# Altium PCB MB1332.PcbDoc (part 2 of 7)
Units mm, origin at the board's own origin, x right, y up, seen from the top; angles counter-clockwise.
Board outline 161 x 75 mm, 6 copper layers (Top Layer, Signal Layer 1, Signal Layer 2, Signal Layer 3, Signal Layer 4, Bottom Layer), stack 1.57 mm thick; 387 components, 358 nets, 1659 pads, 1180 vias.

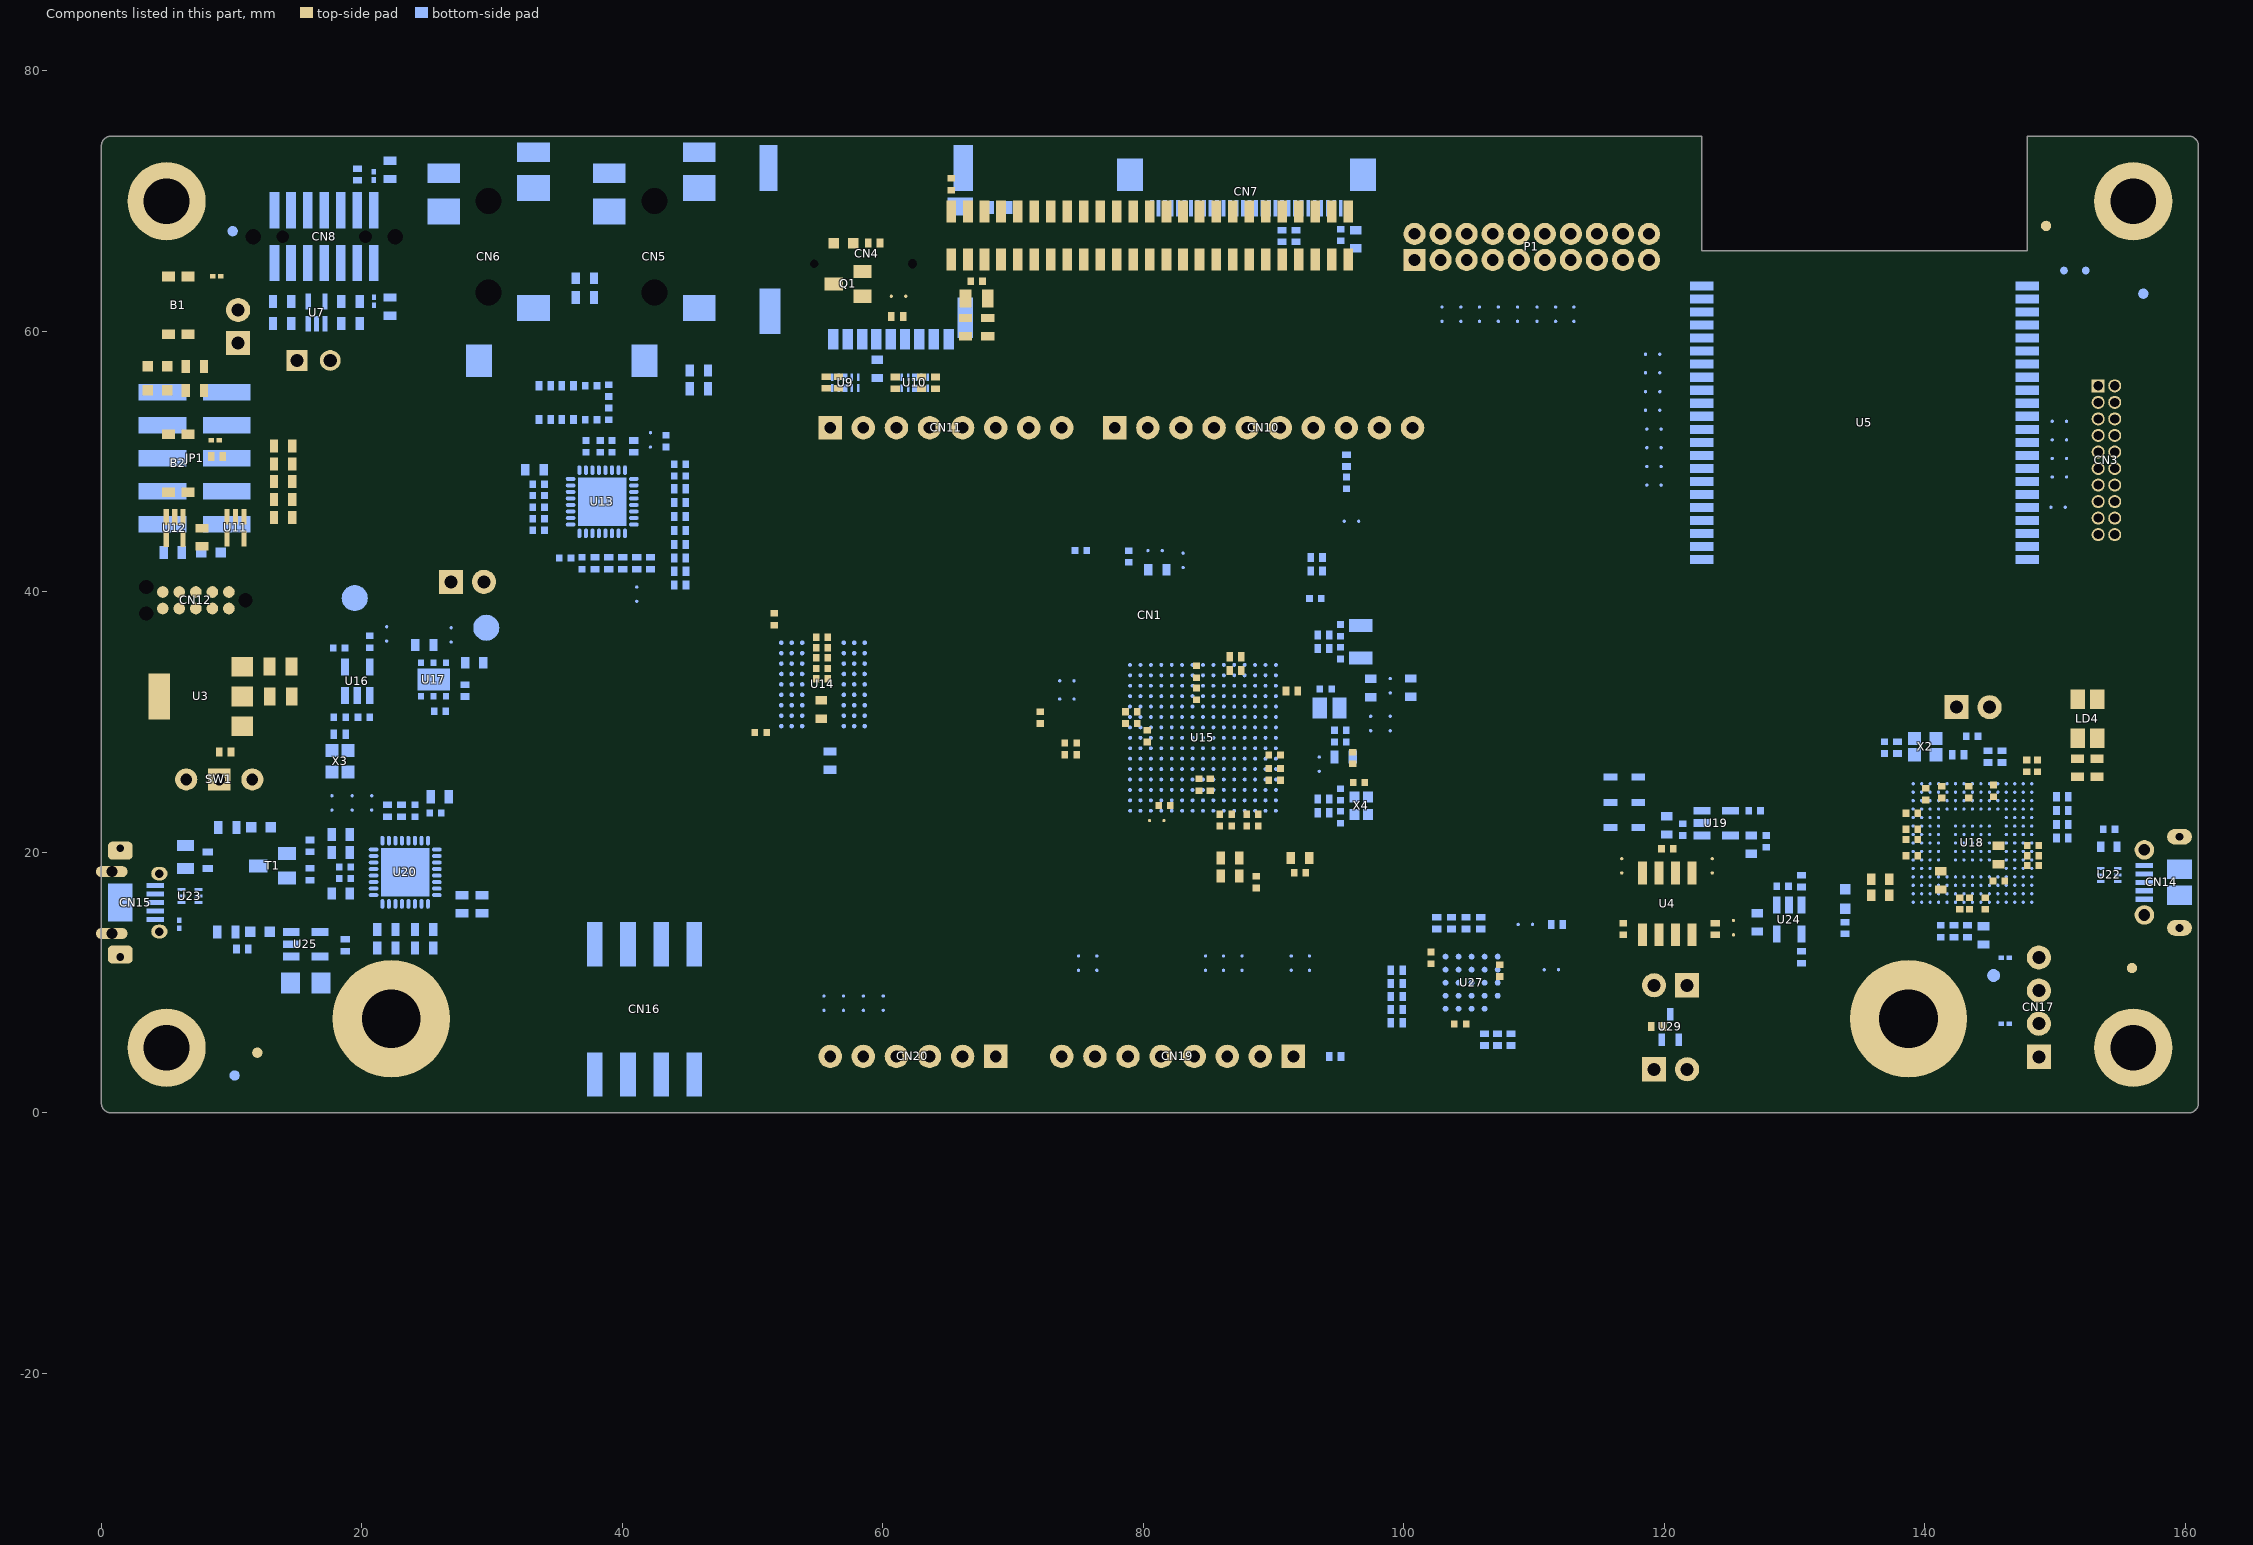
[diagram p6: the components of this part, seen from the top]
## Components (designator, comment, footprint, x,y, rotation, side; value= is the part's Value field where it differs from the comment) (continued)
R81 "Resistor" R0603 18.375,21.375 r180 bottom value=8K06
R82 "Resistor" R0402 150.55,21.1 r180 bottom value=4K7
R83 "Resistor" R0402 16.025,20.5 r270 bottom value=47K
R84 "Resistor" R0805 6.45,19.65 r90 bottom value=0R
R85 "Resistor" R0603 18.375,20 r180 bottom value=820R
R86 "Resistor" R0402 16.025,18.325 r270 bottom value=10K
R87 "Resistor" R0402 130.525,17.8 r270 bottom value=100K
R88 "Resistor" R0603 29.225,16.025 r90 bottom value=0R
R89 "Resistor" R0603 27.7,16.025 r270 bottom value=0R
R90 "Resistor" R0603 9.6,13.9 r180 bottom value=620R
R91 "Resistor" R0402 105.9,14.575 r90 bottom value=33R
R92 "Resistor" R0402 104.775,14.575 r270 bottom value=33R
R93 "Resistor" R0402 103.65,14.575 r90 bottom value=33R
R94 "Resistor" R0402 102.525,14.575 r270 bottom value=33R
R95 "Resistor" R0402 18.725,12.875 r270 bottom value=10K
R96 "Resistor" R0402 133.875,14.2 r270 bottom value=820R
R97 "Resistor" R0402 111.75,14.475 r0 bottom value=10K
R98 "Resistor" R0402 143.275,13.95 r90 bottom value=3K
R99 "Resistor" R0402 142.225,13.95 r270 bottom value=100R
R100 "Resistor" R0603 24.775,14.075 r180 bottom value=0R
R101 "Resistor" R0603 21.875,14.075 r0 bottom value=0R
R102 "Resistor" R0402 10.825,12.6 r180 bottom value=3K3
R103 "Resistor" R0603 24.775,12.65 r0 bottom value=0R
R104 "Resistor" R0603 21.875,12.65 r180 bottom value=0R
R105 "Resistor" R0402 130.525,11.95 r270 bottom value=10K
R106 "Resistor" R0402 99.45,10.95 r0 bottom value=33R
R107 "Resistor" R0402 99.45,9.95 r180 bottom value=33R
R108 "Resistor" R0402 99.45,8.95 r180 bottom value=33R
R109 "Resistor" R0402 99.45,7.95 r0 bottom value=33R
R110 "Resistor" R0402 99.45,6.925 r0 bottom value=33R
R111 "Resistor" R0402 108.225,5.625 r270 bottom value=33R
R112 "Resistor" R0402 107.2,5.625 r270 bottom value=33R
R113 "Resistor" R0402 106.175,5.625 r90 bottom value=10K
R114 "Resistor" R0402 94.725,4.325 r0 bottom value=1K
R115 "Resistor" R0402 61.1,61.15 r180 top value=1M
SB1 "SB_ON" SOLDER-BRIDGE_R0603-0R 61.25,62.7 r180 top value=0R
SB2 "SB_ON" SOLDER-BRIDGE_R0603-0R 81.075,22.448 r180 top value=0R
SB3 "SB_ON" SOLDER-BRIDGE_R0603-0R 116.725,18.925 r90 top value=0R
SB4 "SB_ON" SOLDER-BRIDGE_R0603-0R 123.675,18.925 r90 top value=0R
SB5 "SB_ON" SOLDER-BRIDGE_R0603-0R 125.3,14.175 r90 top value=0R
SB6 "SB_ON" SOLDER-BRIDGE_R0603-0R 104.375,61.275 r90 bottom value=0R
SB7 "SB_ON" SOLDER-BRIDGE_R0603-0R 102.925,61.275 r90 bottom value=0R
SB8 "SB_ON" SOLDER-BRIDGE_R0603-0R 107.25,61.275 r90 bottom value=0R
SB9 "SB_ON" SOLDER-BRIDGE_R0603-0R 105.8,61.275 r90 bottom value=0R
SB10 "SB_ON" SOLDER-BRIDGE_R0603-0R 110.225,61.275 r90 bottom value=0R
SB11 "SB_ON" SOLDER-BRIDGE_R0603-0R 108.725,61.275 r90 bottom value=0R
SB12 "SB_ON" SOLDER-BRIDGE_R0603-0R 113.05,61.275 r90 bottom value=0R
SB13 "SB_ON" SOLDER-BRIDGE_R0603-0R 111.65,61.275 r90 bottom value=0R
SB14 "SB_ON" SOLDER-BRIDGE_R0603-0R 119.15,58.25 r180 bottom value=0R
SB15 "SB_ON" SOLDER-BRIDGE_R0603-0R 119.15,56.825 r180 bottom value=0R
SB16 "SB_ON" SOLDER-BRIDGE_R0603-0R 119.15,55.375 r180 bottom value=0R
SB17 "SB_ON" SOLDER-BRIDGE_R0603-0R 119.15,53.95 r180 bottom value=0R
SB18 "SB_ON" SOLDER-BRIDGE_R0603-0R 150.275,53.1 r0 bottom value=0R
SB19 "SB_ON" SOLDER-BRIDGE_R0603-0R 119.15,52.5 r0 bottom value=0R
SB20 "SB_ON" SOLDER-BRIDGE_R0603-0R 42.15,51.725 r270 bottom value=0R
SB21 "SB_ON" SOLDER-BRIDGE_R0603-0R 150.275,51.675 r0 bottom value=0R
SB22 "SB_ON" SOLDER-BRIDGE_R0603-0R 119.15,51.075 r0 bottom value=0R
SB23 "SB_ON" SOLDER-BRIDGE_R0603-0R 150.275,50.25 r0 bottom value=0R
SB24 "SB_ON" SOLDER-BRIDGE_R0603-0R 119.15,49.625 r0 bottom value=0R
SB25 "SB_ON" SOLDER-BRIDGE_R0603-0R 150.275,48.825 r0 bottom value=0R
SB26 "SB_ON" SOLDER-BRIDGE_R0603-0R 119.15,48.2 r0 bottom value=0R
SB27 "SB_ON" SOLDER-BRIDGE_R0603-0R 150.275,46.5 r180 bottom value=0R
SB28 "SB_ON" SOLDER-BRIDGE_R0603-0R 96.025,45.425 r180 bottom value=0R
SB29 "SB_ON" SOLDER-BRIDGE_R0603-0R 80.85,43.173 r0 bottom value=0R
SB30 "SB_ON" SOLDER-BRIDGE_R0603-0R 83.05,42.473 r270 bottom value=0R
SB31 "SB_ON" SOLDER-BRIDGE_R0603-0R 41.1,39.775 r90 bottom value=0R
SB32 "SB_ON" SOLDER-BRIDGE_R0603-0R 21.9,36.725 r90 bottom value=0R
SB33 "SB_ON" SOLDER-BRIDGE_R0603-0R 26.85,36.65 r90 bottom value=0R
SB34 "SB_ON" SOLDER-BRIDGE_R0603-0R 98.95,32.848 r270 bottom value=0R
SB35 "SB_ON" SOLDER-BRIDGE_R0603-0R 74.075,33.173 r0 bottom value=0R
SB36 "SB_ON" SOLDER-BRIDGE_R0603-0R 74.075,31.773 r0 bottom value=0R
SB37 "SB_ON" SOLDER-BRIDGE_R0603-0R 98.95,29.848 r90 bottom value=0R
SB38 "SB_ON" SOLDER-BRIDGE_R0603-0R 97.45,29.848 r90 bottom value=0R
SB39 "SB_ON" SOLDER-BRIDGE_R0603-0R 93.5,26.723 r90 bottom value=0R
SB40 "SB_ON" SOLDER-BRIDGE_R0603-0R 20.75,23.75 r90 bottom value=0R
SB41 "SB_ON" SOLDER-BRIDGE_R0603-0R 19.25,23.75 r90 bottom value=0R
SB42 "SB_ON" SOLDER-BRIDGE_R0603-0R 17.7,23.75 r90 bottom value=0R
SB43 "SB_ON" SOLDER-BRIDGE_R0603-0R 109.275,14.475 r0 bottom value=0R
SB44 "SB_ON" SOLDER-BRIDGE_R0603-0R 92.75,11.55 r270 bottom value=0R
SB45 "SB_ON" SOLDER-BRIDGE_R0603-0R 91.35,11.55 r270 bottom value=0R
SB46 "SB_ON" SOLDER-BRIDGE_R0603-0R 87.575,11.55 r270 bottom value=0R
SB47 "SB_ON" SOLDER-BRIDGE_R0603-0R 84.775,11.55 r270 bottom value=0R
SB48 "SB_ON" SOLDER-BRIDGE_R0603-0R 76.425,11.55 r270 bottom value=0R
SB49 "SB_ON" SOLDER-BRIDGE_R0603-0R 75.025,11.55 r270 bottom value=0R
SB50 "SB_ON" SOLDER-BRIDGE_R0603-0R 86.15,11.55 r270 bottom value=0R
SB51 "SB_ON" SOLDER-BRIDGE_R0603-0R 111.375,11 r180 bottom value=0R
SB52 "SB_ON" SOLDER-BRIDGE_R0603-0R 60.025,8.475 r270 bottom value=0R
SB53 "SB_ON" SOLDER-BRIDGE_R0603-0R 58.5,8.475 r270 bottom value=0R
SB54 "SB_ON" SOLDER-BRIDGE_R0603-0R 56.975,8.475 r270 bottom value=0R
SB55 "SB_ON" SOLDER-BRIDGE_R0603-0R 55.475,8.475 r270 bottom value=0R
SW1 "SW_MECA_1K2" SWI_EAO_09-03290-01_EXTENDED_STRAIGHT_BLACK 9.05,25.6 r90 top value=09.03290.01
T1 "9013-SOT23" NPN_SOT23 13.15,18.975 r270 bottom value="NPN SOT23"
TP1 "Test Point" TP_SMD_2MM 19.45,39.525 r180 bottom
TP2 "Test Point" TP_SMD_2MM 29.55,37.25 r180 bottom
TP3 "Test Point" TP_SMD_1MM 145.275,10.55 r270 bottom value="Test Point 1mm"
TP4 "Test Point" TP_SMD_0-6MM 152.35,64.675 r90 bottom
TP5 "Test Point" TP_SMD_0-6MM 150.675,64.675 r90 bottom
U1 "ESD-TRANSIL" ESD_ST0201 8.85,64.225 r0 top value=ESDALC6V1-1U2
U2 "ESD-TRANSIL" ESD_ST0201 8.737,51.65 r0 top value=ESDALC6V1-1U2
U3 "LD1117S50TR" REG_SOT223-TAB 7.624,31.972 r90 top
U4 "MCP2562FD" ICC_SO8_5X4_P127 120.225,16.05 r180 top value=MCP2562FDT-H/SN
U5 "WIFI MODULE INTERPOSER" MOD_WIFI_INVENTEK_ISM43362 135.361,54.785 r180 bottom value=MB1486
U6 "ESD-TRANSIL" ESD_ST0201 20.9,71.937 r90 bottom value=ESDALC6V1-1U2
U7 "ESDALC6V1W5" ESD_SOT323-5L 16.525,61.45 r180 bottom
U8 "ESD-TRANSIL" ESD_ST0201 20.925,62.325 r270 bottom value=ESDALC6V1-1U2
U9 "HSP051-4M10" ESD_UQFN-10L_2P5X1_P050 57.1,56.065 r0 bottom
U10 "HSP051-4M10" ESD_UQFN-10L_2P5X1_P050 62.45,56.06 r0 bottom
U11 "ESDALC6V1W5" ESD_SOT323-5L 10.3,44.925 r180 top
U12 "ESDALC6V1W5" ESD_SOT323-5L 5.625,44.9 r180 top
U13 "CS42L51-CNZ" ICC_QFN32-EPAD_5X5_P050 38.45,46.925 r180 bottom
U14 "IS42S16800F-6BLI" ICC_TFBGA54_3X9-BALL-X2_8X8_P080 55.4,32.9 r180 bottom
U15 "STM32H7B3NIH6Q" ICC_TFBGA225_13X13_STM32H7B3NIH6Q_P080 84.575,28.798 r180 bottom value=STM32H7B3LIH6Q
U16 "LD3985M18R" REG_SOT23-5L 19.65,33.15 r180 bottom
U17 "ST1L05CPU33R" ICC_DFN6-EPAD_3X3_P095 25.5,33.275 r180 bottom
U18 "ST-LINKV3E_SWD" ICC_UFBGA201_176+25_10X10_P065 143.65,20.725 r270 bottom value=STM32F723IEK6
U19 "LD3985M33R" REG_SOT23-5L 123.975,22.25 r90 bottom
U20 "USB3320C-EZK" ICC_QFN32-EPAD_5X5_P050 23.325,18.475 r270 bottom value=USB3320C-EZK-TR
U21 "ESD-TRANSIL" ESD_QFN2_1P6X1_P125 8.175,19.4 r90 bottom value=ESDA7P60-1U1M
U22 "ECMF02-2AMX6" ESD_QFN-6L_1P7X1P5_P050 154.15,18.275 r90 bottom
U23 "ECMF02-2AMX6" ESD_QFN-6L_1P7X1P5_P050 6.8,16.65 r270 bottom
U24 "STMPS2151STR" MOS_SOT23-5L 129.575,14.85 r0 bottom
U25 "STMPS2151STR" MOS_SOT23-5L 15.675,12.95 r90 bottom
U26 "ESD-TRANSIL" ESD_ST0201 5.975,14.475 r270 bottom value=ESDALC6V1-1U2
U27 "MX25LM51245GXDI00" ICC_BGA24_5X5-BALL-ARRAY_6X8_P1 105.2,10 r90 bottom
U28 "ESD-TRANSIL" ESD_ST0201 146.175,11.925 r180 bottom value=ESDALC6V1-1U2
U29 "ESD-TRANSIL-DUAL-BIDIR" DIO_SOT323 120.45,6.6 r180 bottom value=ESDCAN02-2BWY
U30 "ESD-TRANSIL" ESD_ST0201 146.175,6.85 r180 bottom value=ESDALC6V1-1U2
X1 "XTAL_2_PINS" CRY_NX3215SA_2P 96.675,36.173 r90 bottom value=32.768KHz
X2 "OSCILLATOR_4_PINS" OSC_NDK_NZ2520SB_4P 140.025,28.125 r0 bottom value=25MHz
X3 "OSCILLATOR_4_PINS" OSC_NDK_NZ2520SB_4P 18.325,27 r270 bottom value=24MHz
X4 "XTAL_4_PINS" CRY_NX2016SA_4P 96.725,23.573 r90 bottom value=24MHz

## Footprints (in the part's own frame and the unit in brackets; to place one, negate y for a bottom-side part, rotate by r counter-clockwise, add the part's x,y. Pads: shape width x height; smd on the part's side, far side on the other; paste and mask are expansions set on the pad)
C0402 [mm]
  rect 0.51x0.56 smd mask+0.05: 1(-0.45,0) 2(0.45,0)
  silkscreen extent 0,-0.3 0,0.3, body extent -0.5,-0.3 0.5,0.3, height 0.4
C0603 [mm]
  rect 0.64x0.89 smd mask+0.05: 1(-0.7,0) 2(0.7,0)
  silkscreen extent -1.05,-0.55 1.02,0.55, body extent -0.9,-0.5 0.9,0.5, height 1.4
C0805 [mm]
  rect 0.9x1.4 smd mask+0.05: 1(-0.85,0) 2(0.85,0)
  silkscreen extent -1.3,-0.77 1.3,0.77, body extent -1.1,-0.7 1.1,0.7, height 1.35
CON_988-JIUBABA_PHFS25-11-02-G0B115-T-1 [mm]
  rect 1.6x1.6 hole 1 mask+0.05: 1(1.27,0)
  round 1.6 hole 1 mask+0.05: 2(-1.27,0)
  silkscreen extent -2.71,-1.33 2.71,1.33, body extent -2.71,-1.33 2.71,1.33, height 8.85
CON_FISCHER_BL1-6-G [mm]
  rect 1.8x1.8 / inner round 1.8 / far side rect 1.8x1.8 hole 0.9 mask+0.05: 1(-6.35,0)
  round 1.8 hole 0.9 mask+0.05: 2(-3.81,0) 3(-1.27,0) 4(1.27,0) 5(3.81,0) 6(6.35,0)
  silkscreen extent -7.62,-1.25 7.62,1.25, body extent -7.62,-1.25 7.62,1.25, height 8
CON_FISCHER_BL1-8-G [mm]
  rect 1.8x1.8 / inner round 1.8 / far side rect 1.8x1.8 hole 0.9 mask+0.05: 1(-8.89,0)
  round 1.8 hole 0.9 mask+0.05: 2(-6.35,0) 3(-3.81,0) 4(-1.27,0) 5(1.27,0) 6(3.81,0) 7(6.35,0) 8(8.89,0)
  silkscreen extent -10.16,-1.25 10.16,1.25, body extent -10.16,-1.25 10.16,1.25, height 8
CON_FISCHER_BL1-10-G [mm]
  rect 1.8x1.8 / inner round 1.8 / far side rect 1.8x1.8 hole 0.9 mask+0.05: 1(-11.43,0)
  round 1.8 hole 0.9 mask+0.05: 2(-8.89,0) 3(-6.35,0) 4(-3.81,0) 5(-1.27,0) 6(1.27,0) 7(3.81,0) 8(6.35,0) 9(8.89,0) 10(11.43,0)
  silkscreen extent -12.7,-1.25 12.71,1.25, body extent -12.7,-1.25 12.7,1.25, height 8
CON_MICROSD_YAMAICHI_PJS008-2003-1 [mm] "WITH POSITIONNING PINS"
  rect 1.6x0.8 smd paste+0 mask+0.05: 1(-15.6,-2.525) 2(-15.6,-1.425) 3(-15.6,-0.325) 4(-15.6,0.775) 5(-15.6,1.875) 6(-15.6,2.975) 7(-15.6,4.075) 8(-15.6,5.175) 9(-15.6,6.325)
  rect 1.4x1.95 smd paste+0 mask+0.05: 10(-5.4,7.225)
  rect 3.5x1.5 smd paste+0 mask+0.05: 11(-2.45,7.45)
  rect 3.5x1.4 smd paste+0 mask+0.05: 12(-2.45,-7.5)
  rect 3.5x1.6 smd paste+0 mask+0.05: 13(-13.45,-7.4)
  rect 3.1x1.2 smd paste+0 mask+0.05: 14(-13.95,7.6)
  round 0 hole 0.65 unplated mask+0.05: NPTH1(-9.8,-4)
  round 0 hole 0.7 unplated mask+0.05: NPTH2(-9.8,3.55)
  silkscreen extent -15.32,-7.25 5.65,7.25, body extent -15.25,-7.25 -0.45,7.42, height 2
CON_PHONE-JACK-3P5_HY_PJ3028B [mm]
  rect 1.5x2.5 smd mask+0.05: 2(1.25,-3.45) 7(2.85,3.45)
  rect 2x2.5 smd mask+0.05: 3(4,-3.45) 4(5.8,3.45) 6(13.2,-3.45)
  rect 2.5x2 smd mask+0.05: 5(17.25,0.75)
  round 0.5 hole 2 unplated mask+0.1: MT1(5,0) MT2(12,0)
  Multi-Layer keep-out circle w0.01: c12,0 r1.25
  Multi-Layer keep-out circle w0.01: c5,0 r1.25
  silkscreen extent -0.9,-3.7 16,3, body extent -0.9,-3 16,3, height 5
CON_SAMTEC_SQT-110-01-F-D-RA__STMOD+ [mm] "SQT-110-01-F-D-RA (connecteur SAMTEC pour interface STMod+ femelle coté Host) Pinning adapté non conforme SAMTEC."
  rect 1.7x1.7 hole 0.9 mask+0.05: 1(9,1)
  round 1.7 hole 0.9 mask+0.05: 2(7,1) 3(5,1) 4(3,1) 5(1,1) 6(-1,1) 7(-3,1) 8(-5,1) 9(-7,1) 10(-9,1) 11(9,-1) 12(7,-1) 13(5,-1) 14(3,-1) 15(1,-1) 16(-1,-1) 17(-3,-1) 18(-5,-1) 19(-7,-1) 20(-9,-1)
  silkscreen extent -10.15,-8.62 10.15,0.07, body extent -10.15,-8.65 10.15,1.22, height 4
CON_SAMTEC_SSM-104-L-DH [mm]
  rect 1.2x3.4 smd mask+0.05: 1(3.81,-5) 2(3.81,5) 3(1.27,-5) 4(1.27,5) 5(-1.27,-5) 6(-1.27,5) 7(-3.81,-5) 8(-3.81,5)
  silkscreen extent -5.08,-4.06 5.08,4.06, body extent -5.08,-5.46 5.1,5.46, height 5.92
CON_SAMTEC_TSM-105-01-L-DV [mm]
  rect 1.27x3.68 smd paste+0 mask+0.05: 1(-5.08,-2.475) 2(-5.08,2.475) 3(-2.54,-2.475) 4(-2.54,2.475) 5(0,-2.475) 6(0,2.475) 7(2.54,-2.475) 8(2.54,2.475) 9(5.08,-2.475) 10(5.08,2.475)
  silkscreen extent -6.35,-2.16 6.35,2.16, body extent -6.35,-3.85 6.35,3.85, height 9.65
CON_SAMTEC_TSW-102-07-G-S [mm]
  rect 1.85x1.85 / inner round 1.85 / far side rect 1.85x1.85 hole 1 mask+0.05: 1(-1.27,0)
  round 1.85 hole 1 mask+0.05: 2(1.27,0)
  silkscreen extent -2.58,-1.3 2.58,1.3, body extent -2.67,-1.3 2.58,1.3, height 8.38
CON_SAMTEC_TSW-104-07-G-S [mm]
  rect 1.85x1.85 / inner round 1.85 / far side rect 1.85x1.85 hole 1 mask+0.05: 1(-3.81,0)
  round 1.85 hole 1 mask+0.05: 2(-1.27,0) 3(1.27,0) 4(3.81,0)
  silkscreen extent -5.12,-1.3 5.12,1.3, body extent -5.21,-1.37 5.18,1.37, height 8.38
CON_STDC14_Receiver_MEDIUM_WITH_MIPI10_3D [mm] "compatible with FTSH-105-01-L-DV,-K and FTSH-107-01-L-DV,-K,-A,-P,-ES"
  round 0 hole 1.19 unplated mask+0.05: 0(-5.445,0) 0(5.445,0)
  round 0 hole 0.97 unplated mask+0.05: 0(-3.175,0) 0(3.175,0)
  rect 0.74x2.79 smd mask+0.05: 1(-3.81,-2.032) 2(-3.81,2.032) 3(-2.54,-2.032) 4(-2.54,2.032) 5(-1.27,-2.032) 6(-1.27,2.032) 7(0,-2.032) 8(0,2.032) 9(1.27,-2.032) 10(1.27,2.032) 11(2.54,-2.032) 12(2.54,2.032) 13(3.81,-2.032) 14(3.81,2.032)
  silkscreen extent -6.3,-4.38 6.3,3.6, body extent -6.3,-2.92 6.3,2.92, height 6.6
CON_TAG-C_TC2050-IDC-NL [mm]
  round 0.9 smd paste+0 mask+0.05: 1(-2.54,-0.635) 2(-1.27,-0.635) 3(0,-0.635) 4(1.27,-0.635) 5(2.54,-0.635) 6(2.54,0.635) 7(1.27,0.635) 8(0,0.635) 9(-1.27,0.635) 10(-2.54,0.635)
  round 0 hole 1.1 unplated mask+0.05: 11(-3.81,0) 12(3.81,-1.015) 13(3.81,1.015)
  Multi-Layer keep-out circle w0.01: c-3.81,0 r0.75
  Multi-Layer keep-out circle w0.01: c3.81,1.015 r0.75
  Multi-Layer keep-out circle w0.01: c3.81,-1.015 r0.75
  silkscreen extent -6.22,-3.4 6.22,3.33, body extent -6.28,-3.46 6.28,3.39, height 13
CON_TOWNES_FPU330ZH-BT1D3-CA_P050 [mm]
  rect 0.3x1.25 smd mask+0.05: 1(-7.25,2.575) 2(-6.75,2.575) 3(-6.25,2.575) 4(-5.75,2.575) 5(-5.25,2.575) 6(-4.75,2.575) 7(-4.25,2.575) 8(-3.75,2.575) 9(-3.25,2.575) 10(-2.75,2.575) 11(-2.25,2.575) 12(-1.75,2.575) 13(-1.25,2.575) 14(-0.75,2.575) 15(-0.25,2.575) 16(0.25,2.575) 17(0.75,2.575) 18(1.25,2.575) 19(1.75,2.575) 20(2.25,2.575) 21(2.75,2.575) 22(3.25,2.575) 23(3.75,2.575) 24(4.25,2.575) 25(4.75,2.575) 26(5.25,2.575) 27(5.75,2.575) 28(6.25,2.575) 29(6.75,2.575) 30(7.25,2.575)
  rect 2x2.5 smd mask+0.05: 31(-8.94,0) 32(8.94,0)
  silkscreen extent -9.7,-2.9 9.7,2.3, body extent -10.25,-4.25 10.25,3, height 2.05
CON_USBMICROAB_MOLEX_47590-0001_H3 [mm]
  rect 0.4x1.35 smd mask+0.05: 1(1.3,4.125) 2(0.65,4.125) 3(0,4.125) 4(-0.65,4.125) 5(-1.3,4.125)
  oval 1.05x1.25 hole 0.65 slot 0.85 at 90 deg mask+0.05: 6(-2.225,4.45) 7(2.225,4.45)
  rrect50% 1.375x1.9 hole 0.6 slot 1.3 at 90 deg copper offset 0.188,0 mask+0.05: 8(-4.175,1.45)
  rrect50% 1.375x1.9 hole 0.6 slot 1.3 at 90 deg copper offset -0.188,0 mask+0.05: 9(4.175,1.45)
  rect 2.9x1.9 smd mask+0.05: 10(0,1.45)
  oval 0.85x2.425 hole 0.85 slot 2.425 at 90 deg unplated mask+0.1: 11(-2.375,0.8) 12(2.375,0.8)
  silkscreen extent -4.1,-1.3 4.1,4.3, body extent -4.32,-1.36 4.33,4.6, height 3
CON_USBMICROB_MOLEX_105017-0001_H2P90 [mm]
  rect 0.4x1.35 smd mask+0.05: 1(-1.3,4.15) 2(-0.65,4.15) 3(0,4.15) 4(0.65,4.15) 5(1.3,4.15)
  round 1.5 hole 0.9 mask+0.05: 6(-2.5,4.15) 7(2.5,4.15)
  oval 1.2x1.9 hole 0.6 slot 1.3 at 90 deg mask+0.05: 8(3.5,1.45) 9(-3.5,1.45)
  rect 1.5x1.9 smd mask+0.05: 10(-1,1.45) 11(1,1.45)
  Top Layer region: 2.3,2.4 3.5,2.4 3.5,0.5 2.3,0.5 2.3,2.4
  Top Layer region: -3.5,2.4 -2.3,2.4 -2.3,0.5 -3.5,0.5 -3.5,2.4
  silkscreen extent -4,-0.7 4,4.6, body extent -4.1,-1.15 4.1,4.66, height 2.9
CPOL_TAJ-A_1206_H180 [mm]
  rect 1.45x1.6 smd mask+0.05: 1(-1.175,0) 2(1.175,0)
  silkscreen extent -2.15,-1.05 1.7,1.05, body extent -1.7,-0.9 1.7,0.9, height 1.8
CRY_NX2016SA_4P [mm]
  rect 0.85x0.75 smd mask+0.05: 1(-0.675,-0.525) 2(0.675,-0.525) 3(0.675,0.525) 4(-0.675,0.525)
  silkscreen extent -1.22,-1.02 1.05,0.85, body extent -1.05,-0.85 1.05,0.85, height 0.7
CRY_NX3215SA_2P [mm]
  rect 1x1.8 smd mask+0.05: 1(-1.25,0) 2(1.25,0)
  silkscreen extent -0.63,-0.8 0.63,0.8, body extent -1.65,-0.8 1.65,0.8, height 0.9
DIO_SOD323 [mm]
  rect 1.06x0.54 smd mask+0.05: 1(-1.07,0) 2(1.07,0)
  silkscreen extent -0.9,-0.72 0.9,0.72, body extent -1.3,-0.78 1.3,0.78, height 1.17
DIO_SOT323 [mm]
  rect 0.5x0.95 smd mask+0.05: 1(-0.65,-0.975) 2(0.65,-0.975) 3(0,0.975)
  silkscreen extent -1.15,-0.67 1.15,0.67, body extent -1.15,-1.12 1.15,1.12, height 1.1
ESD_QFN2_1P6X1_P125 [mm]
  rect 0.55x0.8 smd mask+0.05: 1(-0.625,0) 2(0.625,0)
  silkscreen extent -1,-0.55 0.85,0.55, body extent -0.85,-0.55 0.85,0.55, height 0.61
ESD_QFN-6L_1P7X1P5_P050 [mm]
  rect 0.25x0.6 smd mask+0.05: 1(-0.5,-0.65) 2(0,-0.65) 3(0.5,-0.65) 4(0.5,0.65) 5(0,0.65) 6(-0.5,0.65)
  silkscreen extent -0.9,-0.8 0.9,0.8, body extent -0.9,-0.8 0.9,0.8, height 0.56
ESD_SOT323-5L [mm]
  rect 0.4x1.2 smd mask+0.05: 1(-0.65,-0.85) 2(0,-0.85) 3(0.65,-0.85) 4(0.65,0.85) 5(-0.65,0.85)
  silkscreen extent -1.22,-1.21 1.22,0.77, body extent -1.15,-1.05 1.15,1.05, height 1.1
ESD_ST0201 [mm]
  rect 0.425x0.33 smd mask+0.05: 1(-0.312,0) 2(0.312,0)
  silkscreen extent -0.55,-0.3 0.33,0.3, body extent -0.34,-0.18 0.34,0.18, height 0.34
ESD_UQFN-10L_2P5X1_P050 [mm]
  rect 0.2x0.58 smd mask+0.05: 1(-1,-0.41) 2(-0.5,-0.41) 4(0.5,-0.41) 5(1,-0.41) 6(1,0.41) 7(0.5,0.41) 9(-0.5,0.41) 10(-1,0.41)
  rect 0.4x0.58 smd mask+0.05: 3(0,-0.41) 8(0,0.41)
  silkscreen extent -1.38,-0.63 1.38,0.63, body extent -1.3,-0.55 1.3,0.55, height 0.51
ICC_BGA24_5X5-BALL-ARRAY_6X8_P1 [mm]
  round 0.45 smd mask+0.05: A2(-1,2) A3(0,2) A4(1,2) A5(2,2) B1(-2,1) B2(-1,1) B3(0,1) B4(1,1) B5(2,1) C1(-2,0) C2(-1,0) C3(0,0) C4(1,0) C5(2,0) D1(-2,-1) D2(-1,-1) D3(0,-1) D4(1,-1) D5(2,-1) E1(-2,-2) E2(-1,-2) E3(0,-2) E4(1,-2) E5(2,-2)
  silkscreen extent -3.05,-4.05 3.05,4.05, body extent -3.05,-4.05 3.05,4.05, height 1.2
ICC_DFN6-EPAD_3X3_P095 [mm]
  rect 0.45x0.5 smd mask+0.05: 1(-0.95,-1.3) 2(0,-1.3) 3(0.95,-1.3) 4(0.95,1.3) 5(0,1.3) 6(-0.95,1.3)
  rect 2.5x1.7 smd mask+0.05: EP(0,0)
  silkscreen extent -1.55,-1.55 1.55,1.55, body extent -1.55,-1.55 1.55,1.55, height 1
ICC_QFN32-EPAD_5X5_P050 [mm]
  oval 0.3x0.75 smd mask+0.05: 1(-1.75,-2.425) 2(-1.25,-2.425) 3(-0.75,-2.425) 4(-0.25,-2.425) 5(0.25,-2.425) 6(0.75,-2.425) 7(1.25,-2.425) 8(1.75,-2.425) 17(1.75,2.425) 18(1.25,2.425) 19(0.75,2.425) 20(0.25,2.425) 21(-0.25,2.425) 22(-0.75,2.425) 23(-1.25,2.425) 24(-1.75,2.425)
  oval 0.75x0.3 smd mask+0.05: 9(2.425,-1.75) 10(2.425,-1.25) 11(2.425,-0.75) 12(2.425,-0.25) 13(2.425,0.25) 14(2.425,0.75) 15(2.425,1.25) 16(2.425,1.75) 25(-2.425,1.75) 26(-2.425,1.25) 27(-2.425,0.75) 28(-2.425,0.25) 29(-2.425,-0.25) 30(-2.425,-0.75) 31(-2.425,-1.25) 32(-2.425,-1.75)
  rect 3.7x3.7 smd mask+0.05: 33(0,0)
  silkscreen extent -2.63,-2.63 2.63,2.63, body extent -2.55,-2.55 2.55,2.55, height 1
ICC_SO8_5X4_P127 [mm]
  rect 0.7x1.75 smd mask+0.05: 1(-1.905,-2.375) 2(-0.635,-2.375) 3(0.635,-2.375) 4(1.905,-2.375) 5(1.905,2.375) 6(0.635,2.375) 7(-0.635,2.375) 8(-1.905,2.375)
  silkscreen extent -2.73,-3.25 2.58,2, body extent -2.57,-3 2.57,3, height 1.75
ICC_TFBGA54_3X9-BALL-X2_8X8_P080 [mm] "IPC"
  round 0.35 smd mask+0.05: A1(-3.2,3.2) A2(-2.4,3.2) A3(-1.6,3.2) A7(1.6,3.2) A8(2.4,3.2) A9(3.2,3.2) B1(-3.2,2.4) B2(-2.4,2.4) B3(-1.6,2.4) B7(1.6,2.4) B8(2.4,2.4) B9(3.2,2.4) C1(-3.2,1.6) C2(-2.4,1.6) C3(-1.6,1.6) C7(1.6,1.6) C8(2.4,1.6) C9(3.2,1.6) D1(-3.2,0.8) D2(-2.4,0.8) D3(-1.6,0.8) D7(1.6,0.8) D8(2.4,0.8) D9(3.2,0.8) E1(-3.2,0) E2(-2.4,0) E3(-1.6,0) E7(1.6,0) E8(2.4,0) E9(3.2,0) F1(-3.2,-0.8) F2(-2.4,-0.8) F3(-1.6,-0.8) F7(1.6,-0.8) F8(2.4,-0.8) F9(3.2,-0.8) G1(-3.2,-1.6) G2(-2.4,-1.6) G3(-1.6,-1.6) G7(1.6,-1.6) G8(2.4,-1.6) G9(3.2,-1.6) H1(-3.2,-2.4) H2(-2.4,-2.4) H3(-1.6,-2.4) H7(1.6,-2.4) H8(2.4,-2.4) H9(3.2,-2.4) J1(-3.2,-3.2) J2(-2.4,-3.2) J3(-1.6,-3.2) J7(1.6,-3.2) J8(2.4,-3.2) J9(3.2,-3.2)
  silkscreen extent -4.6,-4.05 4.05,4.05, body extent -4.05,-4.05 4.05,4.05, height 1.21
ICC_TFBGA225_13X13_STM32H7B3NIH6Q_P080 [mm] "IPC"
  round 0.3 smd mask+0.05: A1(-5.6,5.6) A2(-4.8,5.6) A3(-4,5.6) A4(-3.2,5.6) A5(-2.4,5.6) A6(-1.6,5.6) A7(-0.8,5.6) A8(0,5.6) A9(0.8,5.6) A10(1.6,5.6) A11(2.4,5.6) A12(3.2,5.6) A13(4,5.6) A14(4.8,5.6) A15(5.6,5.6) B1(-5.6,4.8) B2(-4.8,4.8) B3(-4,4.8) B4(-3.2,4.8) B5(-2.4,4.8) B6(-1.6,4.8) B7(-0.8,4.8) B8(0,4.8) B9(0.8,4.8) B10(1.6,4.8) B11(2.4,4.8) B12(3.2,4.8) B13(4,4.8) B14(4.8,4.8) B15(5.6,4.8) C1(-5.6,4) C2(-4.8,4) C3(-4,4) C4(-3.2,4) C5(-2.4,4) C6(-1.6,4) C7(-0.8,4) C8(0,4) C9(0.8,4) C10(1.6,4) C11(2.4,4) C12(3.2,4) C13(4,4) C14(4.8,4) C15(5.6,4) D1(-5.6,3.2) D2(-4.8,3.2) D3(-4,3.2) D4(-3.2,3.2) D5(-2.4,3.2) D6(-1.6,3.2) D7(-0.8,3.2) D8(0,3.2) D9(0.8,3.2) D10(1.6,3.2) D11(2.4,3.2) D12(3.2,3.2) D13(4,3.2) D14(4.8,3.2) D15(5.6,3.2) E1(-5.6,2.4) E2(-4.8,2.4) E3(-4,2.4) E4(-3.2,2.4) E5(-2.4,2.4) E6(-1.6,2.4) E7(-0.8,2.4) E8(0,2.4) E9(0.8,2.4) E10(1.6,2.4) E11(2.4,2.4) E12(3.2,2.4) E13(4,2.4) E14(4.8,2.4) E15(5.6,2.4) F1(-5.6,1.6) F2(-4.8,1.6) F3(-4,1.6) F4(-3.2,1.6) F5(-2.4,1.6) F6(-1.6,1.6) F7(-0.8,1.6) F8(0,1.6) F9(0.8,1.6) F10(1.6,1.6) F11(2.4,1.6) F12(3.2,1.6) F13(4,1.6) F14(4.8,1.6) F15(5.6,1.6) G1(-5.6,0.8) G2(-4.8,0.8) G3(-4,0.8) G4(-3.2,0.8) G5(-2.4,0.8) G6(-1.6,0.8) G7(-0.8,0.8) G8(0,0.8) G9(0.8,0.8) G10(1.6,0.8) G11(2.4,0.8) G12(3.2,0.8) G13(4,0.8) G14(4.8,0.8) G15(5.6,0.8) H1(-5.6,0) H2(-4.8,0) H3(-4,0) H4(-3.2,0) H5(-2.4,0) H6(-1.6,0) H7(-0.8,0) H8(0,0) H9(0.8,0) H10(1.6,0) H11(2.4,0) H12(3.2,0) H13(4,0) H14(4.8,0) H15(5.6,0) J1(-5.6,-0.8) J2(-4.8,-0.8) J3(-4,-0.8) J4(-3.2,-0.8) J5(-2.4,-0.8) J6(-1.6,-0.8) J7(-0.8,-0.8) J8(0,-0.8) J9(0.8,-0.8) J10(1.6,-0.8) J11(2.4,-0.8) J12(3.2,-0.8) J13(4,-0.8) J14(4.8,-0.8) J15(5.6,-0.8) K1(-5.6,-1.6) K2(-4.8,-1.6) K3(-4,-1.6) K4(-3.2,-1.6) K5(-2.4,-1.6) K6(-1.6,-1.6) K7(-0.8,-1.6) K8(0,-1.6) K9(0.8,-1.6) K10(1.6,-1.6) K11(2.4,-1.6) K12(3.2,-1.6) K13(4,-1.6) K14(4.8,-1.6) K15(5.6,-1.6) L1(-5.6,-2.4) L2(-4.8,-2.4) L3(-4,-2.4) L4(-3.2,-2.4) L5(-2.4,-2.4) L6(-1.6,-2.4) L7(-0.8,-2.4) L8(0,-2.4) L9(0.8,-2.4) L10(1.6,-2.4) L11(2.4,-2.4) L12(3.2,-2.4) L13(4,-2.4) L14(4.8,-2.4) L15(5.6,-2.4) M1(-5.6,-3.2) M2(-4.8,-3.2) M3(-4,-3.2) M4(-3.2,-3.2) M5(-2.4,-3.2) M6(-1.6,-3.2) M7(-0.8,-3.2) M8(0,-3.2) M9(0.8,-3.2) M10(1.6,-3.2) M11(2.4,-3.2) M12(3.2,-3.2) M13(4,-3.2) M14(4.8,-3.2) M15(5.6,-3.2) N1(-5.6,-4) N2(-4.8,-4) N3(-4,-4) N4(-3.2,-4) N5(-2.4,-4) N6(-1.6,-4) N7(-0.8,-4) N8(0,-4) N9(0.8,-4) N10(1.6,-4) N11(2.4,-4) N12(3.2,-4) N13(4,-4) N14(4.8,-4) N15(5.6,-4) P1(-5.6,-4.8) P2(-4.8,-4.8) P3(-4,-4.8) P4(-3.2,-4.8) P5(-2.4,-4.8) P6(-1.6,-4.8) P7(-0.8,-4.8) P8(0,-4.8) P9(0.8,-4.8) P10(1.6,-4.8) P11(2.4,-4.8) P12(3.2,-4.8) P13(4,-4.8) P14(4.8,-4.8) P15(5.6,-4.8) R1(-5.6,-5.6) R2(-4.8,-5.6) R3(-4,-5.6) R4(-3.2,-5.6) R5(-2.4,-5.6) R6(-1.6,-5.6) R7(-0.8,-5.6) R8(0,-5.6) R9(0.8,-5.6) R10(1.6,-5.6) R11(2.4,-5.6) R12(3.2,-5.6) R13(4,-5.6) R14(4.8,-5.6) R15(5.6,-5.6)
  silkscreen extent -6.7,-6.55 6.55,6.7, body extent -6.55,-6.55 6.55,6.55, height 1.21
ICC_UFBGA201_176+25_10X10_P065 [mm] "IPC"
  round 0.25 smd mask+0.05: A1(-4.55,4.55) A2(-3.9,4.55) A3(-3.25,4.55) A4(-2.6,4.55) A5(-1.95,4.55) A6(-1.3,4.55) A7(-0.65,4.55) A8(0,4.55) A9(0.65,4.55) A10(1.3,4.55) A11(1.95,4.55) A12(2.6,4.55) A13(3.25,4.55) A14(3.9,4.55) A15(4.55,4.55) B1(-4.55,3.9) B2(-3.9,3.9) B3(-3.25,3.9) B4(-2.6,3.9) B5(-1.95,3.9) B6(-1.3,3.9) B7(-0.65,3.9) B8(0,3.9) B9(0.65,3.9) B10(1.3,3.9) B11(1.95,3.9) B12(2.6,3.9) B13(3.25,3.9) B14(3.9,3.9) B15(4.55,3.9) C1(-4.55,3.25) C2(-3.9,3.25) C3(-3.25,3.25) C4(-2.6,3.25) C5(-1.95,3.25) C6(-1.3,3.25) C7(-0.65,3.25) C8(0,3.25) C9(0.65,3.25) C10(1.3,3.25) C11(1.95,3.25) C12(2.6,3.25) C13(3.25,3.25) C14(3.9,3.25) C15(4.55,3.25) D1(-4.55,2.6) D2(-3.9,2.6) D3(-3.25,2.6) D4(-2.6,2.6) D5(-1.95,2.6) D6(-1.3,2.6) D7(-0.65,2.6) D8(0,2.6) D9(0.65,2.6) D10(1.3,2.6) D11(1.95,2.6) D12(2.6,2.6) D13(3.25,2.6) D14(3.9,2.6) D15(4.55,2.6) E1(-4.55,1.95) E2(-3.9,1.95) E3(-3.25,1.95) E4(-2.6,1.95) E12(2.6,1.95) E13(3.25,1.95) E14(3.9,1.95) E15(4.55,1.95) F1(-4.55,1.3) F2(-3.9,1.3) F3(-3.25,1.3) F4(-2.6,1.3) F6(-1.3,1.3) F7(-0.65,1.3) F8(0,1.3) F9(0.65,1.3) F10(1.3,1.3) F12(2.6,1.3) F13(3.25,1.3) F14(3.9,1.3) F15(4.55,1.3) G1(-4.55,0.65) G2(-3.9,0.65) G3(-3.25,0.65) G4(-2.6,0.65) G6(-1.3,0.65) G7(-0.65,0.65) G8(0,0.65) G9(0.65,0.65) G10(1.3,0.65) G12(2.6,0.65) G13(3.25,0.65) G14(3.9,0.65) G15(4.55,0.65) H1(-4.55,0) H2(-3.9,0) H3(-3.25,0) H4(-2.6,0) H6(-1.3,0) H7(-0.65,0) H8(0,0) H9(0.65,0) H10(1.3,0) H12(2.6,0) H13(3.25,0) H14(3.9,0) H15(4.55,0) J1(-4.55,-0.65) J2(-3.9,-0.65) J3(-3.25,-0.65) J4(-2.6,-0.65) J6(-1.3,-0.65) J7(-0.65,-0.65) J8(0,-0.65) J9(0.65,-0.65) J10(1.3,-0.65) J12(2.6,-0.65) J13(3.25,-0.65) J14(3.9,-0.65) J15(4.55,-0.65) K1(-4.55,-1.3) K2(-3.9,-1.3) K3(-3.25,-1.3) K4(-2.6,-1.3) K6(-1.3,-1.3) K7(-0.65,-1.3) K8(0,-1.3) K9(0.65,-1.3) K10(1.3,-1.3) K12(2.6,-1.3) K13(3.25,-1.3) K14(3.9,-1.3) K15(4.55,-1.3) L1(-4.55,-1.95) L2(-3.9,-1.95) L3(-3.25,-1.95) L4(-2.6,-1.95) L12(2.6,-1.95) L13(3.25,-1.95) L14(3.9,-1.95) L15(4.55,-1.95) M1(-4.55,-2.6) M2(-3.9,-2.6) M3(-3.25,-2.6) M4(-2.6,-2.6) M5(-1.95,-2.6) M6(-1.3,-2.6) M7(-0.65,-2.6) M8(0,-2.6) M9(0.65,-2.6) M10(1.3,-2.6) M11(1.95,-2.6) M12(2.6,-2.6) M13(3.25,-2.6) M14(3.9,-2.6) M15(4.55,-2.6) N1(-4.55,-3.25) N2(-3.9,-3.25) N3(-3.25,-3.25) N4(-2.6,-3.25) N5(-1.95,-3.25) N6(-1.3,-3.25) N7(-0.65,-3.25) N8(0,-3.25) N9(0.65,-3.25) N10(1.3,-3.25) N11(1.95,-3.25) N12(2.6,-3.25) N13(3.25,-3.25) N14(3.9,-3.25) N15(4.55,-3.25) P1(-4.55,-3.9) P2(-3.9,-3.9) P3(-3.25,-3.9) P4(-2.6,-3.9) P5(-1.95,-3.9) P6(-1.3,-3.9) P7(-0.65,-3.9) P8(0,-3.9) P9(0.65,-3.9) P10(1.3,-3.9) P11(1.95,-3.9) P12(2.6,-3.9) P13(3.25,-3.9) P14(3.9,-3.9) P15(4.55,-3.9) R1(-4.55,-4.55) R2(-3.9,-4.55) R3(-3.25,-4.55) R4(-2.6,-4.55) R5(-1.95,-4.55) R6(-1.3,-4.55) R7(-0.65,-4.55) R8(0,-4.55) R9(0.65,-4.55) R10(1.3,-4.55) R11(1.95,-4.55) R12(2.6,-4.55) R13(3.25,-4.55) R14(3.9,-4.55) R15(4.55,-4.55)
  silkscreen extent -5.22,-5.07 5.07,5.23, body extent -5.07,-5.07 5.07,5.07, height 0.61
L0805_H0P9 [mm]
  rect 1.1x1.6 smd mask+0.05: 1(-0.75,0) 2(0.75,0)
  silkscreen extent -0.08,-0.7 0.08,0.7, body extent -1.07,-0.7 1.07,0.7, height 1.2
LED_0603_OSRAM_LB-Q39G-L2OO-35-1_BLUE_1A2K_H0P4 [mm]
  rect 0.8x0.8 smd mask+0.05: 1(-0.75,0) 2(0.75,0)
  silkscreen extent -0.85,-0.53 1.28,0.53, body extent -0.85,-0.45 0.85,0.45, height 0.6
LED_0603_VISHAY_VLMS1300-GS08_RED_1A2K_H0P8 [mm]
  rect 0.8x0.8 smd mask+0.05: 1(-0.75,0) 2(0.75,0)
  silkscreen extent -0.85,-0.53 1.28,0.53, body extent -0.85,-0.45 0.85,0.45, height 0.8
LED_0603_VISHAY_VLMTG1300-GS08_GREEN_1A2K_H0P8 [mm]
  rect 0.8x0.8 smd mask+0.05: 1(-0.75,0) 2(0.75,0)
  silkscreen extent -0.85,-0.53 1.28,0.53, body extent -0.85,-0.45 0.85,0.45, height 0.8
LED_BI-GR_HSMF-A201-A00J1 [mm]
  rect 1.1x1.5 smd mask+0.05: 1(-0.75,-1.5) 2(-0.75,1.5) 3(0.75,1.5) 4(0.75,-1.5)
  silkscreen extent -1.65,-1.85 1.65,1.85, body extent -1.5,-1.85 1.5,1.85, height 2.1
LOGO_ETIQUETTE [mm]
  silkscreen extent 0,0 27,10
MIRE_PLACE_SMD_0P8MM [mm]
  round 0.8 smd paste-10 mask+0.2: 1(0,0)
  Top Layer keep-out circle w0.01: c0,0 r0.804
MOD_LCD_MB1046B__CON_SAMTEC_FLE-125-01-G-DV [mm]
  rect 0.74x1.675 smd mask+0.05: 1(15.24,-9.469) 2(15.24,-5.783) 3(13.97,-9.469) 4(13.97,-5.783) 5(12.7,-9.469) 6(12.7,-5.783) 7(11.43,-9.469) 8(11.43,-5.783) 9(10.16,-9.469) 10(10.16,-5.783) 11(8.89,-9.469) 12(8.89,-5.783) 13(7.62,-9.469) 14(7.62,-5.783) 15(6.35,-9.469) 16(6.35,-5.783) 17(5.08,-9.469) 18(5.08,-5.783) 19(3.81,-9.469) 20(3.81,-5.783) 21(2.54,-9.469) 22(2.54,-5.783) 23(1.27,-9.469) 24(1.27,-5.783) 25(0,-9.469) 26(0,-5.783) 27(-1.27,-9.469) 28(-1.27,-5.783) 29(-2.54,-9.469) 30(-2.54,-5.783) 31(-3.81,-9.469) 32(-3.81,-5.783) 33(-5.08,-9.469) 34(-5.08,-5.783) 35(-6.35,-9.469) 36(-6.35,-5.783) 37(-7.62,-9.469) 38(-7.62,-5.783) 39(-8.89,-9.469) 40(-8.89,-5.783) 41(-10.16,-9.469) 42(-10.16,-5.783) 43(-11.43,-9.469) 44(-11.43,-5.783) 45(-12.7,-9.469) 46(-12.7,-5.783) 47(-13.97,-9.469) 48(-13.97,-5.783) 49(-15.24,-9.469) 50(-15.24,-5.783)
  round 9 hole 4.5 mask+0.05: PTH1(-58.24,-67.77) PTH2(58.24,-67.77)
  silkscreen extent -63.5,-73 63.5,0, body extent -63.5,-73 63.5,0, height 10.2
MOD_MICRO_MB1299_CON_FCI_20021311-XXX20XXLF [mm] "MB1299 MICROPHONE MEMS"
  rect 1x1 / inner round 1 / far side rect 1x1 hole 0.7 mask+0.05: 1(-5.715,-0.635)
  round 1 hole 0.7 mask+0.05: 2(-5.715,0.635) 3(-4.445,-0.635) 4(-4.445,0.635) 5(-3.175,-0.635) 6(-3.175,0.635) 7(-1.905,-0.635) 8(-1.905,0.635) 9(-0.635,-0.635) 10(-0.635,0.635) 11(0.635,-0.635) 12(0.635,0.635) 13(1.905,-0.635) 14(1.905,0.635) 15(3.175,-0.635) 16(3.175,0.635) 17(4.445,-0.635) 18(4.445,0.635) 19(5.715,-0.635) 20(5.715,0.635)
  silkscreen extent -9.2,-7 9.2,7, body extent -9.2,-7 9.2,7, height 8.2
MOD_WIFI_INVENTEK_ISM43362 [mm]
  rect 1.8x0.7 smd mask+0.1: 1(12.5,-12.3) 2(12.5,-11.3) 3(12.5,-10.3) 4(12.5,-9.3) 5(12.5,-8.3) 6(12.5,-7.3) 7(12.5,-6.3) 8(12.5,-5.3) 9(12.5,-4.3) 10(12.5,-3.3) 11(12.5,-2.3) 12(12.5,-1.3) 13(12.5,-0.3) 14(12.5,0.7) 15(12.5,1.7) 16(12.5,2.7) 17(12.5,3.7) 18(12.5,4.7) 19(12.5,5.7) 20(12.5,6.7) 21(12.5,7.7) 22(12.5,8.7) 23(-12.5,8.7) 24(-12.5,7.7) 25(-12.5,6.7) 26(-12.5,5.7) 27(-12.5,4.7) 28(-12.5,3.7) 29(-12.5,2.7) 30(-12.5,1.7) 31(-12.5,0.7) 32(-12.5,-0.3) 33(-12.5,-1.3) 34(-12.5,-2.3) 35(-12.5,-3.3) 36(-12.5,-4.3) 37(-12.5,-5.3) 38(-12.5,-6.3) 39(-12.5,-7.3) 40(-12.5,-8.3) 41(-12.5,-9.3) 42(-12.5,-10.3) 43(-12.5,-11.3) 44(-12.5,-12.3)
  Keep-Out Layer region: -12.5,20 12.5,20 12.5,10 -12.5,10
  silkscreen extent -12.7,-20.2 13.4,20.2, body extent -12.5,-20 12.5,20.19, height 4.1
MOS_SOT23 [mm]
  rect 1x1.4 smd mask+0.05: 1(-0.95,-1.1) 2(0.95,-1.1) 3(0,1.1)
  silkscreen extent -1.63,-0.82 1.63,0.82, body extent -1.56,-1.25 1.56,1.25, height 1.1
MOS_SOT23-5L [mm]
  rect 0.6x1.3 smd mask+0.05: 1(-0.95,-1.1) 2(0,-1.1) 3(0.95,-1.1) 4(0.95,1.1) 5(-0.95,1.1)
  silkscreen extent -1.6,-0.95 1.6,0.97, body extent -1.52,-1.25 1.52,1.25, height 1.45
NPN_SOT23 [mm]
  rect 1x1.4 smd mask+0.05: 1(-0.95,-1.1) 2(0.95,-1.1) 3(0,1.1)
  silkscreen extent -1.63,-0.82 1.63,0.82, body extent -1.56,-1.25 1.56,1.25, height 1.1
OSC_NDK_NZ2520SB_4P [mm]
  rect 1x1 smd mask+0.05: 1(-0.825,-0.625) 2(0.825,-0.625) 3(0.825,0.625) 4(-0.825,0.625)
  silkscreen extent -1.43,-1.22 1.2,1.05, body extent -1.3,-1.05 1.3,1.05, height 0.91
PTH_M1261-3005-N_3P5X6_M3_H14 [mm]
  round 6 hole 3.5 mask+0.05: 1(0,0)
  silkscreen extent -3.25,-3.25 3.25,3.25, body extent -2.5,-2.5 2.5,2.5, height 14
R0402 [mm]
  rect 0.51x0.7 smd mask+0.05: 1(-0.45,0) 2(0.45,0)
  silkscreen extent 0,-0.3 0,0.3, body extent -0.52,-0.3 0.52,0.3, height 0.4
R0603 [mm]
  rect 0.64x1 smd mask+0.05: 1(-0.7,0) 2(0.7,0)
  silkscreen extent -1.05,-0.58 1.05,0.58, body extent -0.9,-0.5 0.9,0.5, height 0.56
R0805 [mm]
  rect 0.85x1.3 smd mask+0.05: 1(-0.875,0) 2(0.875,0)
  silkscreen extent -0.33,-0.67 0.33,0.67, body extent -1.05,-0.68 1.05,0.68, height 0.65
REG_SOT23-5L [mm]
  rect 0.6x1.3 smd mask+0.05: 1(-0.95,-1.1) 2(0,-1.1) 3(0.95,-1.1) 4(0.95,1.1) 5(-0.95,1.1)
  silkscreen extent -1.6,-0.95 1.6,0.97, body extent -1.52,-1.25 1.52,1.25, height 1.1
REG_SOT223-TAB [mm]
  rect 1.5x1.65 smd mask+0.05: 1(-2.3,-3.175) 2(0,-3.175) 3(2.3,-3.175)
  rect 3.5x1.65 smd mask+0.05: 4(0,3.175)
  silkscreen extent -3.35,-2.15 3.35,2.12, body extent -3.35,-3.48 3.35,3.48, height 1.8
SOLDER-BRIDGE_R0603-0R [mil]
  round 10 smd paste-393.7: 1(-19.68,0) 2(23.62,0)
  Top Layer region: -47.24,-19.68 -47.24,19.68 -15.75,19.68 3.94,0 -15.75,-19.68 -47.24,-19.68
  Top Layer region: -5.91,19.68 13.78,0 -5.91,-19.68 47.24,-19.68 47.24,19.68 -5.91,19.68
  silkscreen extent -50,-23 50,23, body extent -36,-20 36,20, height 22
SWI_EAO_09-03290-01_EXTENDED_STRAIGHT_BLACK [mm]
  rect 1.7x1.7 hole 0.9 mask+0.05: 1(0,0)
  round 1.7 hole 0.9 mask+0.05: 2(0,-2.54) 3(0,2.54)
  silkscreen extent -1.25,-5 1.25,5, body extent -1.25,-5 1.25,5, height 7.9
SWI_JIUBABA_C-TS-02H-2-5-B-V-T_R_BLUE [mm] "BLUE"
  rect 0.75x1 smd mask+0.05: 1(-2.225,0.75) 2(2.225,0.75) 3(-2.225,-0.75) 4(2.225,-0.75)
  silkscreen extent -1.85,-1.6 1.85,1.6, body extent -2.45,-1.6 2.45,1.6, height 2.6
SWI_JIUBABA_C-TS-02H-2-5-K-V-T_R_BLACK [mm] "BLACK"
  rect 0.75x1 smd mask+0.05: 1(-2.225,0.75) 2(2.225,0.75) 3(-2.225,-0.75) 4(2.225,-0.75)
  silkscreen extent -1.85,-1.6 1.85,1.6, body extent -2.45,-1.6 2.45,1.6, height 2.6
TP_SMD_0-6MM [mm]
  round 0.6 smd paste-10 mask+0.05: 1(0,0)
  silkscreen extent -0.5,-0.5 0.5,0.5
TP_SMD_1MM [mm]
  round 1 smd paste-10 mask+0.05: 1(0,0)
  silkscreen extent -0.7,-0.7 0.7,0.7
TP_SMD_2MM [mm]
  round 2 smd paste-10 mask+0.05: 1(0,0)
  silkscreen extent -1.2,-1.2 1.2,1.2

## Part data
B1: library part MCD-00171, "Switch HW SMD black", Manufacturer=JIUBABA, Manufacturer_Part_Number="C-TS-02H-2.5-K-V-T/R BLACK", Package=3x4.6m
B2: library part MCD-00172, "Switch HW SMD blue", Manufacturer=JIUBABA, Manufacturer_Part_Number="C-TS-02H-2.5-B-V-T/R BLUE", Package=3x4.6m
C1 C2 C4 C6 C7 C9 C10 C11 C12 C13 C15 C16 C17 C18 C19 C20 C21 C22 C23 C24 C25 C27 C28 C29 C30 C31 C32 C33 C34 C35 C36 C38 C39 C40 C41 C42 C43 C45 C47 C48 C49 C51 C53 C54 C56 C57 C58 C59 C60 C61 C62 C63 C72 C75 C78 C79 C83 C85 C86 C88 C90 C100 C102 C104 C106 C108 C111 C113 C116 C117 C118 C119: library part MCD-00006, "Capacitor, MLCC, 100nF, 16V, X7R, +/-10%, 0402, T=0.5mm", Manufacturer=YAGEO, Manufacturer_Part_Number=CC0402KRX7R7BB104, Package=0402
C3 C5 C8: library part MCD-00014, "Capacitor, MLCC, 10uF, 25V, X5R, 10%, 0805, T=0,85mm", Manufacturer=YAGEO, Manufacturer_Part_Number=CC0805KRX5R8BB106, Package=0805
C14 C66: library part MCD-01721, "Capacitor, 4.7uF, 10V, X5R, 10%, 0603, T=0.8mm", Manufacturer=YAGEO, Manufacturer_Part_Number=CC0603KRX5R6BB475, Package=0603
C26 C37 C69 C71 C76 C80 C81 C82 C84 C87: library part MCD-01722, "Capacitor, 1uF, 10V, X5R, 10%, 0402, T=0.5mm", Manufacturer=YAGEO, Manufacturer_Part_Number=CC0402KRX5R6BB105, Package=0402
C44 C50 C120 C123: library part MCD-00012, "Capacitor, MLCC, 2.2uF, 10V, X5R, 10%, 0603, T=0,8mm", Alternate_Manufacturer=KEMET, Alternate_Manufacturer_Part_Number=C0603C225K8PACTU, Manufacturer=YAGEO, Manufacturer_Part_Number=CC0603KRX5R6BB225, Package=0603
C46 C52 C93 C96: library part MCD-00009, "Capacitor, MLCC, 4.7uF, 16V, X5R, 10%, 0603, T=0.8mm", Manufacturer=YAGEO, Manufacturer_Part_Number=CC0603KRX5R7BB475, Package=0603
C55 C89 C112 C115 C121: library part MCD-00010, "Capacitor, MLCC, 1uF, 16V, X5R, 10%, 0603, T=0,8mm", Manufacturer=YAGEO, Manufacturer_Part_Number=CC0603KRX5R7BB105, Package=0603
C64 C77: library part MCD-00098, "Capacitor, MLCC, 10uF, 6V3, X5R, 10%, 0603, T=0,8mm", Manufacturer=YAGEO, Manufacturer_Part_Number=CC0603KRX5R5BB106, Package=0603
C65 C67: library part MCD-00555, "Capacitor, MLCC, 22nF, 10%, 25V, X7R, 0603, T=0,8mm", Manufacturer=YAGEO, Manufacturer_Part_Number=CC0603KRX7R8BB223, Package=0603
C68 C70: library part MCD-00694, "Capacitor, MLCC, 1.8nF, 50V, X7R, 10%, 0402, T=0.5mm", Manufacturer=YAGEO, Manufacturer_Part_Number=CC0402KRX7R9BB182, Package=0402
C73 C74: library part MCD-00672, "Capacitor, MLCC, 150pF, 50V, NPO, 5%, 0402, T=0,5mm", Manufacturer=YAGEO, Manufacturer_Part_Number=CC0402JRNPO9BN151, Package=0402
C91 C95: library part MCD-00563, "Capacitor, MLCC, 1.5pF, 50V, NPO, +-0.25pF, 0402, T=0,5mm", Manufacturer=YAGEO, Manufacturer_Part_Number=CC0402CRNPO9BN1R5, Package=0402
C92 C101: library part MCD-00095, "Capacitor, MLCC, 1uF, 6V3, X5R, 10%, 0402, T=0,5mm", Alternate_Manufacturer=MURATA, Alternate_Manufacturer_Part_Number=GRM155R60J105KE19, Manufacturer_Part_Number=GRM155R61E105KA12, Package=0402
C94 C109: library part MCD-00011, "Capacitor, MLCC, 10nF, 16V, X7R, 10%, 0402, T=0.5mm", Manufacturer=YAGEO, Manufacturer_Part_Number=CC0402KRX7R7BB103, Package=0402
C97: library part MCD-01121, "Capacitor, MLCC, 4.7uF, 10V, X5R, +/-20%, 0603, T=0.8mm", Manufacturer=MURATA, Manufacturer_Part_Number=GRM188R61A475ME15, Package=0603
C98: library part MCD-00243, "Capacitor, MLCC, 10uF, 6V3, X5R, 10%, 0603, T=0,8mm", Manufacturer=YAGEO, Manufacturer_Part_Number=CC0603KRX5R5BB106, Package=0603
C99 C114: library part MCD-00205, "Capacitor, MLCC, 100pF, 50V, NPO, 5%, 0402, T=0,5mm", Manufacturer=YAGEO, Manufacturer_Part_Number=CC0402JRNPO9BN101, Package=0402
C103 C105: library part MCD-01716, "Capacitor, MLCC, 10uF, 6V3, X5R, 20%, 0402, T=0.5mm", Manufacturer=YAGEO, Manufacturer_Part_Number=CC0402MRX5R5BB106, Package=0402
C107 C110: library part MCD-01727, "Capacitor, MLCC, 2.7pF, 50V, NPO, -+0.25pF 0402", Manufacturer=YAGEO, Manufacturer_Part_Number=CC0402CRNPO9BN2R7, Package=0402
C122: library part MCD-00016, "Capacitor, MLCC, 20pF, 50V, NPO, 5%, 0402, T=0,5mm", Manufacturer=YAGEO, Manufacturer_Part_Number=CC0402JRNPO9BN200, Package=0402
C124: library part MCD-00007, "Capacitor, Tantalum, 4.7uF, 16V, 10%, TypeA", Manufacturer=AVX, Manufacturer_Part_Number=TAJA475K016R, Package="3216 (metric)"
CN1: library part MCD-01222, "Header 25x2 for MB1046 - LCD 4.3 inches daughter board", Alternate_Manufacturer=JIUBABA, Alternate_Manufacturer_Part_Number=234250M1410, Manufacturer=SAMTEC, Manufacturer_Part_Number=FLE-125-01-G-DV
CN2 CN13 CN18 CN21: library part MCD-00032, "Header, 2x1, 2,54mm, VR, TH, Height 5.84mm/2.54mm", Alternate_Manufacturer=JIUBABA, Alternate_Manufacturer_Part_Number=313102S111116, Manufacturer=SAMTEC, Manufacturer_Part_Number=TSW-102-07-G-S
CN3: library part MCD-00147, "Socket for MB1299, 10x2, 1.27mm, VR, TH, Height 4.30mm/2.40mm", Alternate_Manufacturer=JIUBABA, Alternate_Manufacturer_Part_Number=234220S1410, Manufacturer="AMPHENOL ICC", Manufacturer_Part_Number=20021311-00020T4LF
CN4: library part MCD-00023, "MicroSD Card Conn, Reversed-Type, Mnt Push-Push, Positionning holes", Manufacturer=YAMAICHI, Manufacturer_Part_Number=PJS008-2003-1
CN5: library part MCD-00018, "Connector Jack socket Stereo 3.5mm, 3 pins, RA, SMT, Green (Line output)", Alternate_Manufacturer=QIAOD, Alternate_Manufacturer_Part_Number=PJ30280-3_GR, Manufacturer_Part_Number=PJ3028B-3_GR
CN6: library part MCD-00682, "Connector Jack socket Stereo 3.5mm, 3 pins, RA, SMT, Blue (Line input)", Alternate_Manufacturer=QIAOD, Alternate_Manufacturer_Part_Number=PJ30280-3_BE, Manufacturer_Part_Number=PJ3028B-3_BE
CN7: library part MCD-00326, "Connector FFC/FPC ZIF 0.5mm 30 pins, Lower Contacts", Manufacturer=TOWNES
CN8: library part MCD-01226, "Header 5x2, 1.27mm, Dual row, Straight, Surface mount, vertical male connector. 3.05mm lead. Mates with FFSD connector. Footprint compatible with FTSH-107-01-L-DV,-K,-A,-P,-ES (STDC14 MEDIUM)", Manufacturer=SAMTEC, Manufacturer_Part_Number=FTSH-105-01-L-DV-K
CN9: library part MCD-00314, "Header, 2x1, 2.54mm, VR, TH, Height 6mm/3mm", Manufacturer=JIUBABA, Manufacturer_Part_Number=PHFS25-11-02-G0B115-T-1
CN10: library part MCD-00024, "Socket, 10x1, 2.54mm, VR, TH, Height 8mm/3.3mm", Alternate_Manufacturer=JIUBABA, Alternate_Manufacturer_Part_Number=218110S1610, Manufacturer="FISCHER ELECTRONIK", Manufacturer_Part_Number="BL 1-10 G"
CN11 CN19: library part MCD-00025, "Socket, 8x1, 2.54mm, VR, TH, Height 8mm/3.3mm", Alternate_Manufacturer=JIUBABA, Alternate_Manufacturer_Part_Number=218108S1610, Manufacturer="FISCHER ELECTRONIK", Manufacturer_Part_Number="BL 1-8 G"
CN12: library part MCD-00031, "Tag_Connector Header, 10x2, No legs", Manufacturer=N/A
CN14: library part MCD-00028, "USB-MICRO-B, 0.65mm, RA, SMT, Bottom Mount,", Manufacturer=MOLEX, Manufacturer_Part_Number=1050170001
CN15: library part MCD-00661, "USB-MICRO-AB Receptacle, RA, SMT + DIP, Standard, Top Mount, USB certified (symbol & footprint compatible with MCD-00022)", Manufacturer=HIROSE, Manufacturer_Part_Number=ZX62RD-AB-5P8(30)
CN16: library part MCD-00131, "Socket, 4x2, 2.54mm, RA, SMT, Height 5.72mm", Alternate_Manufacturer=JIUBABA, Alternate_Manufacturer_Part_Number=F206A-2x04MGF-LA, Manufacturer=SAMTEC, Manufacturer_Part_Number=SSM-104-L-DH
CN17: library part MCD-00029, "Header, 4x1, 2,54mm, VR, TH, Height 5.84mm/2.54mm", Manufacturer=SAMTEC, Manufacturer_Part_Number=TSW-104-07-G-S
CN20: library part MCD-00026, "Socket, 6x1, 2.54mm, VR, TH, Height 8mm/3.3mm", Alternate_Manufacturer=JIUBABA, Alternate_Manufacturer_Part_Number=218106S1610, Manufacturer="FISCHER ELECTRONIK", Manufacturer_Part_Number="BL 1-6 G"
D1 D2 D3: library part MCD-00034, Manufacturer=STMICROELECTRONICS, Manufacturer_HQ_COO=EU, Package=SOD323
D4 U21: library part MCD-00251, "High power transient voltage suppressor, 7V breakdown", Manufacturer=STMICROELECTRONICS, Manufacturer_HQ_COO=EU, Manufacturer_Part_Number=ESDA7P60-1U1M, Package=QFN1610
H1 H2 H3 H4: library part MCD-00035, Manufacturer=n/a, Manufacturer_HQ_COO=Unknown
JP1: library part MCD-01230, "Header, 5x2, 2.54mm, VR, SMT, Height 5.84mm", Alternate_Manufacturer=JIUBABA, Alternate_Manufacturer_Part_Number=PHFM25-1205G0B116T1, Manufacturer=SAMTEC, Manufacturer_Part_Number=TSM-105-01-L-DV
JP2: library part MCD-00045, "Header, 2x1, 2,54mm, VR, TH, Height 5.84mm/2.54mm", Alternate_Manufacturer=JIUBABA, Alternate_Manufacturer_Part_Number=313102S111116, Manufacturer=SAMTEC, Manufacturer_Part_Number=TSW-102-07-G-S
L1: library part MCD-01340, "Inductor, 2.2uH, 20%, Isat 1.2A, DCR 0.228Ohm, 0805", Manufacturer=MURATA, Manufacturer_Part_Number=DFE201210U-2R2M{}P2, Package=0805
LD1 LD6: library part MCD-00588, "LED Green, 0603 SMD, Forward Voltage Typ=2V, Max=2.5V", Alternate_Manufacturer="VISHAY SEMICONDUCTOR OPTO DIVISION", Alternate_Manufacturer_Part_Number=VLMTG1300-GS08, Manufacturer="OSRAM OPTO SEMICONDUCTORS", Manufacturer_Part_Number="LG Q396-PS-35", Package=0603
LD2: library part MCD-00585, "LED Blue, 0603 SMD, Forward Voltage Min=2,8V, Max=3,8V", Alternate_Manufacturer=EVERLIGHT, Alternate_Manufacturer_Part_Number=19-217-BHC-ZL1M2RY-3T-V4, Manufacturer="OSRAM OPTO SEMICONDUCTORS", Manufacturer_Part_Number="LB Q39G-L2OO-35-1", Package=0603
LD3 LD7 LD8: library part MCD-00587, "LED Red, 0603 SMD, 2V Forward Voltage", Alternate_Manufacturer="OSRAM OPTO SEMICONDUCTORS", Alternate_Manufacturer_Part_Number="LS Q976-NR-1", Manufacturer=VISHAY, Manufacturer_Part_Number=VLMS1300-GS08, Package=0603
LD4: library part MCD-02402, "LED Multicolor, Orange/Green/Blue/Yellow, 2V, 20mA, 4-PLCC", Manufacturer=EVERLIGHT, Manufacturer_Part_Number=67-22SURSYGC/S530-A2/TR8, Package=4-PLCC
LD5: library part MCD-00589, "LED Green, 0603 SMD, Fw Voltage = 2.8V - 3.6V", Alternate_Manufacturer="OSRAM OPTO SEMICONDUCTORS", Alternate_Manufacturer_Part_Number="LG Q396-PS-35", Manufacturer=VISHAY, Manufacturer_Part_Number=VLMTG1300-GS08, Package=0603
P1: library part MCD-00309, "Socket 10x2, 2.00mm, RA, TH, Height 6.35mm/2.29mm", Alternate_Manufacturer=JIUBABA, Alternate_Manufacturer_Part_Number=FH200020C-12300, Manufacturer=SAMTEC, Manufacturer_Part_Number=SQT-110-01-F-D-RA
Q1: library part MCD-01969, "Transistor, N-channel enhancement mode field-effect transistor", Alternate_Manufacturer=N/A, Manufacturer=NEXPERIA, Manufacturer_Part_Number=BSN20BK, Package=SOT23-3
R1: library part MCD-00062, "Resistor,330R,0402,1%,1/16W", Manufacturer=YAGEO, Manufacturer_Part_Number=RC0402FR-07330RL, Package=0402
R2 R3 R18 R19 R67 R71 R72 R88 R89 R100 R101 R103 R104: library part MCD-00056, "Resistor,0R,0603,5%,1/10W", Manufacturer=YAGEO, Manufacturer_Part_Number=RC0603JR-070RL, Package=0603
R4 R10: library part MCD-00508, "Resistor,680R,0603,1%,1/10W", Manufacturer=YAGEO, Manufacturer_Part_Number=RC0603FR-07680RL, Package=0603
R5 R6 R7 R8 R9 R83: library part MCD-00063, "Resistor,47K,0402,1%,1/16W", Manufacturer=YAGEO, Manufacturer_Part_Number=RC0402FR-0747KL, Package=0402
R11 R34 R43 R76 R87: library part MCD-00059, "Resistor,100K,0402,1%,1/16W", Alternate_Manufacturer=YAGEO, Alternate_Manufacturer_Part_Number=RT0402FRE07100KL, Manufacturer_Part_Number=RC0402FR-07100KL, Package=0402
R12 R13 R14 R45 R46 R47 R48 R49 R50 R52 R53 R54 R59 R60 R62 R63 R74 R78: library part MCD-00052, "Resistor,0R,0402,5%,1/16W", Manufacturer=YAGEO, Manufacturer_Part_Number=RC0402JR-070RL, Package=0402
R15 R20 R44 R51 R57 R58 R64 R65 R66 R69 R86 R95 R97 R105 R113: library part MCD-00053, "Resistor,10K,0402,1%,1/16W", Manufacturer=YAGEO, Manufacturer_Part_Number=RC0402FR-0710KL, Package=0402
R16 R17 R80: library part MCD-00197, "Resistor,330R,0603,1%,1/10W", Manufacturer=YAGEO, Manufacturer_Part_Number=RC0603FR-07330RL, Package=0603
R21: library part MCD-00194, "Resistor,120R,0402,1%,1/16W", Manufacturer=YAGEO, Manufacturer_Part_Number=RC0402FR-07120RL, Package=0402
R22 R28 R29 R30 R31 R32 R36 R37 R38 R39 R40 R41: library part MCD-00066, "Resistor,22R,0603,1%,1/10W", Manufacturer=YAGEO, Manufacturer_Part_Number=RC0603FR-0722RL, Package=0603
R23 R33 R42 R68 R70 R99: library part MCD-00067, "Resistor, 100R, 0402, +/- 1%, 1/16W", Manufacturer=YAGEO, Manufacturer_Part_Number=RC0402FR-07100RL, Package=0402
R24: library part MCD-00220, "Resistor,10K,0603,1%,1/10W", Manufacturer=YAGEO, Manufacturer_Part_Number=RC0603FR-0710KL, Package=0603
R25 R26: library part MCD-00485, "Resistor,51R,0402,1%,1/16W", Manufacturer=YAGEO, Manufacturer_Part_Number=RC0402FR-0751RL, Package=0402
R27 R35: library part MCD-00564, "Resistor,49R9,0603,1%,1/10W", Manufacturer=YAGEO, Manufacturer_Part_Number=RC0603FR-0749R9L, Package=0603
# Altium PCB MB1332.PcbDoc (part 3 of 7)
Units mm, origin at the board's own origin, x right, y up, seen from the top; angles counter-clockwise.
Board outline 161 x 75 mm, 6 copper layers (Top Layer, Signal Layer 1, Signal Layer 2, Signal Layer 3, Signal Layer 4, Bottom Layer), stack 1.57 mm thick; 387 components, 358 nets, 1659 pads, 1180 vias.

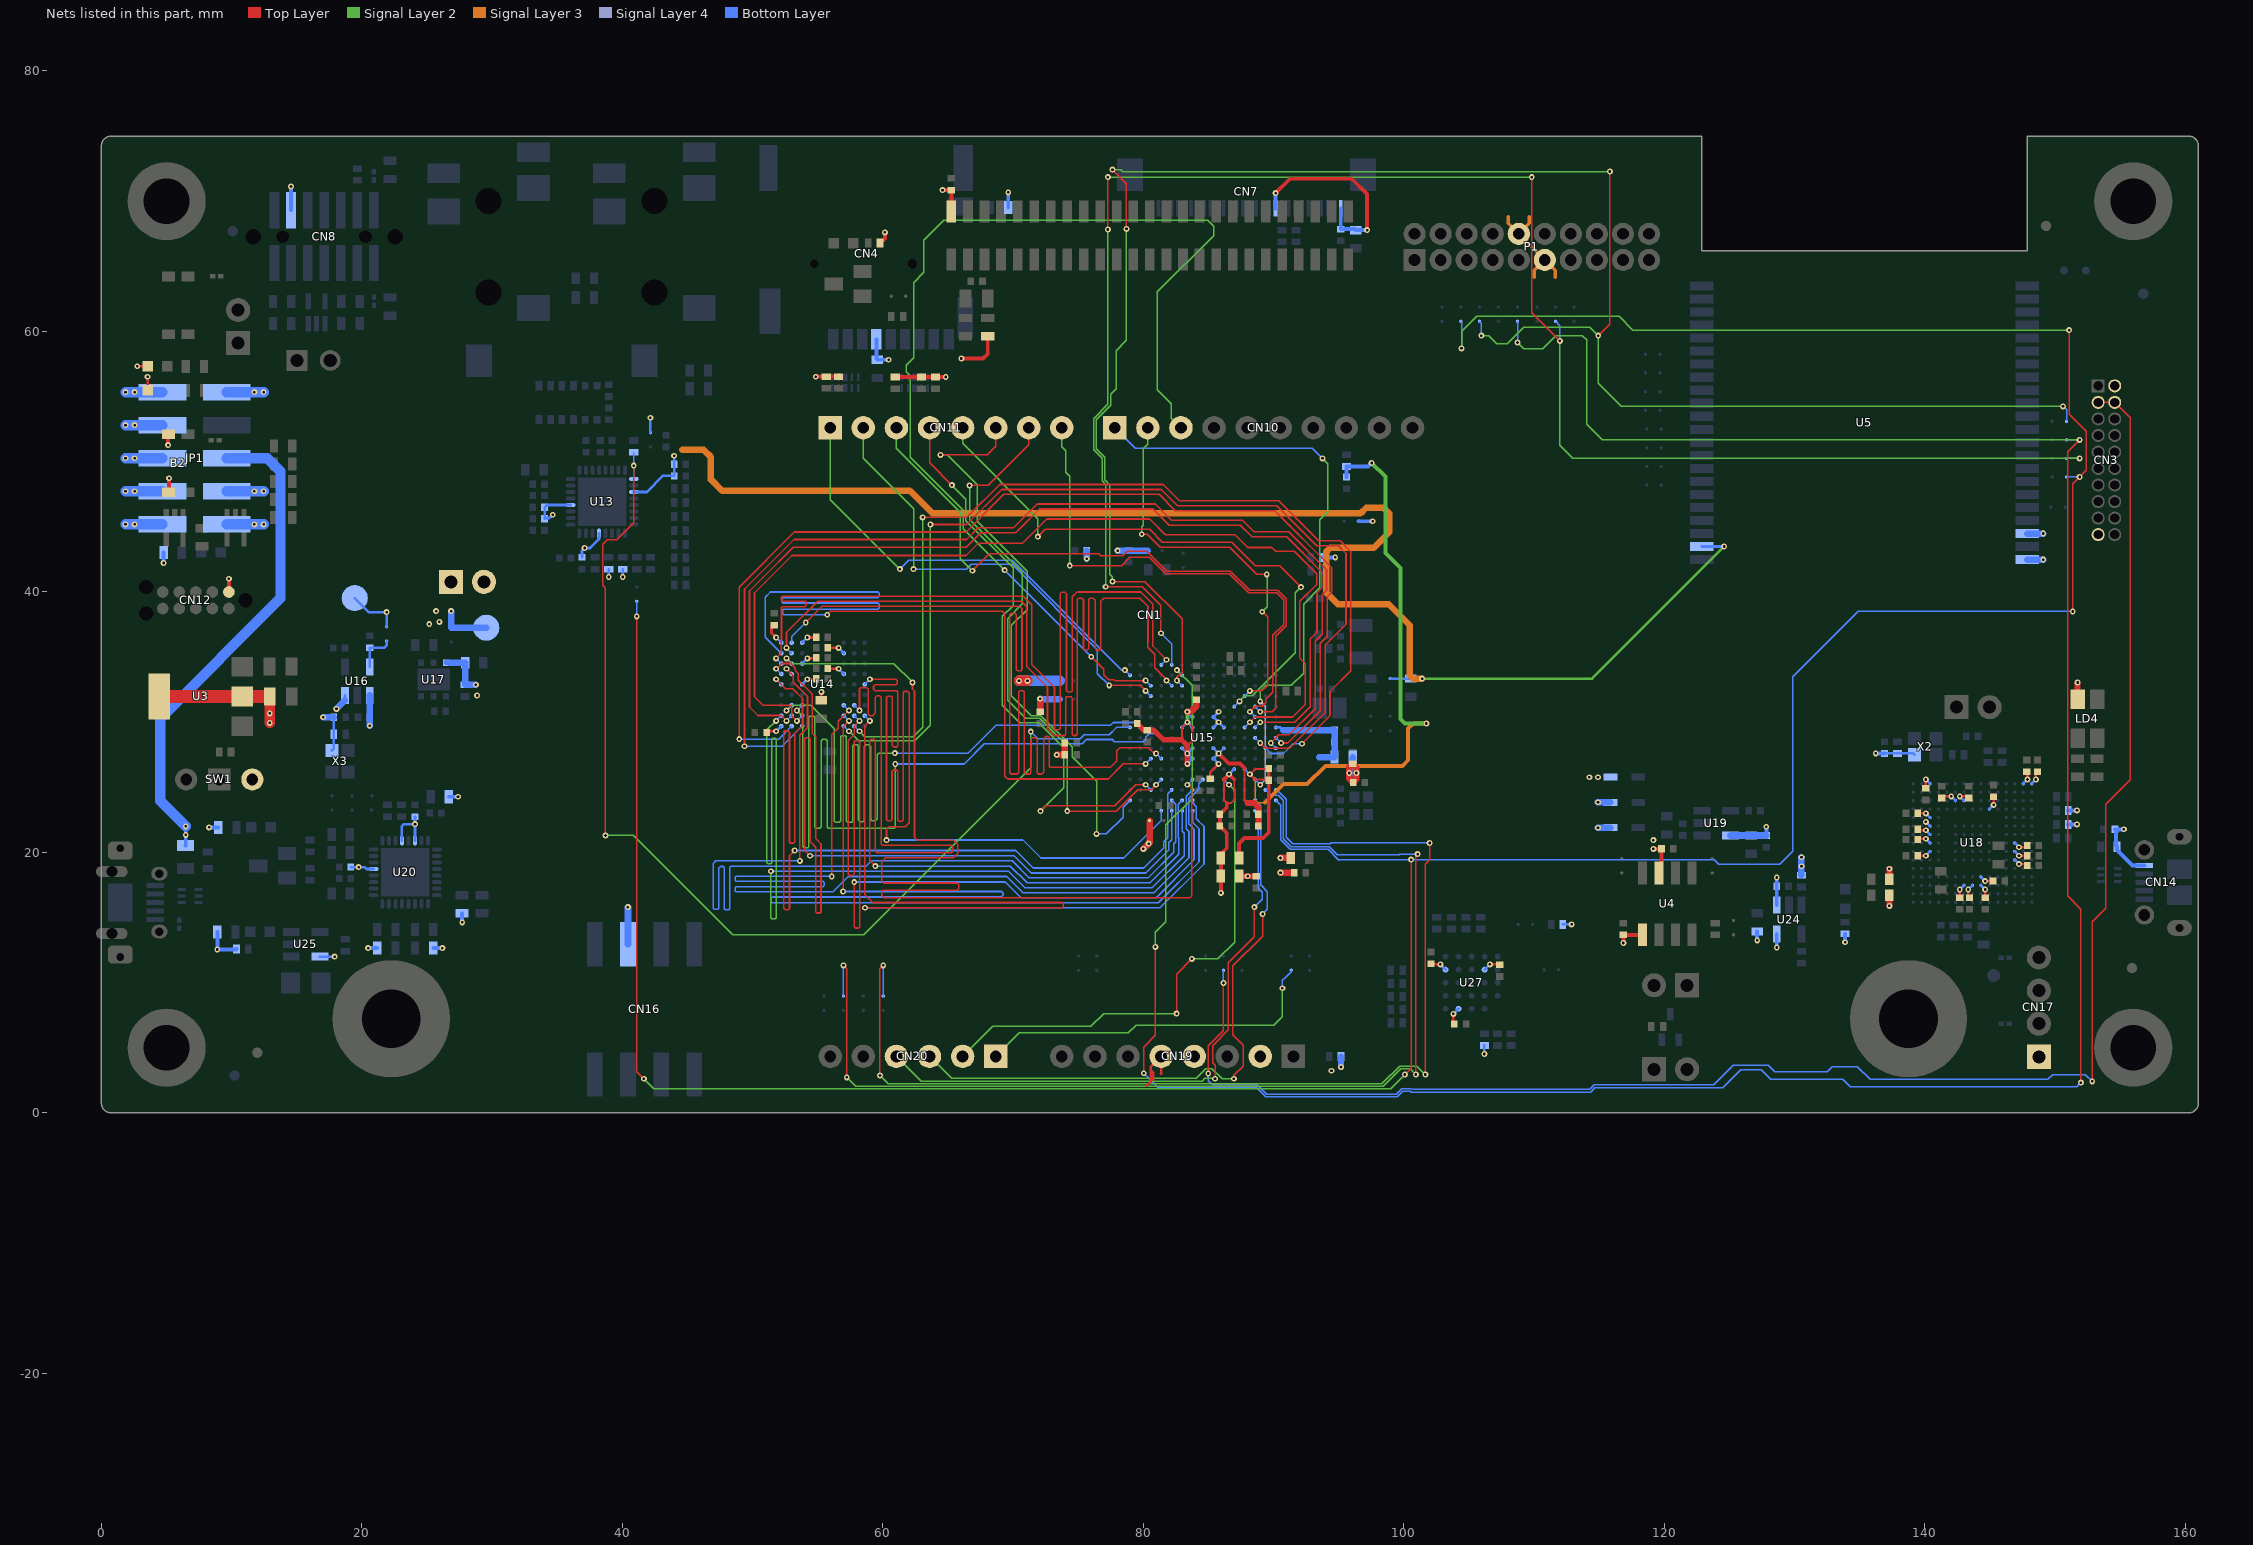
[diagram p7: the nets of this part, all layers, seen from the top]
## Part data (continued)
R55 R56: library part MCD-00068, "Resistor,1K5,0402,1%,1/16W", Manufacturer=YAGEO, Manufacturer_Part_Number=RC0402FR-071K5L, Package=0402
R61 R85: library part MCD-00528, "Resistor,820R,0603,1%,1/10W", Manufacturer=YAGEO, Manufacturer_Part_Number=RC0603FR-07820RL, Package=0603
R73 R75 R77 R82: library part MCD-00065, "Resistor,4K7,0402,1%,1/16W", Alternate_Manufacturer=YAGEO, Alternate_Manufacturer_Part_Number=RT0402FRE074K7L, Manufacturer_Part_Number=RC0402FR-074K7L, Package=0402
R79: library part MCD-00055, "Resistor,2K7,0402,1%,1/16W", Manufacturer=YAGEO, Manufacturer_Part_Number=RC0402FR-072K7L, Package=0402
R81: library part MCD-00570, "Resistor,8K06,0603,1%,1/10W", Manufacturer=YAGEO, Manufacturer_Part_Number=RC0603FR-078K06L, Package=0603
R84: library part MCD-00179, "Resistor,0R,0805,5%", Manufacturer=YAGEO, Manufacturer_Part_Number=RC0805JR-070RL, Package=0805
R90: library part MCD-00500, "Resistor,620R,0603,1%,1/10W", Manufacturer=YAGEO, Manufacturer_Part_Number=RC0603FR-07620RL, Package=0603
R91 R92 R93 R94 R106 R107 R108 R109 R110 R111 R112: library part MCD-00455, "Resistor,33R,0402,1%,1/16W", Manufacturer=YAGEO, Manufacturer_Part_Number=RC0402FR-0733RL, Package=0402
R96: library part MCD-00527, "Resistor,820R,0402,1%,1/16W", Manufacturer=YAGEO, Manufacturer_Part_Number=RC0402FR-07820RL, Package=0402
R98: library part MCD-00185, "Resistor,3K,0402,1%,1/16W", Manufacturer=YAGEO, Manufacturer_Part_Number=RC0402FR-073KL, Package=0402
R102: library part MCD-00184, "Resistor,3K3,0402,1%,1/16W", Manufacturer=YAGEO, Manufacturer_Part_Number=RC0402FR-073K3L, Package=0402
R114: library part MCD-00061, "Resistor,1K,0402,1%,1/16W", Manufacturer=YAGEO, Manufacturer_Part_Number=RC0402FR-071KL, Package=0402
R115: library part MCD-00182, "Resistor,1M,0402,1%,1/16W", Manufacturer=YAGEO, Manufacturer_Part_Number=RC0402FR-071ML, Package=0402
SB1 SB2 SB3 SB4 SB5 SB6 SB7 SB8 SB9 SB10 SB11 SB12 SB13 SB14 SB15 SB16 SB17 SB18 SB19 SB20 SB21 SB22 SB23 SB24 SB25 SB26 SB27 SB28 SB29 SB30 SB31 SB32 SB33 SB34 SB35 SB36 SB37 SB38 SB39 SB40 SB41 SB42 SB43 SB44 SB45 SB46 SB47 SB48 SB49 SB50 SB51 SB52 SB53 SB54 SB55: library part MCD-00071, "Solder Bridge ON", Manufacturer=YAGEO, Manufacturer_HQ_COO=Unknown, Manufacturer_Part_Number=RC0603JR-070RL, Package=0603
SW1: library part MCD-00566, "Mechanical Slide Switches 1K2 BLK ACT GOLD STRT MNT", Manufacturer=EAO, Manufacturer_Part_Number=09.03290.01, Package=2.5x10mm
T1: library part MCD-00073, "NPN Bipolar Transistor", Alternate_Manufacturer="ON SEMICONDUCTOR", Alternate_Manufacturer_Part_Number="MMBT2222ALT1G / MMBT2222ALT3G", Manufacturer_Part_Number=BSR14, Package=SOT23
TP1 TP2: library part MCD-00177, "Test Point 2mm", Manufacturer=n/a
TP3: library part MCD-00074, "Test Point 1mm", Manufacturer=n/a, Manufacturer_HQ_COO=Unknown
TP4 TP5: library part MCD-00631, "Test Point 0.6mm", Manufacturer=N/A
U1 U2 U6 U8 U26 U28 U30: library part MCD-00170, "ESD protection 6V1", Manufacturer=STMICROELECTRONICS, Manufacturer_HQ_COO=EU, Manufacturer_Part_Number=ESDALC6V1-1U2, Package=ST0201
U3: library part MCD-00088, "IC REG LDO 5V 0.8A SOT223", Manufacturer=STMICROELECTRONICS, Manufacturer_HQ_COO=EU, Package=SOT223-4
U4: library part MCD-00129, "High-Speed CAN Flexible Data Rate Transceiver", Manufacturer=MICROCHIP, Manufacturer_Part_Number=MCP2562FDT-H/SN, Package=SO-8
U5: library part MCD-01999, "44 pins Interposer for WIFI module (MB1486 module is with INVENTEK ISM43340-M4G-L44-10CF)", Manufacturer=STMICROELECTRONICS, Manufacturer_HQ_COO=EU, Manufacturer_Part_Number="MB1486 - WIFI MODULE WITH INVENTEK ISM43340-M4G-L44-10CF", Package=11.5x13.5mm
U7 U11 U12: library part MCD-00136, "Dual Transil array for ESD protection", Manufacturer=STMICROELECTRONICS, Manufacturer_HQ_COO=EU, Package=SOT323-5
U9 U10: library part MCD-00667, "4-line ESD protection for high speed lines", Manufacturer=STMICROELECTRONICS, Manufacturer_HQ_COO=EU, Package=uQFN-10
U13: library part MCD-00265, "Low-Power, Stereo Codec with Headphone Amp", Manufacturer="CIRRUS LOGIC", Package=QFN-32
U14: library part MCD-01143, "SDRAM 128Mbits - 166MHz - 54-ball BGA - x16 - 3.3V", Manufacturer=ISSI, Package=BGA-54
U15: library part MCD-01929, "MCU, ARM Cortex-M7 32-bit, 2MB Flash, 1.4MB RAM, With Crypto, SMPS", Manufacturer=STMICROELECTRONICS, Manufacturer_HQ_COO=EU, Manufacturer_Part_Number=STM32H7B3LIH6Q, Package=TFBGA-225
U16: library part MCD-00078, "Ultra low drop-low noise BiCMOS voltage, regulators low ESR capacitors compatible", Manufacturer=STMICROELECTRONICS, Manufacturer_HQ_COO=EU, Package=SOT23-5
U17: library part MCD-01025, "LDO, 3.3V, 1.3A, Very low quiescent current BiCMOS voltage regulator", Manufacturer=STMICROELECTRONICS, Manufacturer_HQ_COO=EU, Package=DFN-6
U18: library part MCD-00596, "STM32F723IEK  (STM32F7) BGA176", Manufacturer=STMICROELECTRONICS, Manufacturer_HQ_COO=EU, Manufacturer_Part_Number=STM32F723IEK6, Package=UFBGA-201
U19: library part MCD-00086, "Ultra low drop-low noise BiCMOS voltage, regulators low ESR capacitors compatible", Manufacturer=STMICROELECTRONICS, Manufacturer_HQ_COO=EU, Package=SOT23-5
U20: library part MCD-00569, "USB3320C,  Hi-Speed USB Host, Device or OTG PHY with ULPI Low Pin Interface", Manufacturer=MICROCHIP, Manufacturer_Part_Number=USB3320C-EZK-TR, Package=QFN-32
U22 U23: library part MCD-00649, "Common mode filter with ESD protection for USB 2.0 interface", Manufacturer=STMICROELECTRONICS, Manufacturer_HQ_COO=EU, Package=QFN-6
U24 U25: library part MCD-00159, "500mA, Enhanced single channel power switches with active high enable pin", Alternate_Manufacturer="TEXAS INSTRUMENTS", Alternate_Manufacturer_Part_Number=TPS2051C, Manufacturer=STMICROELECTRONICS, Manufacturer_HQ_COO=EU, Package=SOT23-5
U27: library part MCD-00246, "Memory,Octo-SPI-NOR,512Mb,2048x16,133MHz,3V,DTR,BGA24, CMOS MXSMIO", Manufacturer=MACRONIX, Package=BGA-24
U29: library part MCD-01062, "Automotive dual-line Transil, transient voltage suppressor (TVS) for CAN bus. Compliant with interfaces in automotive: CAN-FD, LIN, FlexRay, MOST, SENT, USB", Manufacturer=STMICROELECTRONICS, Manufacturer_HQ_COO=EU, Manufacturer_Part_Number=ESDCAN02-2BWY, Package=SOT323-3
X1: library part MCD-00091, "Crystal 32.768kHz, 6pF, +-20ppm, 50Kohms max, SMD", Manufacturer=NDK, Manufacturer_Part_Number=NX3215SA-32.768KHZ-EXS00A-MU00525, Package=3.2x1.5mm
X2: library part MCD-00597, "Oscillator 25Mhz, +-50ppm, Vcc:3.3V typ, square wave: [0.1Vcc;0.9Vcc], Enable pin, SMD", Alternate_Manufacturer=NDK, Alternate_Manufacturer_Part_Number="NZ2520SB 25MHz END4869B", Manufacturer_Part_Number=NZ2520SH-25MHZ-END4869C, Package=2.5x2mm
X3: library part MCD-01976, "Oscillator 24Mhz, +-50ppm, Vcc:3.3V typ, square wave: [0.1Vcc;0.9Vcc], Enable pin, SMD", Manufacturer=NDK, Manufacturer_Part_Number=NZ2520SH-24MHZ-END4869D, Package=2.5x2mm
X4: library part MCD-01036, "Crystal 24MHz, 6pF, +-20ppm, 80ohms max, SMD", Manufacturer=NDK, Manufacturer_Part_Number=NX2016SA-24MHZ-EXS00A-CS10820, Package=2x1.6mm

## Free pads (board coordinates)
  round 0.508 on Mech16: 1(51.098,-28.206) 1(99.946,-28.206)

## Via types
v1: diameter 0.45, hole 0.2, Top Layer to Bottom Layer, tented both sides, 1180 vias

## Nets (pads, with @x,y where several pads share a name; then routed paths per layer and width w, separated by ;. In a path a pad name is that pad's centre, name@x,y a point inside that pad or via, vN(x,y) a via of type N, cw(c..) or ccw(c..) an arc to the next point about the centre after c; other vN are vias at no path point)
1V8: C76.2 C78.2 C82.1 C83.2 C88.2 C97.2 C108.1 SB32.2 SB34.1 TP1.1 U5.2 U13.5 U13.12 U13.27 U20.28 U20.30 | length 131.2
  Signal Layer 2 w0.2: v1(101.4,33.348) 114.453,33.348 v1(124.59,43.485)
  Signal Layer 3 w0.5: 44.6,50.9 46.25,50.9 46.8,50.35 46.8,48.625 47.65,47.775 62.075,47.775 63.825,46.025 96.667,46.025 97.112,46.47 98.438,46.47 98.883,46.025 98.883,44.583 97.7,43.4 94.35,43.4 94.025,43.075 94.025,39.975 94.938,39.062 98.844,39.062 100.458,37.448 100.458,33.592 100.702,33.348 v1(101.4,33.348)
  Bottom Layer w0.2: TP1.1@19.45,39.525 20.525,38.45 v1(21.9,38.45) SB32.2@21.9,37.325 ; U20.28@23.075,20.9 23.075,22.025 23.225,22.175 v1(24.075,22.175) ; U20.30@24.075,20.9 C108.1@24.075,22.75 ; v1(34.65,45.925) 34.4,45.675 34.075,45.675 C83.2@34.025,45.625 C82.1@34.025,46.5 34.2,46.675 U13.12@36.025,46.675 ; C88.2@36.9,42.65 36.9,43.175 v1(37.1,43.375) 37.525,43.375 38.2,44.05 U13.5@38.2,44.5 ; U13.27@40.875,47.675 41.875,47.675 43.125,48.925 43.95,48.925 C78.2@43.975,48.9 C76.2@43.975,49.8 v1(43.975,50.45) ; SB34.1@98.95,33.348 C97.2@100.525,33.348 v1(101.4,33.348) ; U5.2@122.861,43.485 v1(124.59,43.485)
1V8_LDO: C92.2 SB32.1 U16.5 | length 3.2
  Bottom Layer w0.2: U16.5@20.6,34.25 C92.2@20.6,35.725 21.725,35.725 21.9,35.9 SB32.1@21.9,36.225
2_CTS: SB6.1 SB25.2 SB31.1 U15.P1 | length 268
  Top Layer w0.1: v1(41.1,38.125) 41.1,3.175 v1(41.65,2.625) ; v1(100.075,2.95) 100.55,3.425 v1(100.55,19.45) ; v1(151.075,60.1) 151.075,53.625 152.375,52.325 152.375,49.325 v1(151.875,48.825) 151.35,48.3 v1(151.35,38.5)
  Signal Layer 2 w0.1: v1(41.65,2.625) 42.425,1.85 98.973,1.85 100.073,2.95 v1(100.075,2.95) ; v1(104.425,58.7) 104.425,60 105.575,61.15 116.525,61.15 117.575,60.1 v1(151.075,60.1)
  Bottom Layer w0.1: v1(41.1,38.125) SB31.1@41.1,39.275 ; U15.P1@90.175,23.998 90.55,23.623 90.55,20.984 91.284,20.25 94.175,20.25 95.008,19.417 95.04,19.45 v1(100.55,19.45) 123.825,19.45 124.175,19.1 128.875,19.1 129.85,20.075 129.85,33.475 134.875,38.5 v1(151.35,38.5) ; SB6.1@104.375,60.775 104.425,60.725 v1(104.425,58.7) ; SB25.2@150.875,48.825 v1(151.875,48.825)
2_RTS: SB13.1 SB23.2 U15.A11 | length 139
  Top Layer w0.1: v1@77.1,40.378 77.122,40.4 79.926,40.4 81.35,38.976 v1(81.35,36.823) ; v1(77.275,67.825) v1(77.275,71.85) ; v1(109.82,71.85) 109.82,61.43 v1(111.975,59.275)
  Signal Layer 2 w0.1: v1(77.1,40.4) 77.1,48.242 76.825,48.517 76.825,50.25 76.175,50.9 76.175,53.3 77.275,54.4 v1(77.275,67.825) ; v1(77.275,71.85) v1(109.82,71.85) ; v1(111.975,59.275) 111.975,51.25 112.975,50.25 v1(151.875,50.25)
  Bottom Layer w0.1: SB13.1@111.65,60.775 111.975,60.45 v1(111.975,59.275) ; SB23.2@150.875,50.25 v1(151.875,50.25)
  Bottom Layer w0.127: v1(81.35,36.823) 82.175,35.998 U15.A11@82.175,34.398
2_RX: SB11.1 SB21.2 U15.B10 | length 211.5
  Top Layer w0.1: v1(80.025,3.05) 80.025,5.05 80.925,5.95 v1(80.925,12.75) ; v1(151.875,51.675) 150.95,50.75 150.95,16.675 151.975,15.65 v1(151.975,2.325)
  Signal Layer 2 w0.1: v1(80.925,12.75) 80.925,13.875 81.725,14.675 81.725,21.435 ; 81.723,21.435 81.723,22.107 83.75,24.134 83.75,32.823 v1(82.575,33.998) ; v1(108.725,59.15) 109.2,58.675 110.65,58.675 111.65,59.675 113.7,59.675 114.025,59.35 114.025,52.875 115.225,51.675 v1(151.875,51.675)
  Bottom Layer w0.1: v1(80.025,3.05) 81.15,1.925 88.701,1.925 89.376,1.25 99.499,1.25 99.924,1.675 100.471,1.675 100.546,1.6 114.341,1.6 114.666,1.925 124.492,1.925 125.867,3.3 127.433,3.3 128.158,2.575 133.708,2.575 134.283,2 151.65,2 v1(151.975,2.325) ; v1(82.575,33.998) U15.B10@82.975,33.598 ; v1(108.725,59.15) SB11.1@108.725,60.775 ; SB21.2@150.875,51.675 v1(151.875,51.675)
2_TX: SB9.1 SB18.2 U15.C10 | length 149.3
  Top Layer w0.1: v1(77.625,40.8) 80.098,40.8 82.975,37.923 82.975,33.848 82.575,33.448 v1(82.575,33.198) ; v1(77.625,72.425) 78.7,71.35 v1(78.7,67.875) ; v1(114.925,59.675) 115.82,60.57 v1(115.82,72.275)
  Signal Layer 2 w0.1: v1(77.625,40.8) 77.625,41.15 77.425,41.35 77.425,48.2 77.025,48.6 77.025,50.333 76.375,50.983 76.375,53.217 77.475,54.317 77.475,55.167 77.9,55.592 77.9,58.525 78.7,59.325 v1(78.7,67.875) ; v1(77.625,72.425) 78.25,72.425 78.4,72.275 v1(115.82,72.275) ; v1(105.95,59.675) 106.525,59.675 107.135,59.065 107.94,59.065 109.188,60.313 114.288,60.313 v1(114.925,59.675) 114.925,56.025 116.7,54.25 v1(150.6,54.25)
  Bottom Layer w0.1: v1(82.575,33.198) U15.C10@82.975,32.798 ; SB9.1@105.8,60.775 105.95,60.625 v1(105.95,59.675) ; v1(150.6,54.25) 150.875,53.975 SB18.2@150.875,53.1
3V3: B2.1 B2.2 C1.1 C4.1 C6.1 C7.1 C9.1 C11.1 C12.1 C14.2 C19.1 C59.1 C60.2 C61.2 C62.2 C63.2 C64.2 C66.1 C102.2 CN1.50 CN3.2 CN3.19 CN4.4 CN7.20 CN7.30 CN8.3 CN12.1 CN16.4 CN19.2 CN19.4 JP2.1 LD2.1 LD3.1 R1.2 R5.2 R6.2 R7.2 R8.2 R9.2 R24.2 R51.1 R55.2 R56.2 R65.1 R72.1 R77.2 R80.2 R89.2 R90.2 R97.2 R102.2 R103.2 R104.2 R113.1 SB20.1 SB33.2 SW1.2 TP2.1 U4.5 U5.44 U14.A7 U14.A9 U14.B3 U14.C7 U14.D3 U14.E7 U14.J9 U27.B4 U27.D1 U27.E4 X3.4 | length 74.3
  Top Layer w0.2: v1(2.75,57.325) LD2.1@3.55,57.325 ; LD3.1@3.55,55.475 v1(3.55,56.525) ; C19.1@51.075,29.2 51.175,29.3 v1(51.8,29.3) ; C4.1@51.65,37.45 51.45,37.25 51.45,36.85 v1(51.8,36.5) ; v1(54.2,33.3) 54.85,33.3 C12.1@54.875,33.325 ; v1(54.2,34.9) 54.825,34.9 C9.1@54.875,34.95 ; v1(54.2,36.5) 54.85,36.5 C6.1@54.875,36.525 ; C14.2@55.275,31.675 v1(55.275,32.325) ; C11.1@55.775,34.125 55.8,34.1 v1(56.6,34.1) ; C7.1@55.775,35.725 55.8,35.7 v1(56.6,35.7) ; C60.2@102.075,11.45 102.125,11.4 v1(102.8,11.4) ; v1(103.8,7.6) 103.8,6.8 C62.2@103.85,6.75 ; v1(106.6,11.4) 107.25,11.4 C61.2@107.275,11.425
  Top Layer w0.3: v1(5.125,51.275) 5.125,52.075 B2.2@5.15,52.1 ; B2.1@5.15,47.65 5.125,47.675 5.2,47.75 v1(5.2,48.725) ; CN12.1@9.79,39.995 v1(9.79,41.015) ; v1(54.85,56.525) R5.2@55.65,56.525 R6.2@56.6,56.525 ; R1.2@59.775,66.775 60.15,67.15 v1(60.15,67.6) ; R7.2@60.95,56.5 R8.2@62.95,56.5 R9.2@64.025,56.5 v1(64.825,56.5) ; v1(64.575,70.85) C1.1@65.25,70.85 65.26,70.84 CN1.50@65.26,69.217 ; v1(90.154,70.621) 91.258,71.725 96,71.725 97.175,70.55 v1(97.175,67.775) ; v1(116.85,13.05) C59.1@116.85,13.675 U4.5@118.32,13.675
  Bottom Layer w0.2: X3.4@17.7,27.825 17.85,27.975 R65.1@17.85,29.075 C102.2@17.85,30.375 ; v1(38.95,41.15) R56.2@38.95,41.75 ; v1(40.025,41.15) R55.2@40.025,41.75 ; SB20.1@42.15,52.225 v1(42.15,53.375) ; v1(51.8,29.3) U14.J9@52.2,29.7 ; v1(51.8,36.5) U14.A9@52.2,36.1 ; U14.E7@53.8,32.9 v1(54.2,33.3) ; U14.C7@53.8,34.5 v1(54.2,34.9) ; U14.A7@53.8,36.1 v1(54.2,36.5) ; v1(56.6,34.1) U14.D3@57,33.7 ; v1(56.6,35.7) U14.B3@57,35.3 ; v1(102.8,11.4) U27.E4@103.2,11 ; v1(103.8,7.6) U27.D1@104.2,8 ; v1(106.175,4.525) R113.1@106.175,5.175 ; U27.B4@106.2,11 v1(106.6,11.4) ; R97.2@112.2,14.475 v1(112.875,14.475)
  Bottom Layer w0.3: v1(8.275,21.925) R80.2@8.975,21.925 ; R90.2@8.9,13.9 v1(8.9,12.55) 10.325,12.55 R102.2@10.375,12.6 ; CN8.3@14.56,69.314 v1(14.56,71.125) ; v1(20.475,12.65) R104.2@21.175,12.65 ; R103.2@25.475,12.65 v1(26.175,12.65) ; R72.1@26.675,24.275 v1(27.375,24.275) ; v1(27.7,14.625) R89.2@27.7,15.325 ; CN4.4@59.5,59.4 59.5,57.9 C66.1@59.575,57.825 v1(60.439,57.825) ; R24.2@69.625,69.525 v1(69.625,70.675) ; v1@90.15,70.625 v1(90.154,70.621) CN7.20@90.154,69.45 ; R51.1@93.75,42.648 v1(94.725,42.648) ; CN7.30@95.154,69.45 95.154,67.854 C63.2@95.15,67.85 96.225,67.85 C64.2@96.3,67.775 v1(97.175,67.775) ; R77.2@151,23.225 v1(151.675,23.225)
  Bottom Layer w0.5: v1(17.025,30.375) C102.2@17.85,30.375 ; v1(26.85,38.525) SB33.2@26.85,37.25 TP2.1@29.55,37.25 ; v1(40.425,15.8) 40.43,15.795 CN16.4@40.43,12.95 ; U5.44@147.861,42.485 v1(149.09,42.485)
  other v1: 25.175,37.525 25.95,37.7 25.7,38.525
3V3_MCU: C13.1 C16.1 C17.1 C18.1 C20.1 C21.1 C22.1 C28.1 C30.1 C38.1 C40.1 C46.2 C51.1 C53.1 C85.1 C86.1 JP2.2 R19.1 R71.1 SB2.2 SB28.1 SB29.1 SB36.1 U15.F7 U15.F9 U15.G6 U15.G7 U15.G9 U15.G10 U15.J6 U15.J7 U15.J9 U15.J10 U15.K7 U15.K9 | length 52.7
  Top Layer w0.15: 83.15,28.423 82.975,28.598 82.975,29.598 v1(83.375,29.998) 83.775,29.598 83.775,28.598 83.375,28.198 ; 87.775,26.473 87.775,23.998 87.975,23.798
  Top Layer w0.2: C28.1@85.125,25.648 85.125,26.148 v1(85.775,26.798)
  Top Layer w0.3: v1(85.775,27.598) 86.55,26.823 87.425,26.823 87.775,26.473
  Top Layer w0.4: C17.1@79.525,29.898 80.05,29.373 C18.1@80.3,29.373 80.825,29.373 81.55,28.648 82.925,28.648 82.975,28.598 ; 83.15,28.423 83.375,28.198 v1(83.375,27.598) v1(83.375,26.798)
  Top Layer w0.45: R19.1@87.35,18.173 v1(88,18.173) C53.1@88.675,18.173 ; 87.975,23.798 88.5,23.798 88.825,23.473 C38.1@88.825,22.923 C40.1@88.825,22.023
  Top Layer w0.5: C16.1@72.075,30.798 v1(72.075,31.798) ; v1(73.35,27.498) C22.1@73.975,27.498 C20.1@73.975,28.398 ; v1(80,20.273) v1(80.4,20.673) 80.475,20.748 SB2.2@80.475,22.448 ; v1(83.375,30.798) 83.65,30.798 84.075,31.223 C13.1@84.075,31.723 ; v1(90.525,18.448) C51.1@91.575,18.448 ; v1(90.525,19.573) C46.2@91.325,19.573 ; 95.8,25.673 v1(95.8,26.098) 95.8,26.523 C21.1@96.075,26.798 96.35,26.523 v1(96.35,26.098) 96.35,25.623 C30.1@96.1,25.373 95.8,25.673
  Signal Layer 2 w0.15: v1(83.375,27.598) 83.375,28.148 82.975,28.548 82.975,29.598 v1(83.375,29.998)
  Signal Layer 2 w0.3: v1(83.375,26.798) v1(83.375,27.598) ; v1(83.375,29.998) v1(83.375,30.798)
  Bottom Layer w0.2: U15.J10@82.975,27.998 v1(83.375,27.598) ; U15.G10@82.975,29.598 v1(83.375,29.998) U15.G9@83.775,29.598 ; v1(83.375,26.798) U15.K9@83.775,27.198 v1(83.375,27.598) ; v1(83.375,30.798) U15.F9@83.775,30.398 ; U15.J9@83.775,27.998 v1(83.375,27.598) ; U15.J7@85.375,27.998 v1(85.775,27.598) ; U15.G7@85.375,29.598 v1(85.775,29.998) ; v1(85.775,26.798) U15.K7@85.375,27.198 v1(85.775,27.598) ; v1(85.775,30.798) U15.F7@85.375,30.398 v1(85.775,29.998) ; U15.J6@86.175,27.998 v1(85.775,27.598) ; U15.G6@86.175,29.598 v1(85.775,29.998)
  Bottom Layer w0.3: SB28.1@96.525,45.425 v1(97.6,45.425)
  Bottom Layer w0.5: v1(72.075,31.798) 72.1,31.773 SB36.1@73.575,31.773 ; v1(75.65,42.548) C85.1@75.65,43.173 ; v1(78.025,43.173) C86.1@78.875,43.173 SB29.1@80.35,43.173 ; v1(80,20.273) v1(80.4,20.673) ; R71.1@96.075,27.323 96.075,26.373 ; 96.075,26.373 v1(96.35,26.098) v1(95.8,26.098) 96.075,26.373
3V3_SMPS_IN: C103.2 C105.2 R71.2 SB39.2 U15.G1 | length 7.8
  Bottom Layer w0.2: U15.G1@90.175,29.598 90.5,29.598 90.725,29.373
  Bottom Layer w0.5: 90.725,29.373 C103.2@94.675,29.373 C105.2@94.675,28.473 R71.2@94.675,27.323 SB39.2@93.5,27.323
3V3_STLK: C24.1 C25.1 C31.1 C32.1 C33.1 C34.1 C36.1 C41.1 C42.1 C43.1 C47.1 C48.1 C49.1 C52.2 C54.1 C55.2 C56.1 C57.1 C58.1 C106.1 C115.2 C116.1 CN17.1 LD4.4 R66.1 U18.C1 U18.C5 U18.C6 U18.C7 U18.C8 U18.C9 U18.F3 U18.G3 U18.G13 U18.H13 U18.J12 U18.J13 U18.K4 U18.N8 U18.N9 U18.N10 U18.P1 U18.R1 U19.5 X2.4 | length 28.7
  Top Layer w0.1: C57.1@143.325,16.625 C57.1@143.425,16.525
  Top Layer w0.2: C47.1@139.45,19.75 v1(140.075,19.75) ; C42.1@139.45,21 139.5,21.05 v1(140.075,21.05) ; C41.1@139.45,21.775 139.525,21.7 v1(140.075,21.7) ; C36.1@139.45,23 v1(140.075,23) ; C34.1@140.075,24.925 v1(140.075,25.6) ; C32.1@141.3,24.175 141.425,24.3 v1(142.025,24.3) ; C56.1@142.675,16.525 v1(142.675,17.15) ; v1(142.675,24.3) 143.25,24.3 C33.1@143.375,24.175 ; C57.1@143.325,16.625 v1(143.325,17.15) ; C58.1@144.625,16.525 v1(144.625,17.15) ; v1(144.625,17.8) C54.1@145.225,17.8 ; v1(145.275,23.65) C31.1@145.275,24.275 ; v1(147.225,19.1) 147.75,19.1 C49.1@147.85,19 ; v1(147.225,19.75) C48.1@147.85,19.75 ; v1(147.225,20.4) 147.725,20.4 C43.1@147.85,20.525 ; C24.1@147.825,26.2 147.875,26.15 v1(147.875,25.6) ; v1(148.525,25.6) 148.525,26.075 C25.1@148.65,26.2
  Top Layer w0.45: v1(137.275,15.9) C55.2@137.275,16.7 ; C52.2@137.275,17.95 v1(137.275,18.75) ; LD4.4@151.725,31.775 v1(151.725,33.05)
  Bottom Layer w0.2: C106.1@136.9,27.6 R66.1@137.9,27.6 139.1,27.6 X2.4@139.2,27.5 ; v1(140.075,19.75) U18.C9@140.4,20.075 ; v1(140.075,21.05) U18.C8@140.4,20.725 ; v1(140.075,21.7) U18.C7@140.4,21.375 ; v1(140.075,22.35) U18.C6@140.4,22.025 ; v1(140.075,23) U18.C5@140.4,22.675 ; v1(140.075,25.6) U18.C1@140.4,25.275 ; v1(142.025,24.3) U18.F3@142.35,23.975 ; v1(142.675,17.15) U18.G13@143,17.475 ; v1(142.675,24.3) U18.G3@143,23.975 ; v1(143.325,17.15) U18.H13@143.65,17.475 ; U18.J13@144.3,17.475 v1(144.625,17.15) ; U18.J12@144.3,18.125 v1(144.625,17.8) ; U18.K4@144.95,23.325 v1(145.275,23.65) ; U18.N10@146.9,19.425 v1(147.225,19.1) ; U18.N9@146.9,20.075 v1(147.225,19.75) ; U18.N8@146.9,20.725 v1(147.225,20.4) ; U18.P1@147.55,25.275 v1(147.875,25.6) ; U18.R1@148.2,25.275 v1(148.525,25.6)
  Bottom Layer w0.3: C116.1@127.825,21.3 v1(127.825,21.975) ; v1(136.225,27.6) C106.1@136.9,27.6
  Bottom Layer w0.5: U19.5@125.075,21.3 C115.2@126.675,21.3 C116.1@127.825,21.3
3V3_VDDA: C37.2 C39.1 R18.1 R19.2 U15.L5 | length 13.5
  Top Layer w0.15: 86.175,25.598 86.175,24.023 86.4,23.798 86.75,23.798 86.975,24.023 86.975,25.598
  Top Layer w0.3: R18.1@85.875,19.648 R18.1@85.95,19.573 ; v1(85.95,16.898) R19.2@85.95,18.173 R18.1@85.95,19.573 ; 86.175,25.598 v1(86.575,25.998) 86.975,25.598 ; 86.4,23.798 86.4,23.448 C37.2@85.875,22.923 C39.1@85.875,22.023 86.4,21.498 86.4,20.323 85.95,19.873 R18.1@85.95,19.573
  Bottom Layer w0.2: v1(86.575,25.998) U15.L5@86.975,26.398
3V3_VREFP: C26.2 C29.2 C79.1 R18.2 R45.2 U15.L4 | length 57.4
  Top Layer w0.15: C26.2@89.6,26.398 88.575,26.398 v1(88.175,25.998) 88.575,25.598 89.575,25.598 C29.2@89.625,25.548 ; C26.2@89.6,26.423 C26.2@89.625,26.448
  Top Layer w0.3: R18.2@87.35,19.573 87.35,20.698 87.75,21.098 89.2,21.098 89.625,21.523 C29.2@89.625,25.548 C26.2@89.625,26.448
  Signal Layer 2 w0.3: v1(97.525,49.9) 98.575,48.85 98.575,43 99.725,41.85 99.725,30.25 100.075,29.9 v1(101.725,29.9)
  Signal Layer 3 w0.1: v1(88.175,25.998) 88.575,25.598 88.575,24 88.75,23.825 89.325,23.825
  Signal Layer 3 w0.3: 89.325,23.825 90.75,25.25 92.575,25.25 93.975,26.65 99.9,26.65 100.325,27.075 100.325,29.5 100.725,29.9 v1(101.725,29.9)
  Bottom Layer w0.1: U15.L4@87.775,26.398 v1(88.175,25.998)
  Bottom Layer w0.3: C79.1@95.6,48.825 R45.2@95.6,49.625 97.25,49.625 v1(97.525,49.9)
5V: C45.1 C96.2 C101.2 C117.1 CN19.5 JP1.2 JP1.4 JP1.6 JP1.8 JP1.10 P1.6 P1.15 R3.1 R61.1 R64.1 R79.1 SB35.1 U4.3 U5.42 U16.1 U16.3 U17.6 U20.21 U25.5 | length 52.9
  Top Layer w0.2: 80.25,2.1 80.575,2.425 80.575,3.275 ; 80.725,2.55 80.756,2.581 80.756,3.094 80.575,3.275 ; 81.35,3 81.36,3.01 CN19.5@81.36,4.34 80.575,3.555 80.575,3.275
  Top Layer w0.3: v1(66.025,57.925) 67.7,57.925 68.05,58.275 R3.1@68.05,59.625 ; v1(119.15,20.275) C45.1@119.775,20.275 119.775,18.61 U4.3@119.59,18.425
  Top Layer w0.8: v1(70.45,33.173) v1(71.1,33.173)
  Signal Layer 2 w0.8: v1(70.45,33.173) v1(71.1,33.173)
  Signal Layer 3 w0.25: 108.015,68.83 108.015,68.295 P1.15@108.82,67.49 ; 109.625,68.83 109.625,68.295 P1.15@108.82,67.49 ; 110.015,64.15 110.015,64.685 P1.6@110.82,65.49 ; 111.625,64.15 111.625,64.685 P1.6@110.82,65.49 ; P1.15@108.82,67.49 P1.6@110.82,65.49
  Signal Layer 4 w0.8: v1(70.45,33.173) v1(71.1,33.173)
  Bottom Layer w0.2: U25.5@16.775,12 v1(17.908,12) ; U16.3@18.7,31.675 U16.3@18.7,32.05 ; C117.1@19.15,18.875 v1(19.75,18.875) 20.2,18.875 20.35,18.725 U20.21@20.9,18.725
  Bottom Layer w0.3: v1(4.775,42.225) R61.1@4.775,43.025 ; R79.1@151,22.15 v1(151.675,22.15)
  Bottom Layer w0.4: U17.6@26.45,34.575 26.7,34.575
  Bottom Layer w0.5: v1(18.05,31.025) U16.3@18.7,31.675 ; v1(20.6,29.725) C101.2@20.6,30.375 U16.1@20.6,32.05 ; 26.7,34.575 C96.2@27.925,34.575 R64.1@27.925,32.875 v1(28.75,32.875) ; U5.42@147.861,44.485 v1(149.09,44.485)
  Bottom Layer w0.8: v1(1.85,45.185) v1(2.55,45.185) JP1.10@4.675,45.185 ; v1(1.85,47.725) v1(2.55,47.725) JP1.8@4.675,47.725 ; v1(1.85,50.265) v1(2.55,50.265) JP1.6@4.675,50.265 ; v1(1.85,52.805) v1(2.55,52.805) JP1.4@4.675,52.805 ; v1(1.85,55.345) v1(2.55,55.345) JP1.2@4.675,55.345 ; v1(70.45,33.173) v1(71.1,33.173) SB35.1@73.575,33.173
  other v1: 119.15,20.95 28.85,32.05
5V_USB_CHARGER: C114.2 C121.2 CN14.1 D2.1 D4.1 JP1.9 R87.1 R96.2 U24.5 | length 12.5
  Bottom Layer w0.3: v1(127.125,13.25) C121.2@127.125,13.925 ; v1(128.625,12.7) U24.5@128.625,13.75 ; v1(133.875,13.1) R96.2@133.875,13.75 ; v1(155.275,21.775) C114.2@154.6,21.775 154.675,21.7 154.675,20.525 D4.1@154.75,20.45 154.75,20.175 155.925,19 CN14.1@156.85,19
  Bottom Layer w0.5: v1(114.9,23.85) D2.1@115.86,23.85 ; R87.1@130.525,18.25 v1(130.525,18.938) v1(130.525,19.625)
  Bottom Layer w0.8: JP1.9@9.625,45.185 v1(11.75,45.185) v1(12.45,45.185)
5V_USB_HS: D3.1 JP1.5 R84.2 | length 38.9
  Bottom Layer w0.3: R84.2@6.45,20.525 6.475,20.55 v1(6.475,21.35) v1(6.475,22)
  Bottom Layer w0.5: v1(114.9,21.9) D3.1@115.86,21.9
  Bottom Layer w0.8: v1(6.475,22) 4.525,23.95 4.525,30.275 13.75,39.5 13.75,49.25 12.735,50.265 JP1.5@9.625,50.265
5V_USB_STLK: C119.1 JP1.1 U24.1 | length 5
  Bottom Layer w0.3: U24.1@128.625,15.95 C119.1@128.625,17.4 v1(128.625,18.075)
  Bottom Layer w0.8: JP1.1@9.625,55.345 v1(11.75,55.345) v1(12.45,55.345)
5V_VIN: C8.2 D1.1 JP1.7 R114.2 U3.2 U3.4 | length 14.1
  Top Layer w0.8: C8.2@12.549,31.972 C8.2@12.924,31.972 v1(12.924,30.672) v1(12.924,29.947)
  Top Layer w1: U3.4@4.449,31.972 U3.2@10.799,31.972 C8.2@12.549,31.972
  Bottom Layer w0.45: v1(95.175,3.525) R114.2@95.175,4.325
  Bottom Layer w0.8: JP1.7@9.625,47.725 v1(11.75,47.725) v1(12.45,47.725)
  other v1: 94.444,3.244 114.244,25.775 114.9,25.775
A0: U14.H7 U15.G4 | length 76.3
  Top Layer w0.127: v1(53.4,30.1) 53,30.5 53.011,30.511 53.011,31.139 52.85,31.3 50.788,31.3 50.138,31.95 50.138,39.916 50.947,40.724 53.022,42.8 66.375,42.8 67.3,43.725 70.7,43.725 72.575,45.6 80.48,45.6 81.689,44.391 87.034,44.391 88.009,43.416 89.865,43.416 90.158,43.123 91.575,43.123 93.3,41.398 93.3,40.575 92,39.275 92,34.925 92.425,34.5 92.425,31.354 91.47,30.398 88.575,30.398 v1(88.175,29.998)
  Bottom Layer w0.127: v1(53.4,30.1) U14.H7@53.8,30.5 ; U15.G4@87.775,29.598 v1(88.175,29.998)
A1: U14.H8 U15.G3 | length 76.9
  Top Layer w0.127: v1(52.6,30.1) 52.189,30.511 50.414,30.511 49.757,31.168 49.757,40.073 50.789,41.105 53.109,43.425 66.4,43.425 67.519,44.544 70.183,44.544 70.537,44.899 70.549,44.899 72.022,46.372 80.748,46.372 81.994,45.126 87.447,45.126 88.336,44.237 91,44.237 93.681,41.556 93.681,40.29 93.325,39.935 93.325,36.898 92.806,36.379 92.806,31.196 91.609,29.998 v1(88.975,29.998)
  Bottom Layer w0.127: v1(52.6,30.1) U14.H8@53,30.5 ; U15.G3@88.575,29.598 v1(88.975,29.998)
A2: U14.J8 U15.H1 | length 82.8
  Top Layer w0.127: v1(48.975,28.7) 48.975,40.369 53.206,44.6 66.4,44.6 69.288,47.488 81.21,47.488 82.456,46.242 90.073,46.242 94.443,41.872 94.443,39.975 94.106,39.638 94.106,36.602 93.568,36.064 93.568,30.88 91.086,28.398 v1(90.575,28.398)
  Bottom Layer w0.127: v1(48.975,28.7) 52,28.7 U14.J8@53,29.7 ; U15.H1@90.175,28.798 v1(90.575,28.398)
A3: U14.J7 U15.J1 | length 82.7
  Top Layer w0.127: v1(49.375,28.15) 49.375,40.23 53.17,44.025 66.425,44.025 67.325,44.925 70.025,44.925 71.853,46.753 80.905,46.753 82.152,45.507 87.605,45.507 88.494,44.618 91.158,44.618 94.062,41.714 94.062,40.133 93.725,39.796 93.725,36.76 93.187,36.221 93.187,31.038 91.172,29.023 90.4,29.023 v1(89.775,28.398)
  Bottom Layer w0.127: v1(49.375,28.15) 52.25,28.15 U14.J7@53.8,29.7 ; v1(89.775,28.398) U15.J1@90.175,27.998
A4: U14.J3 U15.H3 | length 77.8
  Top Layer w0.127: v1(63.65,45.175) 66.425,45.175 69.119,47.869 81.368,47.869 82.614,46.623 90.231,46.623 93.304,43.55 94.95,43.55 95.55,42.95 95.55,37.507 93.949,35.906 93.949,30.722 91.213,27.987 89.386,27.987 v1(88.975,28.398)
  Signal Layer 2 w0.102: v1(57.4,29.3) 58.131,28.569 62.452,28.569 63.65,29.767 v1(63.65,45.175)
  Bottom Layer w0.127: U14.J3@57,29.7 v1(57.4,29.3) ; U15.H3@88.575,28.798 v1(88.975,28.398)
A5: U14.J2 U15.J2 | length 77.7
  Top Layer w0.127: v1(63.05,45.725) 66.436,45.725 68.961,48.25 81.525,48.25 82.772,47.004 90.389,47.004 93.461,43.931 95.108,43.931 95.931,43.108 95.931,33.954 94.33,32.353 94.33,30.503 v1(92.175,28.348)
  Signal Layer 2 w0.102: v1(58.2,29.3) 58.625,28.875 62.325,28.875 63.05,29.6 v1(63.05,45.725)
  Bottom Layer w0.127: U14.J2@57.8,29.7 v1(58.2,29.3) ; U15.J2@89.375,27.998 89.775,27.598 90.75,27.598 91.5,28.348 v1(92.175,28.348)
A6: U14.H3 U15.R9 | length 82.9
  Top Layer w0.127: v1(56.95,17) 56.95,29.6 56.975,29.625 56.95,29.65 v1(57.4,30.1)
  Bottom Layer w0.127: v1(56.95,17) 69.125,17 69.25,16.875 69.25,16.75 69.075,16.575 51.5,16.575 51.4,16.475 51.4,16.2 51.462,16.138 81.136,16.138 84.268,19.271 84.268,21.823 83.775,22.317 U15.R9@83.775,23.198 ; U14.H3@57,30.5 v1(57.4,30.1)
A7: U14.H2 U15.M8 | length 76.7
  Top Layer w0.127: v1(57.8,17.725) 57.8,14.3 57.9,14.2 58.15,14.2 58.23,14.28 58.23,28.47 58.125,28.575 57.875,28.575 57.8,28.5 57.8,18.35 57.675,18.225 57.425,18.225 57.339,18.311 57.339,28.589 57.8,29.05 57.8,29.7 v1(58.2,30.1)
  Bottom Layer w0.1: 83.775,21.898 83.475,22.198 83.475,24.123 83.651,24.298 83.709,24.298 84.25,24.839 84.25,25.273 U15.M8@84.575,25.598
  Bottom Layer w0.127: v1(57.8,17.725) 69.392,17.725 70.598,16.519 80.978,16.519 83.887,19.429 83.887,21.786 83.775,21.898 ; U14.H2@57.8,30.5 v1(58.2,30.1)
A8: U14.H1 U15.P9 | length 77.8
  Top Layer w0.127: v1(58.625,15.75) 58.611,15.764 73.764,15.764 73.85,15.85 73.85,16.075 73.775,16.15 59.225,16.15 58.611,16.764 58.611,29.689 58.6,29.7 v1(59,30.1)
  Bottom Layer w0.1: U15.P9@83.775,23.998 83.775,23.808 84.075,23.508 84.075,22.573 84.275,22.373
  Bottom Layer w0.127: U14.H1@58.6,30.5 v1(59,30.1) ; v1(58.625,15.75) 58.634,15.741 81.277,15.741 84.649,19.113 84.649,21.999 84.275,22.373
A9: U14.G3 U15.N9 | length 78.3
  Top Layer w0.127: v1(56.075,18.15) 56.075,29.05 56.569,29.544 56.569,30.069 v1(57.4,30.9)
  Bottom Layer w0.1: 83.506,21.592 83.275,21.823 83.275,24.298 U15.N9@83.775,24.798
  Bottom Layer w0.127: v1@56.05,18.15 56.038,18.162 48.75,18.162 48.675,18.087 48.675,17.85 48.75,17.775 55.4,17.775 55.5,17.675 55.5,17.475 55.4,17.375 48.75,17.375 48.675,17.3 48.675,17.025 48.725,16.975 56.175,16.975 57.35,18.15 69.506,18.15 70.755,16.9 80.82,16.9 83.506,19.587 83.506,21.592 ; U14.G3@57,31.3 v1(57.4,30.9)
A10: U14.H9 U15.R10 | length 76.6
  Signal Layer 2 w0.102: v1(51.4,18.55) 51.4,14.975 51.475,14.9 51.725,14.9 51.824,14.999 51.824,16.374 51.825,16.375 51.825,28.675 51.75,28.75 51.55,28.75 51.475,28.675 51.475,19.225 51.375,19.125 51.2,19.125 51.101,19.224 51.101,29.401 v1(51.8,30.1)
  Bottom Layer w0.127: v1(51.4,18.55) 69.645,18.55 70.913,17.281 80.662,17.281 83.125,19.745 83.125,21.473 82.975,21.624 U15.R10@82.975,23.198 ; v1(51.8,30.1) U14.H9@52.2,30.5
A11: U14.G2 U15.P10 | length 78.4
  Top Layer w0.127: v1(58.2,30.9) 58.2,32.55 58.3,32.65 58.775,32.65 58.875,32.55 58.875,30.625 59,30.5 59.225,30.5 59.4,30.675 59.4,31.875 59.55,32.025 59.736,32.025 59.875,31.886 59.875,20.65 59.975,20.55 65.261,20.55 65.356,20.456 65.356,20.081 65.25,19.975 59.575,19.975 59.425,20.125 59.425,28.6 59.325,28.7 59.1,28.7 58.992,28.592 58.992,19.383 v1(59.425,18.95)
  Bottom Layer w0.1: 82.706,21.144 82.675,21.175 82.675,23.698 U15.P10@82.975,23.998
  Bottom Layer w0.127: U14.G2@57.8,31.3 v1(58.2,30.9) ; v1(59.425,18.95) 69.784,18.95 71.071,17.662 80.504,17.662 82.706,19.864 82.706,21.144
A14: U14.G7 U15.H12 | length 76.8
  Signal Layer 2 w0.102: v1(53.4,30.9) 53.837,30.462 53.837,20.488 53.95,20.375 54.25,20.375 54.325,20.45 54.325,30.375 54.4,30.45 54.7,30.45 54.775,30.375 54.775,21.95 54.85,21.875 55.15,21.875 55.25,21.975 55.25,28.575 55.375,28.7 55.6,28.7 55.712,28.588 55.712,21.963 55.8,21.875 60.875,21.875 60.95,21.95 v1(60.95,26.788)
  Bottom Layer w0.1: 77.6,28.673 77.775,28.498 79.992,28.498 80.2,28.706 80.2,28.848 80.45,29.098 81.075,29.098 U15.H12@81.375,28.798
  Bottom Layer w0.127: v1(53.4,30.9) U14.G7@53.8,31.3 ; v1(60.95,26.788) 66.241,26.788 67.793,28.341 75.298,28.341 75.623,28.666 77.592,28.666 77.6,28.673
A15: U14.G8 U15.G14 | length 78.1
  Signal Layer 2 w0.102: v1(52.6,30.9) 53,31.3 54.475,31.3 56.275,29.5 56.275,22.4 56.375,22.3 56.65,22.3 56.775,22.425 56.775,28.9 56.825,28.95 57.1,28.95 57.175,28.875 57.175,22.45 57.3,22.325 57.6,22.325 57.675,22.4 57.675,28.175 57.763,28.263 58.037,28.263 58.1,28.2 58.1,22.5 58.25,22.35 58.45,22.35 58.55,22.45 58.55,28.1 58.7,28.25 58.925,28.25 59.05,28.125 59.05,22.525 59.15,22.425 59.4,22.425 59.55,22.575 59.55,27.5 59.675,27.625 v1(60.925,27.625)
  Bottom Layer w0.127: v1(52.6,30.9) U14.G8@53,31.3 ; v1(60.925,27.625) 66.539,27.625 68.687,29.773 77.475,29.773 77.681,29.979 79.394,29.979 U15.G14@79.775,29.598
ARD_A0: CN20.1 SB45.2 | length 27.1
  Signal Layer 2 w0.1: CN20.1@68.66,4.34 70.47,6.15 78.85,6.15 79.45,6.75 90.025,6.75 90.675,7.4 v1(90.675,9.575)
  Bottom Layer w0.1: v1(90.675,9.575) 90.675,10.175 90.85,10.35 91.35,10.85 SB45.2@91.35,10.95
ARD_A1: CN20.2 U15.M6 | length 39.1
  Top Layer w0.1: v1(82.55,7.625) 82.55,10.65 v1(83.725,11.825)
  Signal Layer 2 w0.1: CN20.2@66.12,4.34 68.43,6.65 75.975,6.65 76.95,7.625 v1(82.55,7.625) ; v1(83.725,11.825) 85.719,11.825 87,13.106 87,24.773 v1(86.575,25.198)
  Bottom Layer w0.1: U15.M6@86.175,25.598 v1(86.575,25.198)
ARD_A2: CN20.3 U15.P3 | length 48.2
  Top Layer w0.1: v1(86.95,2.625) 86.95,2.875 87.675,3.6 87.675,5.2 86.875,6 86.875,11.3 89.15,13.575 v1(89.15,15.275)
  Signal Layer 2 w0.1: CN20.3@63.58,4.34 65.27,2.65 84.05,2.65 84.8,3.4 85.267,3.4 86.042,2.625 v1(86.95,2.625)
  Bottom Layer w0.1: U15.P3@88.575,23.998 89.007,23.566 89.007,17.518 89.525,17 89.525,15.65 v1(89.15,15.275)
ARD_A3: CN20.4 U15.R3 | length 47.8
  Top Layer w0.1: v1(85.5,2.625) 85.5,3.675 85.325,3.85 85.325,5.175 86.525,6.375 86.525,11.525 88.525,13.525 v1(88.525,15.8)
  Signal Layer 2 w0.1: CN20.4@61.04,4.34 62.93,2.45 84.525,2.45 84.725,2.65 85.475,2.65 v1(85.5,2.625)
  Bottom Layer w0.1: v1(88.525,15.8) 89.125,16.4 89.125,16.925 88.807,17.243 88.807,22.966 U15.R3@88.575,23.198
ARD_A4: SB52.1 U15.N1 | length 87
  Top Layer w0.1: v1(59.775,2.875) 59.775,11.075 v1(60.025,11.325) ; v1(101.65,2.95) 101.65,11.123 101.645,11.128 101.645,19.095 101.975,19.425 v1(101.975,20.725)
  Signal Layer 2 w0.1: v1(59.775,2.875) 60.4,2.25 98.317,2.25 99.667,3.6 101,3.6 v1(101.65,2.95)
  Bottom Layer w0.1: SB52.1@60.025,8.975 v1(60.025,11.325) ; U15.N1@90.175,24.798 90.233,24.798 90.95,24.081 90.95,21.15 91.45,20.65 94.35,20.65 94.425,20.725 v1(101.975,20.725)
ARD_A5: SB54.1 U15.N2 | length 88.2
  Top Layer w0.1: v1(56.975,11.325) 57.225,11.075 v1(57.225,2.725) ; v1(100.925,2.95) 100.925,19.75 v1(101.05,19.875)
  Signal Layer 2 w0.1: v1(57.225,2.725) 57.9,2.05 98.4,2.05 99.75,3.4 100.475,3.4 v1(100.925,2.95)
  Bottom Layer w0.1: SB54.1@56.975,8.975 v1(56.975,11.325) ; U15.N2@89.375,24.798 89.775,24.398 90.35,24.398 90.75,23.998 90.75,21.067 91.367,20.45 94.258,20.45 94.883,19.825 99.65,19.825 99.7,19.875 v1(101.05,19.875)
ARD_D0: CN11.1 U15.B15 | length 34.7
  Signal Layer 2 w0.1: CN11.1@55.96,52.6 55.96,47.09 v1(61.3,41.75)
  Bottom Layer w0.1: v1(61.3,41.75) 61.975,42.425 69.925,42.425 78.352,33.998 v1(78.575,33.998) U15.B15@78.975,33.598
ARD_D1: CN11.2 U15.D13 | length 36.1
  Top Layer w0.1: v1(77.375,32.825) 79.748,32.825 v1(80.175,32.398)
  Signal Layer 2 w0.1: CN11.2@58.5,52.6 58.5,50.25 62.35,46.4 v1(62.35,41.75)
  Bottom Layer w0.1: v1(62.35,41.75) 66.4,41.75 66.775,42.125 69.925,42.125 76.475,35.575 76.475,33.725 v1(77.375,32.825) ; v1(80.175,32.398) U15.D13@80.575,31.998
ARD_D2: CN11.3 U15.E3 | length 50.3
  Top Layer w0.1: v1(66.875,41.625) 68.175,42.925 76.575,42.925 76.725,42.775 78.425,42.775 78.765,43.115 80.275,43.115 81.791,41.598 86.678,41.598 88.156,40.119 90.331,40.119 90.975,39.475 90.975,37.405 90.15,36.58 90.15,31.073 89.875,30.798 v1(88.975,30.798)
  Signal Layer 2 w0.1: CN11.3@61.04,52.6 61.04,51.035 65.95,46.125 65.95,42.55 v1(66.875,41.625)
  Bottom Layer w0.1: U15.E3@88.575,31.198 v1(88.975,30.798)
ARD_D3: CN11.4 U15.N13 | length 45.5
  Top Layer w0.1: CN11.4@63.58,52.6 63.58,49.92 v1(65.3,48.2) ; v1(72.1,23.175) 72.498,23.573 75.348,23.573 75.35,23.575 77.802,23.575 79.425,25.198 v1(80.175,25.198)
  Signal Layer 2 w0.1: v1(65.3,48.2) 66.375,47.125 66.375,45.475 70,41.85 70,38.95 69.175,38.125 69.175,31.3 70.5,29.975 71.975,29.975 73.9,28.05 73.9,24.975 v1(72.1,23.175)
  Bottom Layer w0.1: v1(80.175,25.198) U15.N13@80.575,24.798
ARD_D4: CN11.5 U15.E5 | length 44.6
  Top Layer w0.1: v1(71.9,44.25) 72.45,44.8 80.478,44.8 81.454,43.823 86.798,43.823 88.597,42.025 90.454,42.025 92.1,40.379 v1(92.1,40.373)
  Signal Layer 2 w0.1: CN11.5@66.12,52.6 66.12,51.405 71.9,45.625 v1(71.9,44.25) ; v1(87.375,31.598) 87.8,32.023 88.35,32.023 91.675,35.348 91.675,39.948 v1(92.1,40.373)
  Bottom Layer w0.1: U15.E5@86.975,31.198 v1(87.375,31.598)
ARD_D5: CN11.6 U15.P15 | length 45.8
  Top Layer w0.1: v1(64.425,50.525) 68,50.525 68.66,51.185 CN11.6@68.66,52.6
  Signal Layer 2 w0.1: v1(64.425,50.525) 64.935,50.525 67.225,48.235 67.225,45.428 71.075,41.578 71.075,38.65 69.85,37.425 69.85,32.025 71.375,30.5 72.125,30.5 74.525,28.1 74.525,27.35 76.4,25.475 v1(76.4,21.423)
  Bottom Layer w0.1: v1(76.4,21.423) v1@76.402,21.425 ; v1@76.4,21.425 v1@76.402,21.425 ; U15.P15@78.975,23.998 78.438,23.462 78.438,22.713 77.15,21.425 v1@76.402,21.425
ARD_D6: CN11.7 U15.M12 | length 45
  Top Layer w0.1: v1(66.65,48.175) 68.075,48.175 71.2,51.3 CN11.7@71.2,52.6 ; v1(74.15,23.173) 77.9,23.173 79.55,24.823 80.6,24.823 v1(80.975,25.198)
  Signal Layer 2 w0.1: v1(66.65,48.175) 66.65,45.55 70.7,41.5 70.7,39.075 69.575,37.95 69.575,31.7 70.975,30.3 72.025,30.3 74.15,28.175 v1(74.15,23.173)
  Bottom Layer w0.1: v1(80.975,25.198) U15.M12@81.375,25.598
ARD_D7: CN11.8 U15.F3 | length 39.4
  Top Layer w0.1: v1(74.35,42.025) 78.325,42.025 78.948,42.648 80.459,42.648 81.708,41.398 86.595,41.398 88.074,39.919 90.248,39.919 90.775,39.392 90.775,37.488 89.95,36.663 89.95,32.298 89.625,31.973 89.62,31.973 89.4,31.754 89.4,31.493 89.13,31.223 88.6,31.223 v1(88.175,30.798)
  Signal Layer 2 w0.1: CN11.8@73.74,52.6 73.74,51.16 74.044,50.856 74.044,49.175 74.35,48.869 v1(74.35,42.025)
  Bottom Layer w0.1: v1(88.175,30.798) U15.F3@88.575,30.398
ARD_D8: CN10.1 U15.M3 | length 46.3
  Signal Layer 2 w0.1: v1(88.975,31.598) 88.975,32.365 89.433,32.823 91.355,32.823 92.3,33.768 92.3,39.065 93.55,40.315 93.55,45.55 94.151,46.151 94.151,49.849 v1(93.75,50.25)
  Signal Layer 4 w0.1: v1(88.975,25.198) 89.35,25.573 89.35,31.223 v1(88.975,31.598)
  Bottom Layer w0.1: CN10.1@77.804,52.6 79.379,51.025 92.975,51.025 v1(93.75,50.25) ; U15.M3@88.575,25.598 v1(88.975,25.198)
ARD_D9: CN10.2 U15.D4 | length 30.3
  Top Layer w0.1: v1(79.875,44.425) 80.287,44.425 81.289,43.423 86.633,43.423 88.708,41.348 v1(89.475,41.348) ; v1(88.175,32.398) 89.1,32.398 89.55,32.848 89.55,38.098 89.175,38.473 v1(89.125,38.473)
  Signal Layer 2 w0.1: v1(79.875,44.425) 79.875,45 79.977,45.102 79.977,50.977 80.344,51.344 CN10.2@80.344,52.6 ; v1(89.125,38.473) 89.525,38.873 89.525,41.298 v1(89.475,41.348)
  Bottom Layer w0.1: U15.D4@87.775,31.998 v1(88.175,32.398)
ARD_D10: CN10.3 U15.C13 | length 85.3
  Top Layer w0.1: v1(76,35.025) 76.95,34.075 76.95,33.65 77.35,33.25 77.75,33.25 77.802,33.198 v1(80.175,33.198)
  Signal Layer 2 w0.1: v1(69.35,41.675) 66.175,44.85 66.175,46.275 62.095,50.355 62.095,56.58 61.775,56.9 61.775,57.4 62.35,57.975 62.35,63.75 63.15,64.55 63.15,67 64.675,68.525 84.95,68.525 85.4,68.075 85.4,67.35 81.08,63.03 81.08,55.508 82.131,54.457 82.131,53.353 CN10.3@82.884,52.6
  Bottom Layer w0.1: v1(69.35,41.675) v1(76,35.025) ; v1(80.175,33.198) U15.C13@80.575,32.798
AUDIO_NRST: R44.2 U13.25 U15.G15 | length 84.1
  Top Layer w0.1: v1(38.7,21.3) 38.7,40.325 38.5,40.525 38.5,43.675 38.825,44 39.575,44 40.875,45.3 v1(40.875,49.7)
  Signal Layer 2 w0.1: v1(38.7,21.3) 40.85,21.3 48.475,13.675 50.225,13.675
  Signal Layer 2 w0.127: 50.225,13.675 58.523,13.675 71.35,26.502 v1(71.35,29.275)
  Bottom Layer w0.1: U13.25@40.875,48.675 v1(40.875,49.7) R44.2@40.875,50.725
  Bottom Layer w0.127: v1(71.35,29.275) 71.903,28.722 75.14,28.722 75.465,29.047 77.385,29.047 77.936,29.598 U15.G15@78.975,29.598
CKOUT: CN3.3 CN3.4 SB50.2 | length 134.5
  Top Layer w0.1: v1(84.975,3.025) 84.975,5.15 86.15,6.325 v1(86.15,9.975) ; v1(152.85,2.425) 152.85,14.675 153.875,15.7 153.875,23.7 155.75,25.575 155.75,53.38 CN3.4@154.575,54.555 CN3.3@153.305,54.555
  Bottom Layer w0.1: v1(84.975,3.025) 84.975,2.475 85.275,2.175 88.734,2.175 89.459,1.45 99.416,1.45 99.841,1.875 100.554,1.875 100.629,1.8 114.258,1.8 114.633,2.175 123.8,2.175 125.275,3.65 127.975,3.65 128.475,3.15 132.5,3.15 132.9,3.55 134.825,3.55 135.8,2.575 149.45,2.575 149.825,2.95 152.325,2.95 v1(152.85,2.425) ; v1(86.15,9.975) SB50.2@86.15,10.95
D0: U14.A8 U15.K12 | length 77.3
  Top Layer w0.127: v1(54.075,37.65) 55.325,38.9 70.475,38.9 70.675,38.7 70.675,34.025 70.6,33.95 70.35,33.95 70.25,34.05 70.25,38.25 70.15,38.35 69.832,38.35 69.732,38.25 69.732,26.118 69.834,26.016 70.325,26.016 70.425,26.116 70.425,32.325 70.5,32.4 70.775,32.4 70.85,32.325 70.85,26.125 70.959,26.016 71.275,26.016 71.35,26.091 71.35,28.7 ; 71.375,28.7 71.475,28.8 71.746,28.8 71.85,28.696 71.85,26.116 71.95,26.016 72.2,26.016 72.35,26.166 72.35,28.746 72.504,28.9 72.7,28.9 72.782,28.818 72.782,26.618 72.854,26.546 77.479,26.546 77.95,27.016 77.95,27.798 78.2,28.048 80.375,28.048 80.825,27.598 v1(80.975,27.598)
  Bottom Layer w0.127: U14.A8@53,36.1 53,36.575 v1(54.075,37.65) ; v1(80.975,27.598) U15.K12@81.375,27.198
D1: U14.B9 U15.K13 | length 79.2
  Top Layer w0.127: v1@55.7,38.25 55.969,38.519 69.156,38.519 69.351,38.324 69.351,25.859 69.575,25.635 77.265,25.635 77.278,25.622 77.288,25.622 78.465,26.798 v1(80.175,26.798)
  Bottom Layer w0.127: U14.B9@52.2,35.3 50.975,36.525 50.975,39.6 51.375,40 59.625,40 59.725,39.9 59.725,39.675 59.625,39.575 52.35,39.575 52.225,39.45 52.225,39.225 52.3,39.15 59.625,39.15 59.725,39.05 59.725,38.775 59.625,38.675 52.375,38.675 52.3,38.6 52.3,38.35 52.4,38.25 v1(55.725,38.25) ; v1(80.175,26.798) U15.K13@80.575,27.198
D2: U14.B8 U15.C11 | length 78
  Top Layer w0.1: 80.35,36.148 80.35,35.748 80.875,35.223 80.875,34.173 81.775,33.273 v1(81.775,33.198)
  Top Layer w0.127: v1(52.6,35.7) 52.6,36.9 54.994,39.294 70.619,39.294 71.056,38.858 71.056,34.269 72.642,32.683 72.642,29.5 73.167,28.975 73.975,28.975 74.05,29.05 74.05,31.875 74.125,31.95 74.425,31.95 74.525,31.85 74.525,29.075 74.625,28.975 74.825,28.975 74.925,29.075 74.925,39.425 75.025,39.525 75.275,39.525 75.4,39.4 75.4,35.625 75.475,35.55 75.7,35.55 75.8,35.65 75.8,39.425 75.9,39.525 76.125,39.525 76.3,39.35 76.3,35.65 76.425,35.525 76.65,35.525 76.725,35.6 76.725,39.3 76.95,39.525 79.723,39.525 80.35,38.898 80.35,36.148
  Bottom Layer w0.127: v1(52.6,35.7) U14.B8@53,35.3 ; v1(81.775,33.198) U15.C11@82.175,32.798
D3: U14.C9 U15.A12 | length 77.4
  Top Layer w0.127: v1(51.8,34.9) 51.8,34.923 52.189,35.311 52.189,36.298 52.218,36.327 52.218,38.8 52.292,38.875 54.036,38.875 54.125,38.964 54.125,39.225 54.075,39.275 52.293,39.275 52.218,39.35 52.218,39.593 52.3,39.675 70.777,39.675 71.437,39.016 71.437,34.427 73.175,32.689 73.175,29.506 73.256,29.425 73.525,29.425 73.625,29.525 73.625,39.875 73.725,39.975 73.975,39.975 74.1,39.85 74.1,32.4 74.169,32.331 74.481,32.331 74.544,32.394 74.544,39.619 74.922,39.997 79.79,39.997 80.731,39.056 80.731,35.842 v1(81.775,34.798)
  Bottom Layer w0.1: U15.A12@81.375,34.398 v1(81.775,34.798)
  Bottom Layer w0.127: v1(51.8,34.9) U14.C9@52.2,34.5
D4: U14.C8 U15.M9 | length 80.6
  Top Layer w0.127: v1(62.275,33.05) 62.275,32.55 62.425,32.4 62.425,21.156 62.65,20.931 65.419,20.931 65.737,20.613 65.737,19.923 65.408,19.594 60.194,19.594 59.925,19.325 59.925,17.8 60.075,17.65 65.7,17.65 65.825,17.525 65.825,17.225 65.7,17.1 60.025,17.1 59.925,17 59.925,16.675 60.069,16.531 83.581,16.531 83.725,16.675 83.725,24.875 83.402,25.198 v1(83.375,25.198)
  Signal Layer 2 w0.102: v1(52.6,34.9) 53,34.5 60.825,34.5 v1(62.275,33.05)
  Bottom Layer w0.127: v1(52.6,34.9) U14.C8@53,34.5 ; v1(83.375,25.198) U15.M9@83.775,25.598
D5: U14.D9 U15.R11 | length 77.4
  Top Layer w0.127: v1(51.8,34.1) 51.823,34.1 52.223,34.5 52.925,34.5 53.275,34.15 53.275,33.964 53.506,33.733 53.506,33.221 54.301,32.426 54.587,32.14 54.587,29.132 54.836,28.883 54.836,21.064 55.25,20.65 55.25,15.425 55.175,15.35 54.925,15.35 54.85,15.425 54.85,20.4 54.4,20.85 54.4,28.725 54.325,28.8 54.081,28.8 54.006,28.725 54.006,20.144 v1(54.4,19.75)
  Bottom Layer w0.127: v1(51.8,34.1) U14.D9@52.2,33.7 ; v1(54.4,19.75) 70.061,19.75 71.387,18.424 80.189,18.424 81.944,20.18 81.944,20.748 82.175,20.979 U15.R11@82.175,23.198
D6: U14.D8 U15.P11 | length 77.1
  Top Layer w0.127: v1(52.6,34.1) 53.125,33.575 53.125,33.063 54.206,31.982 54.206,29.567 53.625,28.986 v1(53.625,19.35)
  Bottom Layer w0.1: U15.P11@82.175,23.998 82.475,23.698 82.475,20.823 82.325,20.673
  Bottom Layer w0.127: v1(52.6,34.1) U14.D8@53,33.7 ; v1(53.625,19.35) 47.175,19.35 46.975,19.15 46.975,15.7 47.025,15.65 47.35,15.65 47.4,15.7 47.4,18.8 47.525,18.925 47.75,18.925 47.825,18.85 47.825,15.675 47.9,15.6 48.175,15.6 48.25,15.675 48.25,18.85 48.339,18.939 58.708,18.939 59.119,19.35 69.922,19.35 71.229,18.043 80.347,18.043 82.325,20.022 82.325,20.673
D7: U14.E9 U15.N11 | length 76.8
  Top Layer w0.127: v1(51.8,33.3) 52.525,32.575 53.074,32.575 53.825,31.824 53.825,29.725 53.538,29.438 53.225,29.125 53.225,20.8 53.15,20.725 52.9,20.725 52.825,20.8 52.825,29.225 52.725,29.325 52.45,29.325 52.4,29.275 52.4,15.724 52.512,15.612 52.737,15.612 52.825,15.7 52.825,19.75 v1(53.225,20.15)
  Bottom Layer w0.1: 81.563,20.623 81.563,20.804 81.875,21.116 81.875,24.498 U15.N11@82.175,24.798
  Bottom Layer w0.127: v1(51.8,33.3) U14.E9@52.2,32.9 ; v1(53.225,20.15) 70.2,20.15 71.545,18.805 80.031,18.805 81.563,20.337 81.563,20.623
D8: U14.E1 U15.R12 | length 80.9
  Top Layer w0.127: v1(59,33.3) 61,33.3 61.1,33.2 61.1,33 60.975,32.875 59.4,32.875 59.275,32.75 59.275,32.525 59.388,32.412 61.057,32.412 61.144,32.325 61.144,28.169 61.075,28.1 60.825,28.1 60.725,28.2 60.725,31.925 60.65,32 60.375,32 60.275,31.9 60.275,22.525 60.375,22.425 60.6,22.425 60.7,22.525 60.7,26.225 60.8,26.325 61.044,26.325 61.144,26.225 61.144,22.5 61.244,22.4 61.475,22.4 61.55,22.475 61.55,32.275 61.625,32.35 61.9,32.35 62.025,32.225 62.025,22.275 61.725,21.975 60.475,21.975 60.275,21.775 v1(60.275,20.95)
  Bottom Layer w0.127: U14.E1@58.6,32.9 v1(59,33.3) ; v1(60.275,20.95) 70.75,20.95 72.132,19.567 78.492,19.567 81.356,22.432 81.375,22.451 U15.R12@81.375,23.198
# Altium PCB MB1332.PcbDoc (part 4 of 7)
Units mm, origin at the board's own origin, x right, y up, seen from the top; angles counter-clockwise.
Board outline 161 x 75 mm, 6 copper layers (Top Layer, Signal Layer 1, Signal Layer 2, Signal Layer 3, Signal Layer 4, Bottom Layer), stack 1.57 mm thick; 387 components, 358 nets, 1659 pads, 1180 vias.

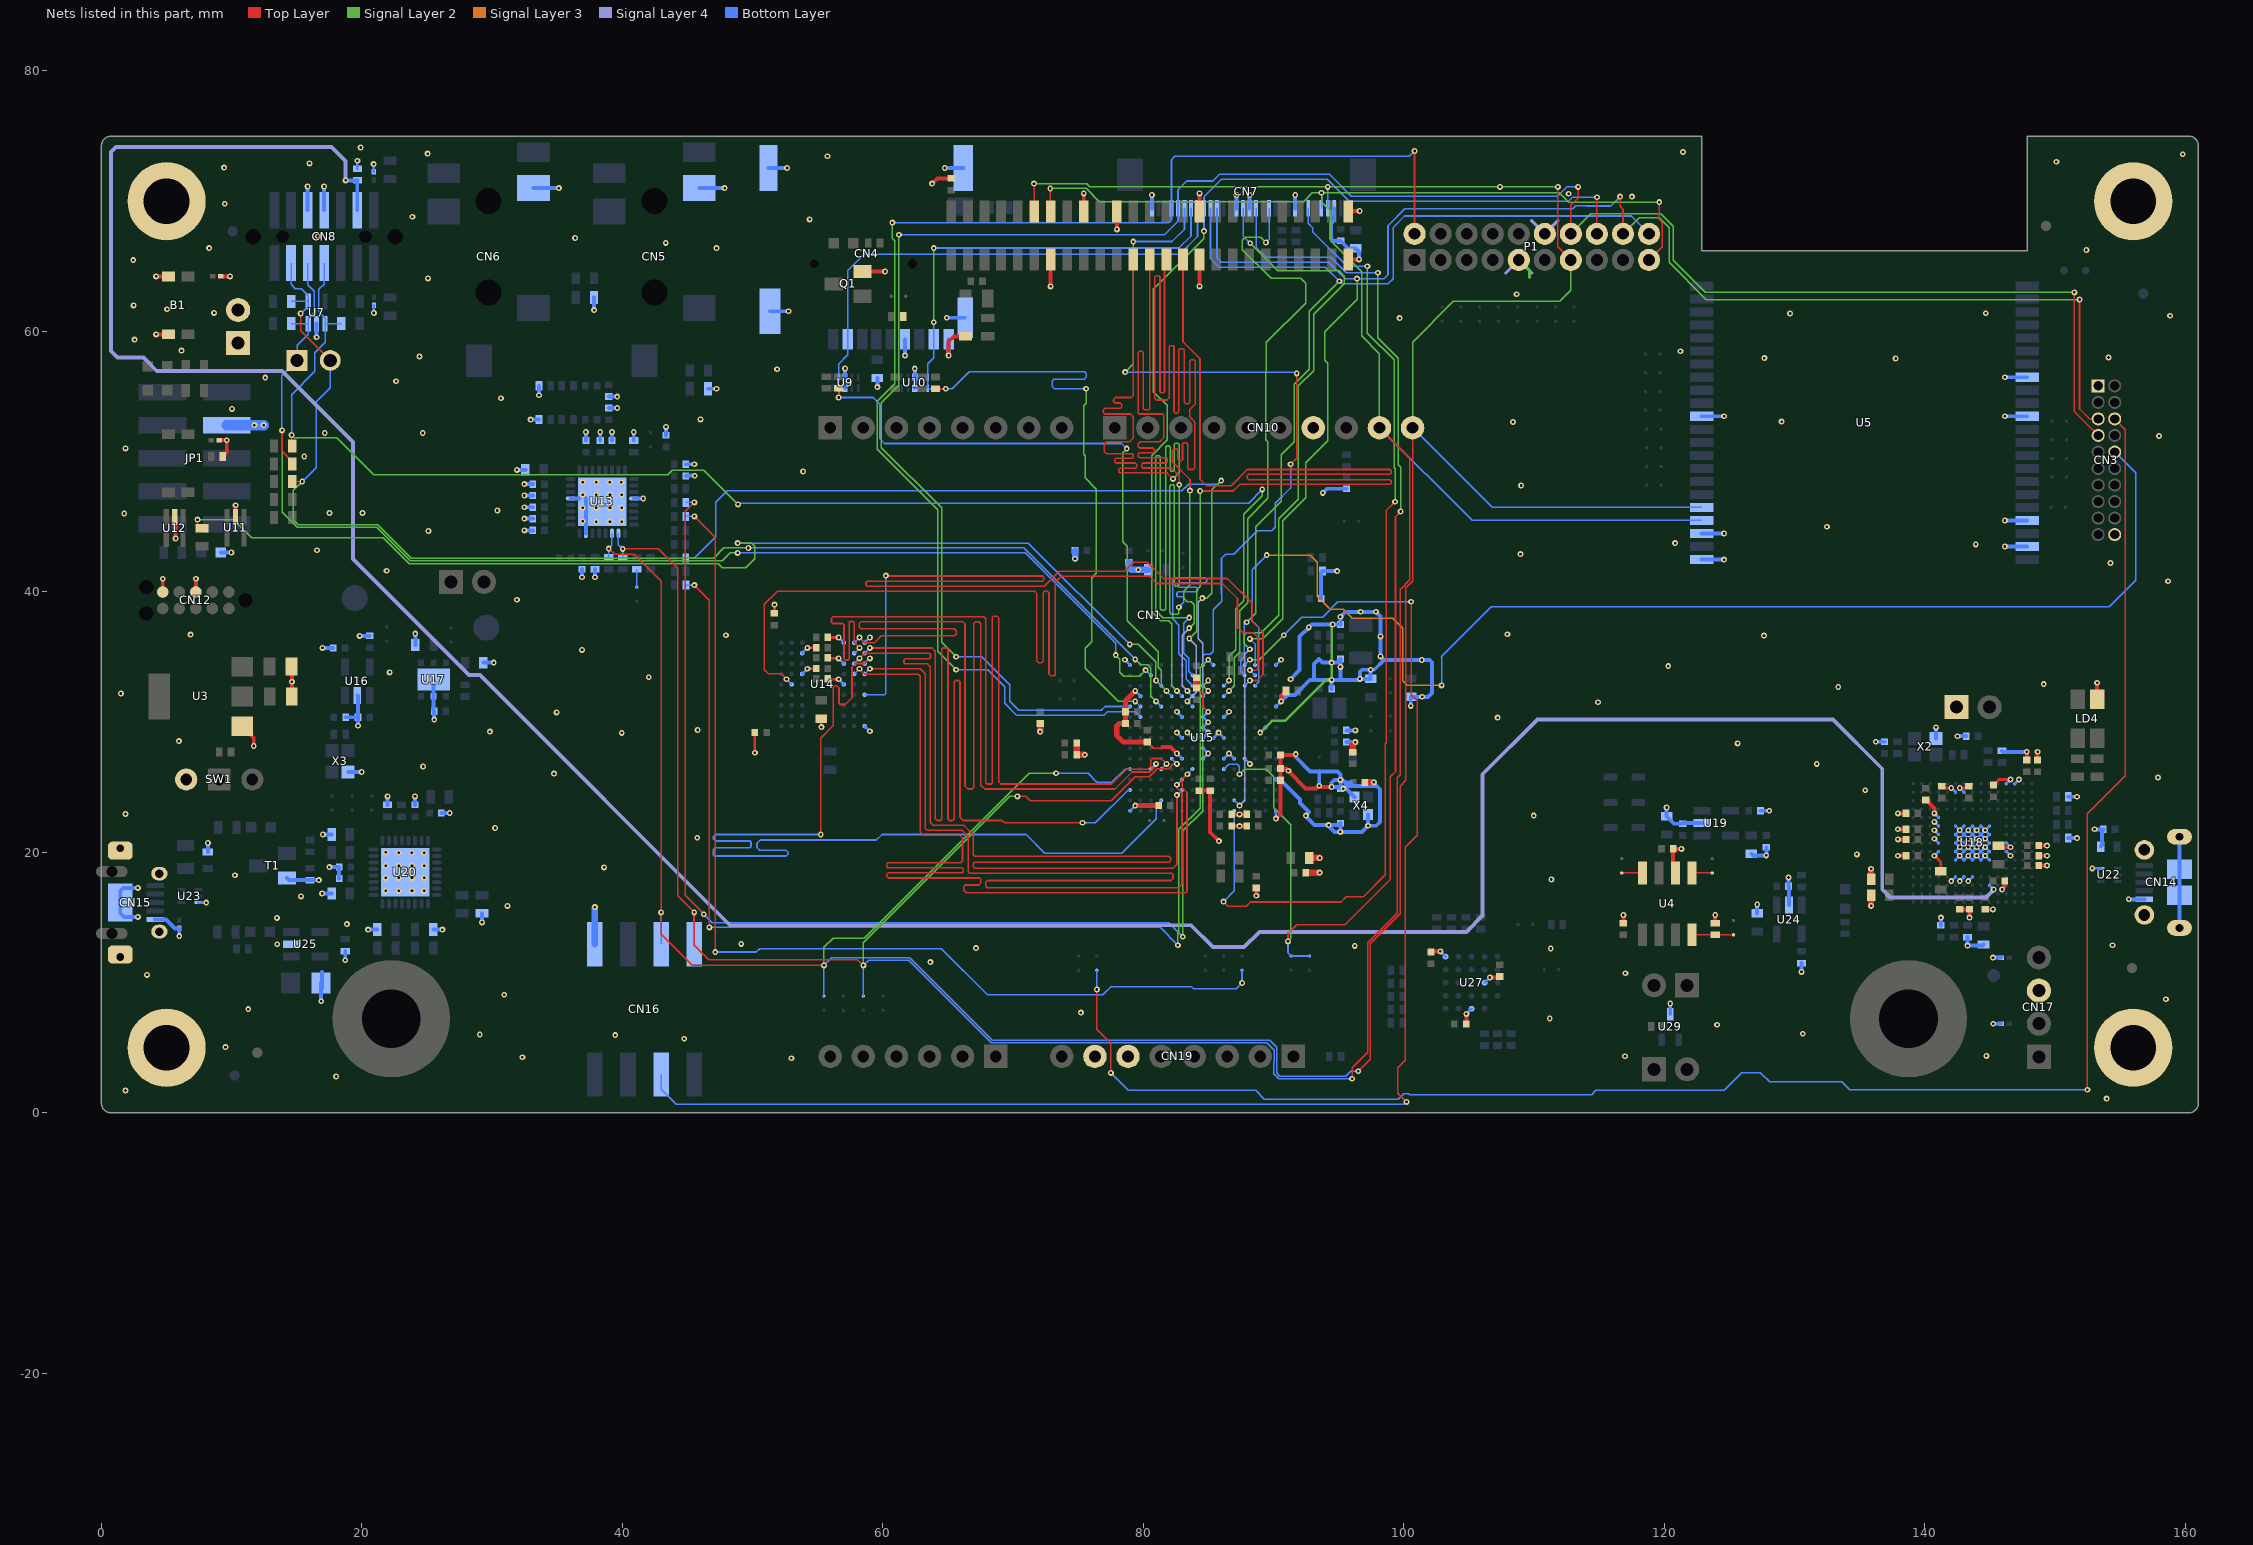
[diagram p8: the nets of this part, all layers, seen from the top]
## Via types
v1: diameter 0.45, hole 0.2, Top Layer to Bottom Layer, tented both sides, 1180 vias

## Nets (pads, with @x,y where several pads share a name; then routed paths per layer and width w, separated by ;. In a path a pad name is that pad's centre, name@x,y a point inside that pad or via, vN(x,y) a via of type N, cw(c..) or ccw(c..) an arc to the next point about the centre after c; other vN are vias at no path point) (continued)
D9: U14.D2 U15.L9 | length 77.4
  Top Layer w0.127: v1(58.2,34.1) 58.611,33.688 62.712,33.688 62.875,33.525 62.875,21.575 63.138,21.312 65.913,21.312 66.118,21.107 66.118,19.343 65.988,19.213 60.413,19.213 60.306,19.106 60.306,18.9 60.381,18.825 66.075,18.825 66.175,18.725 66.175,18.525 66.1,18.45 60.456,18.45 60.306,18.3 60.306,18.15 60.425,18.031 67.419,18.031 67.525,17.925 67.525,17.65 67.375,17.5 66.331,17.5 66.206,17.375 66.206,17.106 66.4,16.912 83.237,16.912 83.344,17.019 83.344,24.604 82.986,24.962 82.986,25.61 v1(83.375,25.998)
  Bottom Layer w0.127: U14.D2@57.8,33.7 v1(58.2,34.1) ; v1(83.375,25.998) U15.L9@83.775,26.398
D10: U14.D1 U15.M10 | length 77.6
  Top Layer w0.127: v1(59,34.1) 62.875,34.1 63.256,33.719 63.256,21.844 63.407,21.693 66.071,21.693 66.556,21.208 66.556,18.531 66.675,18.412 82.163,18.412 82.275,18.3 82.275,18 82.125,17.85 68.025,17.85 67.906,17.731 67.906,17.394 68.007,17.293 82.693,17.293 82.963,17.563 82.963,24.559 82.575,24.948 v1(82.575,25.198)
  Bottom Layer w0.127: U14.D1@58.6,33.7 v1(59,34.1) ; v1(82.575,25.198) U15.M10@82.975,25.598
D11: U14.C2 U15.N10 | length 80.8
  Top Layer w0.127: v1(58.2,34.9) 58.6,35.3 63.575,35.3 63.65,35.225 63.65,34.95 63.575,34.875 61.7,34.875 61.625,34.8 61.625,34.556 61.7,34.481 63.419,34.481 63.638,34.262 63.638,22.801 ; 63.637,22.8 63.637,22.313 63.876,22.074 66.229,22.074 66.937,21.366 66.937,19.825 67.056,19.706 81.944,19.706 82.1,19.55 82.1,19.375 81.975,19.25 67.05,19.25 66.937,19.137 66.937,18.913 67.057,18.793 82.268,18.793 82.575,19.1 v1(82.575,24.398)
  Bottom Layer w0.127: U14.C2@57.8,34.5 v1(58.2,34.9) ; v1(82.575,24.398) U15.N10@82.975,24.798
D12: U14.C1 U15.P12 | length 77.4
  Top Layer w0.127: v1(55.225,21.375) 55.225,28.775 56.188,29.738 56.188,32.663 56.275,32.75 56.5,32.75 56.625,32.625 56.625,31.45 56.713,31.363 57.112,31.363 57.625,31.875 57.625,34.2 57.925,34.5 58.6,34.5 v1(59,34.9)
  Bottom Layer w0.127: v1(55.225,21.375) 47.15,21.375 47,21.225 47,21.025 47.15,20.875 49.8,20.875 49.875,20.8 49.875,20.425 49.8,20.35 47.125,20.35 47,20.225 47,19.8 47.069,19.731 52.575,19.731 52.725,19.881 52.725,20 52.564,20.161 50.55,20.161 50.336,20.375 50.336,20.711 50.576,20.95 59.5,20.95 59.925,21.375 71,21.375 72.426,19.948 78.334,19.948 80.975,22.59 80.975,23.598 U15.P12@81.375,23.998 ; U14.C1@58.6,34.5 v1(59,34.9)
D13: U14.B2 U15.L12 | length 76.1
  Top Layer w0.127: v1(58.2,35.7) 57.8,36.1 57.8,37.65 57.725,37.725 57.475,37.725 57.425,37.675 57.425,34.875 57.325,34.775 57.1,34.775 57.018,34.857 57.018,37.483 56.925,37.575 56.15,37.575 56.05,37.675 56.05,37.975 56.175,38.1 67.75,38.1 67.9,37.95 67.9,25.325 67.971,25.254 68.329,25.254 68.4,25.325 68.4,38.05 68.488,38.138 68.762,38.138 68.9,38 68.9,25.425 69.071,25.254 77.581,25.254 78.725,26.398 80.35,26.398 80.563,26.612 80.563,27.037 80.736,27.21 81.363,27.21 v1(81.775,26.798)
  Bottom Layer w0.127: U14.B2@57.8,35.3 v1(58.2,35.7) ; U15.L12@81.375,26.398 v1(81.775,26.798)
D14: U14.B1 U15.N15 | length 82.1
  Top Layer w0.127: v1(59,35.7) 63.775,35.7 64.031,35.444 64.031,22.594 64.17,22.455 64.43,22.455 64.525,22.55 64.525,35.625 64.6,35.7 64.925,35.7 65,35.625 65,22.555 65.1,22.455 65.375,22.455 65.475,22.555 65.475,33.1 65.575,33.2 65.819,33.2 65.919,33.1 65.919,22.711 66.175,22.455 69.168,22.455 69.35,22.273 v1(75.325,22.273)
  Bottom Layer w0.127: U14.B1@58.6,35.3 v1(59,35.7) ; v1(75.325,22.273) 76.306,22.273 78.831,24.798 U15.N15@78.975,24.798
D15: U14.A2 U15.L13 | length 78.7
  Top Layer w0.127: v1(58.2,36.5) 58.6,36.1 59.35,36.1 59.875,36.625 65.5,36.625 65.625,36.75 65.625,37.025 65.475,37.175 58.325,37.175 58.181,37.319 58.181,37.581 58.319,37.719 66.125,37.719 66.3,37.544 66.3,25.1 66.527,24.873 66.85,24.873 66.975,24.998 66.975,37.575 67.119,37.719 67.356,37.719 67.519,37.556 67.519,25.167 67.813,24.873 77.825,24.873 79.123,26.171 80.498,26.171 80.975,26.648 v1(80.975,26.798)
  Bottom Layer w0.127: U14.A2@57.8,36.1 v1(58.2,36.5) ; U15.L13@80.575,26.398 v1(80.975,26.798)
DCMI_D0: CN7.4 P1.11 U15.F14 | length 105.5
  Top Layer w0.127: P1.11@100.82,67.49 v1@100.82,73.85
  Signal Layer 2 w0.102: v1(60.725,68.35) 60.725,67.15 60.919,66.956 60.919,56.002 59.575,54.658 59.575,50.95 64.2,46.325 64.2,35.45 v1(65.625,34.025)
  Bottom Layer w0.127: v1(60.725,68.35) 81.925,68.35 82.154,68.579 CN7.4@82.154,69.45 82.154,73.179 82.414,73.439 100.414,73.439 v1(100.825,73.85) ; v1(65.625,34.025) 68.05,34.025 69.35,32.725 69.35,31.448 70.263,30.535 76.975,30.535 77.238,30.798 79.375,30.798 U15.F14@79.775,30.398
DCMI_D1: CN3.7 CN7.5 P1.17 U15.E15 | length 166.6
  Top Layer w0.127: P1.17@112.82,67.49 112.82,69.695 113.375,70.25 v1(113.375,71.1) ; v1(151.475,63) 151.463,62.988 151.463,53.856 CN3.7@153.305,52.015
  Signal Layer 2 w0.102: v1(61.225,67.425) 61.225,55.875 59.881,54.531 59.881,51.077 64.506,46.452 64.506,36.144 v1(65.625,35.025) ; P1.17@112.82,67.49 114.361,69.031 119.727,69.031 120.681,68.077 120.681,65.469 123.15,63 v1(151.475,63)
  Bottom Layer w0.127: v1(61.225,67.425) 81.625,67.425 82.654,68.454 CN7.5@82.654,69.45 82.654,70.879 83.325,71.55 85.336,71.55 85.842,72.056 94.283,72.056 95.964,70.375 111.799,70.375 112.524,71.1 v1(113.375,71.1) ; v1(65.625,35.025) 67.589,35.025 69.731,32.883 69.731,31.606 70.421,30.916 76.768,30.916 77.05,31.198 U15.E15@78.975,31.198
DCMI_D2: CN7.6 U15.A8 | length 56
  Top Layer w0.127: v1(91.3,49.8) 91.775,50.275 v1(91.775,56.775)
  Signal Layer 2 w0.102: v1(78.6,56.875) 79.225,57.5 v1(79.225,66.9)
  Bottom Layer w0.1: U15.A8@84.575,34.398 84.575,35.1 84.698,35.223 85.13,35.223 85.35,35.443 85.35,38.65 86,39.3 86,39.848
  Bottom Layer w0.127: v1(78.6,56.875) 91.675,56.875 v1(91.775,56.775) ; v1(79.225,66.9) 82.2,66.9 83.154,67.854 CN7.6@83.154,69.45 ; 86,39.848 86,42.575 86.312,42.887 86.937,42.887 88.75,44.7 89.85,44.7 90.125,44.975 90.125,46.8 91.3,47.975 v1(91.3,49.8)
DCMI_D3: CN4.8 CN7.7 R9.1 U10.5 U10.6 U15.E14 | length 80.7
  Top Layer w0.127: R9.1@64.025,55.6 v1(64.825,55.6)
  Signal Layer 2 w0.102: v1(63.9,60.7) v1(63.9,66.4) ; v1(75.6,55.6) 75.6,54.5 75.412,54.312 75.412,50.571 75.525,50.458 75.525,48.75 76.395,47.88 76.395,41.42 76.026,41.051 76.026,36.174 75.525,35.673 75.525,34.125 78.052,31.598 v1(79.375,31.598)
  Bottom Layer w0.127: v1(63.9,60.7) CN4.8@63.9,59.4 63.9,57.975 63.45,57.525 U10.5@63.45,56.47 63.45,55.675 63.525,55.6 v1(64.825,55.6) 65.325,55.6 66.625,56.9 75.5,56.9 75.6,56.8 75.6,56.475 75.45,56.325 73.125,56.325 73,56.2 73,55.775 73.175,55.6 v1(75.6,55.6) ; v1(63.9,66.4) 82.725,66.4 83.654,67.329 CN7.7@83.654,69.45 ; v1(79.375,31.598) U15.E14@79.775,31.198
DCMI_D4: CN4.2 CN7.8 R6.1 U9.2 U9.9 U15.D11 | length 86.8
  Top Layer w0.127: v1(56.6,54.925) R6.1@56.6,55.625
  Signal Layer 2 w0.1: 78.756,40.152 78.756,37.794 81.15,35.4 81.15,35.073
  Signal Layer 2 w0.102: v1(78.725,51) 78.4,50.675 78.4,43.863 78.756,43.507 78.756,40.152 ; 81.15,35.073 81.15,34.198 81.375,33.973 81.375,32.798 v1(81.775,32.398)
  Bottom Layer w0.127: v1(78.725,51) 78.325,51.4 60.125,51.4 59.775,51.75 59.775,54.4 59.25,54.925 v1(56.6,54.925) U9.9@56.6,55.655 U9.2@56.6,56.475 56.6,57.5 57.3,58.2 CN4.2@57.3,59.4 57.3,64.675 58.544,65.919 82.783,65.919 84.154,67.29 CN7.8@84.154,69.45 ; v1(81.775,32.398) U15.D11@82.175,31.998
DCMI_D5: CN7.9 P1.18 U15.D10 | length 76.6
  Top Layer w0.127: P1.18@114.82,67.49 v1@114.82,70.295
  Signal Layer 2 w0.1: 80.625,39.848 80.625,38.475 81.327,37.773 81.948,37.773 81.95,37.775 82.175,37.55 82.175,35.298
  Signal Layer 2 w0.102: 80.625,39.848 80.625,50.467 81.826,51.668 81.826,54.331 80.775,55.382 80.775,63.25 84.65,67.125 v1(84.65,67.7) ; 82.175,35.298 82.175,32.798 v1(82.575,32.398)
  Bottom Layer w0.127: v1(82.575,32.398) U15.D10@82.975,31.998 ; v1(84.65,67.7) 84.65,69.446 CN7.9@84.654,69.45 84.654,70.329 86,71.675 94.125,71.675 95.806,69.994 112.644,69.994 112.95,70.3 v1(114.825,70.3)
DCMI_D6: CN7.10 P1.20 U15.B4 | length 76.9
  Signal Layer 2 w0.102: v1(87.925,37.673) 88.62,38.368 88.62,44.993 90.6,46.973 90.6,50.525 91.6,51.525 91.6,55.95 92.75,57.1 92.75,61.55 v1(95.05,63.85)
  Bottom Layer w0.1: 87.6,34.898 87.475,34.773 87.475,33.898 U15.B4@87.775,33.598
  Bottom Layer w0.127: CN7.10@85.154,69.45 85.154,65.596 85.819,64.931 93.969,64.931 v1(95.05,63.85) 95.25,63.65 98.775,63.65 99.175,64.05 99.175,67.986 100.05,68.862 117.448,68.862 P1.20@118.82,67.49 ; 87.6,34.898 87.735,35.033 87.735,37.483 v1(87.925,37.673)
DCMI_D7: CN3.5 CN7.11 P1.19 U15.A3 | length 127
  Top Layer w0.127: v1(116.6,70.35) 116.6,69.6 116.82,69.38 P1.19@116.82,67.49 ; v1(151.875,62.45) 151.875,54.05 152.64,53.285 CN3.5@153.305,53.285
  Signal Layer 2 w0.102: v1(88.175,36.398) 89.148,36.398 90.706,37.956 90.706,45.473 92.479,47.246 92.479,49.929 94.15,51.6 94.15,57.575 93.925,57.8 93.925,59.994 96.4,62.469 v1(96.4,64.05) ; P1.19@116.82,67.49 118.055,68.725 119.6,68.725 120.375,67.95 120.375,65.3 123.225,62.45 v1(151.875,62.45)
  Bottom Layer w0.127: CN7.11@85.654,69.45 85.654,65.635 85.977,65.312 94.224,65.312 95.486,64.05 v1(96.4,64.05) 98.475,64.05 98.775,64.35 98.775,68.125 100.075,69.425 112.975,69.425 113.189,69.639 113.986,69.639 113.999,69.625 115.875,69.625 v1(116.6,70.35) ; v1(88.175,36.398) 88.575,35.998 U15.A3@88.575,34.398
DCMI_HSYNC: CN7.17 SB44.1 SB45.1 U15.L6 | length 91.9
  Top Layer w0.127: v1(91.1,13.175) 91.1,13.775 91.769,14.444 95.483,14.444 98.956,17.917 98.956,25.817 99.35,26.211 99.35,45.775 v1(99.75,46.175)
  Signal Layer 2 w0.102: v1(87.375,25.998) 87.775,26.398 89.425,26.398 90,25.823 90,23.448 91.331,22.117 91.331,13.406 v1(91.1,13.175) ; v1(98,64.5) 98,59.508 99.556,57.952 99.556,50.544 99.565,50.535 ; 99.556,50.525 99.556,49.752 99.75,49.558 v1(99.75,46.175)
  Bottom Layer w0.1: U15.L6@86.175,26.398 86.55,26.773 87.2,26.773 87.375,26.598 v1(87.375,25.998)
  Bottom Layer w0.127: CN7.17@88.654,69.45 88.654,66.446 89.407,65.693 94.382,65.693 95.575,64.5 v1(98,64.5) ; v1(91.1,13.175) 91.1,12.3 SB45.1@91.35,12.05 SB44.1@92.75,12.05
DCMI_PIXCLK: CN7.15 U15.P5 | length 56.7
  Signal Layer 2 w0.102: v1(88.175,35.598) 87.75,36.023 87.75,36.698 87.9,36.848 89.048,36.848 90.4,38.2 90.4,45.6 91.906,47.106 91.906,55.823 93.075,56.992 93.075,61.3 95.426,63.651 95.426,64.249 95.025,64.65 90.325,64.65 v1(88.2,66.775)
  Signal Layer 4 w0.1: v1(87.375,23.598) 87.775,23.998 87.775,35.198 v1(88.175,35.598)
  Bottom Layer w0.127: U15.P5@86.975,23.998 v1(87.375,23.598) ; CN7.15@87.654,69.45 87.654,67.321 v1(88.2,66.775)
DCMI_PWR_EN: CN7.25 U15.R5 | length 76
  Top Layer w0.127: v1(86.15,16.225) 86.5,15.875 87.9,15.875 88.225,16.2 95.175,16.2 95.575,16.6 96.899,16.6 98.575,18.276 98.575,26.985 98.561,26.999 98.561,28.334 98.65,28.423 98.65,46.25 v1(99.325,46.925)
  Signal Layer 2 w0.102: v1(97.2,65) 97.2,59.875 99.25,57.825 99.25,49.55 99.325,49.475 v1(99.325,46.925)
  Bottom Layer w0.127: v1(86.15,16.225) 86.975,17.05 U15.R5@86.975,23.198 ; CN7.25@92.654,69.45 92.654,68.296 93.013,67.936 93.013,67.637 95.65,65 v1(97.2,65)
DCMI_VSYNC: CN7.19 U15.D6 | length 45.9
  Signal Layer 2 w0.102: v1(86.575,32.398) 86.975,32.798 86.975,34.948 87.4,35.373 87.4,38.573 88.01,39.183 88.01,45.635 89.55,47.175 89.55,51.525 89.381,51.694 89.381,56.85 89.451,56.92 89.451,59.176 92.45,62.175 92.45,63.7 92.075,64.075 89.8,64.075 87.6,66.275 87.6,67.025 87.625,67.025 87.825,67.225 89,67.225 v1(89.4,66.825)
  Bottom Layer w0.127: U15.D6@86.175,31.998 v1(86.575,32.398) ; v1(89.4,66.825) 89.654,67.079 CN7.19@89.654,69.45
DETECTn: CN3.10 U15.C3 | length 100.8
  Signal Layer 3 w0.1: v1(89.475,42.825) 92.8,42.825 93.35,42.275 93.35,39.675 94.363,38.662 95.363,38.662 96.05,37.975 99.151,37.975 99.906,37.22 99.906,33.165 100.247,32.825 v1(102.9,32.825)
  Bottom Layer w0.1: U15.C3@88.575,32.798 88.875,33.098 88.875,37.242 88.35,37.767 88.35,41.7 v1(89.475,42.825) ; v1(102.9,32.825) 102.9,34.975 102.85,35.025 106.7,38.875 154.15,38.875 156.175,40.9 156.175,49.145 CN3.10@154.575,50.745
DFSDM1_2_DATIN1: CN3.6 SB48.2 | length 138.7
  Top Layer w0.1: v1(76.425,9.475) 76.425,6.425 77.5,5.35 v1(77.5,3.075) ; v1(152.475,1.775) 152.475,22.975 155.4,25.9 155.4,52.46 CN3.6@154.575,53.285
  Bottom Layer w0.1: v1(76.425,9.475) SB48.2@76.425,10.95 ; v1(77.5,3.075) 78.85,1.725 88.619,1.725 89.294,1.05 99.581,1.05 100.006,1.475 100.388,1.475 100.463,1.4 114.424,1.4 114.749,1.725 124.575,1.725 124.692,1.842 125.95,3.1 127.35,3.1 128.075,2.375 133.625,2.375 134.225,1.775 v1(152.475,1.775)
E5V: CN2.1 JP1.3 | length 2.8
  Bottom Layer w0.8: JP1.3@9.625,52.805 v1(11.75,52.805) v1(12.45,52.805)
EXT_RESET: CN16.5 U15.A4 | length 113.2
  Top Layer w0.1: v1(100.2,0.85) 99.525,1.525 99.525,3.45 100.118,4.043 100.118,20.393 101.025,21.3 101.025,31.65 100.55,32.125 v1(100.55,39.25)
  Signal Layer 2 w0.1: v1(88.175,34.798) 88.898,34.798 v1(90.775,36.675)
  Bottom Layer w0.1: CN16.5@42.97,2.95 42.97,1.83 44.15,0.65 100,0.65 v1(100.2,0.85) ; U15.A4@87.775,34.398 v1(88.175,34.798) ; v1(90.775,36.675) 92.175,38.075 93.758,38.075 94.933,39.25 v1(100.55,39.25)
FDCAN_RX: SB3.1 U4.4 | length 1.6
  Top Layer w0.1: SB3.1@116.725,18.425 U4.4@118.32,18.425
FDCAN_STBY: R20.1 SB5.1 U4.8 | length 3.2
  Top Layer w0.1: U4.8@122.13,13.675 R20.1@123.9,13.675 SB5.1@125.3,13.675
FDCAN_TX: SB4.1 U4.1 | length 1.5
  Top Layer w0.1: U4.1@122.13,18.425 SB4.1@123.675,18.425
FMC_NBL0: U14.E8 U15.B3 | length 77.1
  Top Layer w0.127: v1(52.6,33.3) 52.189,33.711 51.214,33.711 50.9,34.025 50.9,39.05 51.906,40.056 71.65,40.056 71.825,39.881 71.825,34.7 71.95,34.575 72.2,34.575 72.3,34.675 72.3,39.956 72.4,40.056 72.619,40.056 72.75,39.925 72.75,33.7 72.875,33.575 73.15,33.575 73.244,33.669 73.244,40.744 73.7,41.2 80.475,41.2 81.025,40.65 86.065,40.65 87.225,39.49 87.225,37.298 87.65,36.873 88.45,36.873 88.801,36.522 88.801,34.148 88.651,33.998 v1(88.175,33.998)
  Bottom Layer w0.127: v1(52.6,33.3) U14.E8@53,32.9 ; v1(88.175,33.998) U15.B3@88.575,33.598
FMC_NBL1: U14.F1 U15.C4 | length 76.4
  Top Layer w0.127: v1(60.225,41.25) 60.25,41.225 72.25,41.225 72.35,41.125 72.35,40.925 72.25,40.825 58.8,40.825 58.7,40.725 58.7,40.525 58.788,40.437 72.399,40.437 73.542,41.581 78.556,41.581 79.255,42.28 80.307,42.28 81.556,41.031 86.442,41.031 88.35,39.123 88.35,37.723 89.182,36.891 89.182,33.648 88.732,33.198 v1(88.175,33.198)
  Bottom Layer w0.127: U14.F1@58.6,32.1 60.125,32.1 60.225,32.2 v1(60.225,41.25) ; U15.C4@87.775,32.798 v1(88.175,33.198)
GND: B1.1 B1.2 C1.2 C4.2 C5.1 C6.2 C7.2 C8.1 C9.2 C10.1 C11.2 C12.2 C13.2 C14.1 C15.2 C16.2 C17.2 C18.2 C19.2 C20.2 C21.2 C22.2 C23.1 C24.2 C25.2 C26.1 C27.2 C28.2 C29.1 C30.2 C31.2 C32.2 C33.2 C34.2 C35.1 C36.2 C37.1 C38.2 C39.2 C40.2 C41.2 C42.2 C43.2 C44.1 C45.2 C46.1 C47.2 C48.2 C49.2 C50.1 C51.2 C52.1 C53.2 C54.2 C55.1 C56.2 C57.2 C58.2 C59.2 C60.1 C61.1 C62.1 C63.1 C64.1 C66.2 C68.2 C70.1 C72.2 C73.1 C74.1 C75.2 C76.1 C77.1 C78.1 C79.2 C80.2 C81.2 C82.2 C83.1 C84.2 C85.2 C86.2 C88.1 C89.1 C90.1 C91.1 C92.1 C93.1 C94.1 C95.1 C96.1 C97.1 C98.1 C99.1 C100.1 C101.1 C102.1 C103.1 C104.2 C105.1 C106.2 C107.1 C108.2 C109.1 C110.1 C111.2 C112.1 C113.2 C114.1 C115.1 C116.2 C117.2 C118.2 C119.2 C120.1 C121.1 C122.1 C123.1 C124.2 CN1.1 CN1.2 CN1.19 CN1.20 CN1.30 CN1.34 CN1.37 CN2.2 CN3.1 CN3.20 CN4.6 CN4.9 CN4.11 CN4.12 CN4.13 CN4.14 CN5.3 CN6.3 CN7.1 CN7.14 CN7.16 CN7.23 CN7.29 CN8.5 CN8.7 CN10.7 CN12.3 CN12.5 CN13.1 CN14.5 CN14.6 CN14.7 CN14.8 CN14.9 CN14.10 CN14.11 CN15.5 CN15.6 CN15.7 CN15.8 CN15.9 CN15.10 CN16.2 CN17.3 CN19.6 CN19.7 D4.2 H1.1 H2.1 H3.1 H4.1 LD4.1 LD5.2 P1.5 P1.16 Q1.2 R2.1 R11.1 R14.2 R20.2 R23.1 R27.1 R34.2 R35.1 R43.1 R44.1 R57.2 R58.1 R69.1 R73.2 R76.1 R81.2 R82.1 R86.2 R88.1 R95.2 R98.1 R100.1 R101.1 R105.2 R115.1 SB39.1 SW1.3 T1.2 U1.2 U2.2 U3.1 U4.2 U5.1 U5.3 U5.12 U5.30 U5.33 U5.41 U5.43 U6.2 U7.2 U8.2 U9.3 U9.8 U10.3 U10.8 U11.2 U12.2 U13.7 U13.13 U13.28 U13.33 U14.A1 U14.A3 U14.B7 U14.C3 U14.D7 U14.E3 U14.J1 U15.A1 U15.A15 U15.D14 U15.E1 U15.F6 U15.F8 U15.F10 U15.G2 U15.G8 U15.H6 U15.H7 U15.H8 U15.H9 U15.H10 U15.J8 U15.K4 U15.K5 U15.K6 U15.K8 U15.K10 U15.M1 U15.R1 U15.R15 U16.2 U17.2 U17.EP U18.D5 U18.D6 U18.D7 U18.D8 U18.D9 U18.F2 U18.F6 U18.F7 U18.F8 U18.F9 U18.F10 U18.F12 U18.G2 U18.G6 U18.G7 U18.G8 U18.G9 U18.G10 U18.G12 U18.H6 U18.H7 U18.H8 U18.H9 U18.H10 U18.H12 U18.J6 U18.J7 U18.J8 U18.J9 U18.J10 U18.K6 U18.K7 U18.K8 U18.K9 U18.K10 U18.M1 U18.M8 U18.M9 U18.N1 U19.2 U20.33 U21.2 U22.3 U23.3 U24.2 U25.2 U26.2 U27.B3 U27.C1 U27.E5 U28.2 U29.3 U30.2 X2.2 X3.2 X4.2 X4.4 | length 380.7
  Top Layer w0.15: C18.2@80.3,28.473 80.775,27.998 81.35,27.998 81.45,28.098 ; C13.2@84.075,32.623 84.175,32.623 84.575,32.223 84.575,31.198 v1(84.975,30.798)
  Top Layer w0.2: v1(50.175,27.65) C19.2@50.175,29.2 ; C4.2@51.675,38.35 v1(51.675,39.025) ; v1(54.2,34.1) 54.85,34.1 C11.2@54.875,34.125 ; v1(54.2,35.7) 54.85,35.7 C7.2@54.875,35.725 ; v1(55.275,29.625) C14.1@55.275,30.275 ; C12.2@55.775,33.325 55.8,33.3 v1(56.6,33.3) ; C9.2@55.775,34.95 55.825,34.9 v1(56.6,34.9) ; C6.2@55.775,36.525 55.8,36.5 v1(56.6,36.5) ; v1(140.725,19.75) 141.225,19.25 C50.1@141.225,18.55 ; C32.2@141.3,25.075 141.425,24.95 v1(142.025,24.95) ; v1(142.675,24.95) 143.25,24.95 C33.2@143.375,25.075 ; C31.2@145.275,25.175 145.7,25.6 v1(146.575,25.6)
  Top Layer w0.3: v1(4.2,59.775) B1.1@5.15,59.775 ; v1(4.2,64.225) B1.2@5.15,64.225 ; CN12.5@4.71,39.995 v1(4.71,41.015) ; U12.2@5.625,45.75 5.625,45.05 5.7,44.975 v1(5.7,44.1) ; CN12.3@7.25,39.995 v1(7.25,41.015) ; U2.2@9.05,51.65 v1(9.625,51.65) 9.625,50.7 R11.1@9.325,50.4 ; U1.2@9.162,64.225 v1(9.875,64.225) ; U11.2@10.3,45.775 v1@10.3,46.55 ; U3.1@10.799,29.672 11.7,28.77 v1(11.7,28.175) ; C5.1@14.599,34.272 14.624,34.247 v1(14.624,33.109) C8.1@14.624,31.972 ; Q1.2@58.425,64.6 v1(60.175,64.6) ; v1(63.775,71.35) 64.175,71.75 C1.2@65.25,71.75 ; v1(65.05,58.15) 65.05,59.225 65.45,59.625 R2.1@66.35,59.625 ; v1(72.88,63.455) CN1.37@72.88,65.531 ; CN1.34@75.42,69.217 v1(75.42,70.595) ; v1(77.96,67.839) CN1.30@77.96,69.217 ; 81.45,28.098 82.075,28.098 v1(82.575,27.598) ; C27.2@84.275,24.748 C28.2@85.125,24.748 85.125,21.548 v1(85.8,20.873) ; v1(84.31,63.455) CN1.19@84.31,65.531 ; CN1.20@84.31,69.217 v1(84.31,70.595) ; C39.2@86.775,22.023 v1(87.375,22.023) C40.2@87.925,22.023 ; C37.1@86.775,22.923 v1(87.375,22.923) C38.2@87.925,22.923 ; v1(88.675,16.673) C53.2@88.675,17.273 ; v1(90.175,22.598) 90.525,22.948 C29.1@90.525,25.548 C26.1@90.525,26.448 ; v1(90.575,31.598) 90.575,32.023 R14.2@90.95,32.398 ; v1(91.127,26.269) v1@91.125,26.267 ; v1(91.7,27.548) 91.625,27.473 C23.1@90.525,27.473 C26.1@90.525,26.448 ; v1(94.45,25.023) 93.6,25.023 v1(93.5,25.123) 93.3,24.923 92.45,24.923 91.125,26.248 v1@91.125,26.267 ; CN1.1@95.74,65.531 v1(96.55,65.531) ; CN1.2@95.74,69.217 95.773,69.25 v1(96.6,69.25) ; C60.1@102.075,12.35 102.125,12.4 v1(102.8,12.4) ; C62.1@104.8,6.925 v1(104.8,7.6) ; v1(106.6,10.4) 107.25,10.4 C61.1@107.325,10.475 ; C59.2@116.85,14.575 v1(116.85,15.2) ; U4.2@120.86,18.425 120.675,18.61 C45.2@120.675,20.275 v1(121.3,20.275) ; R20.2@123.9,14.575 v1(123.9,15.2) ; v1(137.925,19.75) C47.2@138.55,19.75 ; v1(137.925,21) C42.2@138.55,21 ; v1(137.925,21.775) C41.2@138.55,21.775 ; v1(137.925,23) C36.2@138.55,23 ; C34.2@140.075,24.025 140.725,23.375 v1(140.725,23) ; C56.2@142.675,15.625 C57.2@143.425,15.625 v1(143.425,15) ; C58.2@144.625,15.625 v1(145.225,15.625) ; C44.1@145.65,20.5 145.75,20.4 v1(146.575,20.4) ; v1(145.925,17.15) 146.125,17.35 C54.2@146.125,17.8 ; C24.2@147.825,27.1 v1(147.825,27.725) ; C25.2@148.65,27.1 v1(148.65,27.725) ; C49.2@148.75,19 v1(149.375,19) ; C48.2@148.75,19.75 v1(149.375,19.75) ; C43.2@148.75,20.525 v1(149.375,20.525) ; LD4.1@153.225,31.775 v1(153.225,33.025) ; C26.1@90.525,26.448 90.943,26.448 v1@91.125,26.267
  Top Layer w0.4: v1(79.375,23.598) C35.1@81.175,23.598 ; v1(79.375,32.398) 78.625,31.648 C15.2@78.625,30.798 C17.2@78.625,29.898 78.15,29.898 77.95,29.698 77.95,28.973 78.45,28.473 C18.2@80.3,28.473
  Top Layer w0.45: v1(135.875,15.9) C55.1@135.875,16.7 ; C52.1@135.875,17.95 v1(135.875,18.75)
  Top Layer w0.5: v1(72.075,29.273) C16.2@72.075,29.898 ; C20.2@74.875,28.398 C22.2@74.875,27.498 v1(75.5,27.498) ; C13.2@84.075,32.623 C10.1@84.075,33.423 ; C51.2@92.475,18.448 v1(93.525,18.448) ; C46.1@92.725,19.573 v1(93.525,19.573) ; C21.2@96.075,27.698 96.075,28.273 v1(96.275,28.473) ; C30.2@97,25.373 v1(97.7,25.373)
  Signal Layer 2 w0.2: v1(88.975,29.198) 89.875,30.098 90.877,30.098 94.027,33.248 v1(94.45,33.248) v1(94.45,34.573) 94.45,37.423 v1(94.525,37.498)
  Signal Layer 2 w0.25: P1.5@108.82,65.49 109.65,64.66 109.65,64.15
  Signal Layer 4 w0.25: 107.815,64.485 P1.5@108.82,65.49 109.825,64.485 ; 109.815,68.495 P1.16@110.82,67.49 111.825,68.495
  Bottom Layer w0.2: U23.3@7.45,16.15 v1(8.05,16.15) ; R23.1@19.65,72.5 v1(19.65,73.1) ; U6.2@20.9,72.25 v1(20.9,72.85) ; v1(20.925,61.413) U8.2@20.925,62.013 ; U14.D7@53.8,33.7 v1(54.2,34.1) ; U14.B7@53.8,35.3 v1(54.2,35.7) ; v1(56.6,33.3) U14.E3@57,32.9 ; v1(56.6,34.9) U14.C3@57,34.5 ; v1(56.6,36.5) U14.A3@57,36.1 ; U14.J1@58.6,29.7 v1(59,29.3) ; U14.A1@58.6,36.1 v1(59,36.5) ; v1(78.575,34.798) U15.A15@78.975,34.398 ; U15.R15@78.975,23.198 v1(79.375,23.598) ; v1(79.375,32.398) U15.D14@79.775,31.998 ; v1(82.575,27.598) U15.K10@82.975,27.198 ; v1(82.575,29.198) U15.H10@82.975,28.798 ; v1(82.575,30.798) U15.F10@82.975,30.398 ; v1(83.375,29.198) U15.H9@83.775,28.798 ; U15.K8@84.575,27.198 v1(84.975,27.598) U15.J8@84.575,27.998 ; U15.H8@84.575,28.798 v1(84.975,29.198) U15.G8@84.575,29.598 v1(84.975,29.998) U15.F8@84.575,30.398 v1(84.975,30.798) ; U15.H7@85.375,28.798 v1(85.775,29.198) U15.H6@86.175,28.798 ; U15.K6@86.175,27.198 v1(86.575,27.598) U15.K5@86.975,27.198 ; U15.F6@86.175,30.398 v1(86.575,30.798) ; U15.K4@87.775,27.198 v1(88.175,26.798) ; v1(88.975,29.198) U15.G2@89.375,29.598 ; v1(90.175,22.598) U15.R1@90.175,23.198 ; U15.E1@90.175,31.198 v1(90.575,31.598) ; U15.A1@90.175,34.398 v1(90.575,34.798) ; v1(102.8,12.4) U27.E5@103.2,12 ; v1(104.8,7.6) U27.C1@105.2,8 ; U27.B3@106.2,10 v1(106.6,10.4) ; v1(140.725,19.75) U18.D9@141.05,20.075 ; v1(140.725,21.05) U18.D8@141.05,20.725 ; v1(140.725,21.7) U18.D7@141.05,21.375 ; v1(140.725,22.35) U18.D6@141.05,22.025 ; v1(140.725,23) U18.D5@141.05,22.675 ; v1(142.025,17.8) U18.F12@142.35,18.125 ; v1(142.025,24.95) U18.F2@142.35,24.625 ; U18.F10@142.35,19.425 v1(142.675,19.75) ; U18.F6@142.35,22.025 v1(142.675,21.7) ; v1(142.675,17.8) U18.G12@143,18.125 ; v1(142.675,24.95) U18.G2@143,24.625 ; U18.G6@143,22.025 v1(142.675,21.7) ; v1(143.325,17.8) U18.H12@143.65,18.125 ; U18.K10@144.95,19.425 v1(144.625,19.75) ; U18.K6@144.95,22.025 v1(144.625,21.7) ; U18.M9@146.25,20.075 v1(146.575,19.75) ; U18.M8@146.25,20.725 v1(146.575,20.4) ; U18.M1@146.25,25.275 v1(146.575,25.6) ; U18.N1@146.9,25.275 v1(147.225,25.6) ; v1(152.85,18.775) U22.3@153.5,18.775 ; v1(142.675,19.75) U18.G9@143,20.075 ; v1(142.675,19.75) U18.G10@143,19.425 v1(143.325,19.75) ; v1(142.675,19.75) U18.F9@142.35,20.075 v1(142.675,20.4) ; v1(142.675,20.4) U18.G9@143,20.075 ; v1(142.675,20.4) U18.F8@142.35,20.725 v1(142.675,21.05) ; v1(142.675,20.4) U18.G8@143,20.725 ; v1(142.675,21.05) U18.G8@143,20.725 ; v1(142.675,21.05) U18.F7@142.35,21.375 v1(142.675,21.7) ; v1(142.675,21.05) U18.G7@143,21.375 ; v1(142.675,21.7) U18.G7@143,21.375 ; U18.G9@143,20.075 v1(143.325,20.4) ; U18.G8@143,20.725 v1(143.325,21.05) ; U18.G8@143,20.725 v1(143.325,20.4) ; U18.G7@143,21.375 v1(143.325,21.7) ; U18.G7@143,21.375 v1(143.325,21.05) ; v1(143.325,19.75) U18.H10@143.65,19.425 v1(143.975,19.75) ; v1(143.325,19.75) U18.H9@143.65,20.075 ; v1(143.325,20.4) U18.H9@143.65,20.075 ; v1(143.325,20.4) U18.H8@143.65,20.725 ; v1(143.325,21.05) U18.H8@143.65,20.725 ; v1(143.325,21.05) U18.H7@143.65,21.375 ; v1(143.325,21.7) U18.H7@143.65,21.375 ; v1(143.325,21.7) U18.H6@143.65,22.025 v1(143.975,21.7) ; U18.H9@143.65,20.075 v1(143.975,19.75) ; U18.H9@143.65,20.075 v1(143.975,20.4) ; U18.H8@143.65,20.725 v1(143.975,20.4) ; U18.H8@143.65,20.725 v1(143.975,21.05) ; U18.H7@143.65,21.375 v1(143.975,21.05) ; U18.H7@143.65,21.375 v1(143.975,21.7) ; v1(143.975,19.75) U18.J9@144.3,20.075 ; v1(143.975,19.75) U18.J10@144.3,19.425 v1(144.625,19.75) ; v1(143.975,20.4) U18.J9@144.3,20.075 ; v1(143.975,20.4) U18.J8@144.3,20.725 ; v1(143.975,21.05) U18.J7@144.3,21.375 ; v1(143.975,21.05) U18.J8@144.3,20.725 ; v1(143.975,21.7) U18.J7@144.3,21.375 ; v1(143.975,21.7) U18.J6@144.3,22.025 v1(144.625,21.7) ; U18.J9@144.3,20.075 v1(144.625,20.4) ; U18.J9@144.3,20.075 v1(144.625,19.75) ; U18.J8@144.3,20.725 v1(144.625,21.05) ; U18.J8@144.3,20.725 v1(144.625,20.4) ; U18.J7@144.3,21.375 v1(144.625,21.7) ; U18.J7@144.3,21.375 v1(144.625,21.05) ; v1(144.625,19.75) U18.K9@144.95,20.075 v1(144.625,20.4) ; v1(144.625,20.4) U18.K8@144.95,20.725 v1(144.625,21.05) ; v1(144.625,21.05) U18.K7@144.95,21.375 v1(144.625,21.7)
  Bottom Layer w0.3: v1(2.8,15.05) 1.75,15.05 1.45,15.35 CN15.10@1.45,16.15 1.45,17.05 1.675,17.275 v1(2.8,17.275) ; CN15.5@4.125,14.85 4.95,14.85 5.637,14.163 U26.2@5.975,14.163 v1(5.975,13.575) ; U21.2@8.175,20.025 v1(8.175,20.725) ; LD5.2@9.175,43.025 v1(9.975,43.025) ; T1.2@14.25,18.025 14.4,17.875 R86.2@16.025,17.875 v1(16.7,17.875) ; CN8.5@15.83,69.314 v1(15.83,71.125) ; v1(16.525,59.55) U7.2@16.525,60.6 ; v1(16.875,8.575) C124.2@16.875,9.975 ; C124.2@16.925,9.55 16.925,10.825 ; v1(16.95,16.85) C120.1@17.675,16.85 ; v1(16.975,35.7) C94.1@17.8,35.7 ; v1(17,21.375) R81.2@17.675,21.375 ; CN8.7@17.1,69.314 v1(17.1,71.125) ; v1(17.5,18.875) C117.2@18.25,18.875 C118.2@18.25,18 ; v1(18.725,11.725) R95.2@18.725,12.425 ; C102.1@18.75,30.375 C101.1@19.7,30.375 ; X3.2@18.95,26.175 v1(19.975,26.175) ; U16.2@19.65,32.05 19.7,32 C101.1@19.7,30.375 ; v1(19.7,29.725) C101.1@19.7,30.375 ; v1(19.825,36.625) C92.1@20.6,36.625 ; v1(20.475,14.075) R101.1@21.175,14.075 ; R76.1@21.975,23.65 v1(21.975,24.3) ; C108.2@24.075,23.65 v1(24.075,24.3) ; C93.1@24.1,35.925 v1(24.1,36.8) ; R100.1@25.475,14.075 v1(26.175,14.075) ; U17.EP@25.5,33.275 U17.2@25.5,31.975 25.5,30.9 C100.1@25.55,30.85 v1(25.55,30.2) ; C111.2@26.1,23.025 v1(26.75,23.025) ; v1(29.225,14.625) R88.1@29.225,15.325 ; C96.1@29.325,34.575 v1(30.125,34.575) ; v1(31.9,49.375) C77.1@32.55,49.375 ; v1(32.475,44.725) C84.2@33.125,44.725 ; v1(32.475,45.625) C83.1@33.125,45.625 ; v1(32.475,46.5) C82.2@33.125,46.5 ; v1(32.475,47.4) C81.2@33.125,47.4 ; v1(32.475,48.275) C80.2@33.125,48.275 ; v1(32.95,53.225) R43.1@33.6,53.225 ; CN6.3@33.175,71 v1(35.125,71) ; v1(33.6,55.1) R34.2@33.6,55.825 ; U13.13@36.025,47.175 36.675,47.175 v1(36.95,47.45) ; v1(36.9,41.125) C88.1@36.9,41.75 ; U13.33@37.025,47.35 37.2,47.175 U13.7@37.2,44.5 ; C75.2@37.2,51.625 v1(37.2,52.275) ; v1(37.825,61.635) R27.1@37.825,62.6 ; v1(37.9,41.125) R57.2@37.9,41.75 ; C74.1@38.3,51.625 v1(38.3,52.275) ; C70.1@38.95,54.125 v1(39.6,54.125) ; C68.2@38.95,55 v1(39.6,55) ; C73.1@39.2,51.625 v1(39.2,52.275) ; U13.28@40.875,47.175 v1(41.6,47.175) ; R44.1@40.875,51.625 v1(40.875,52.275) ; C72.2@43.35,52.025 v1(43.35,52.675) ; C78.1@44.875,48.9 44.9,48.925 v1(45.55,48.925) ; C76.1@44.875,49.8 v1(45.525,49.8) ; CN5.3@45.9,71 v1(47.85,71) ; R35.1@46.575,55.6 v1(47.225,55.6) ; CN4.12@51.225,72.55 v1(52.65,72.55) ; CN4.13@51.325,61.55 v1(52.75,61.55) ; U9.8@57.1,55.655 U9.3@57.1,56.475 v1(57.1,57.15) ; v1(59.575,55.725) C66.2@59.575,56.425 ; v1(61.7,58.15) CN4.6@61.7,59.4 ; U10.8@62.45,55.65 U10.3@62.45,56.47 v1(62.45,57.145) ; v1(64.75,72.55) CN4.11@66.175,72.55 ; v1(64.9,61.05) CN4.14@66.325,61.05 ; v1(65.05,58.15) CN4.9@65.05,59.4 ; CN7.1@80.654,69.45 v1(80.654,70.471) ; CN7.14@87.154,69.45 v1(87.154,70.471) ; CN7.16@88.154,69.45 v1(88.154,70.471) ; U15.M1@90.175,25.598 90.475,25.598 92.024,24.049 92.024,23.792 92.725,23.091 92.475,22.841 v1(92.475,22.823) 92.475,22.773 93.15,22.098 v1(94.225,22.098) ; v1(90.575,31.598) 90.575,31.62 91.053,32.098 91.625,32.098 92.775,33.248 93.125,33.248 ; v1(91.3,33.298) 92,33.998 92,36.573 v1(92.7,37.273) 92.925,37.498 v1(94.525,37.498) C91.1@95.125,37.498 v1(95.125,38.098) 95.5,38.473 v1(96.675,38.473) v1(97.85,38.473) 98.2,38.123 v1(98.2,36.586) v1(98.2,35.048) 98.475,34.773 ; CN7.23@91.654,69.45 v1(91.654,70.471) ; v1(91.7,27.548) 91.7,27.325 92.802,26.223 SB39.1@93.5,26.223 ; v1(93.5,25.123) SB39.1@93.5,26.223 ; C90.1@93.65,39.5 93.65,41.498 R58.1@93.75,41.598 v1(94.875,41.598) ; v1(93.775,47.6) 94.1,47.925 C79.2@95.6,47.925 ; C99.1@94.45,32.548 v1(94.45,33.248) ; CN7.29@94.654,69.45 94.654,68.554 94.4,68.3 94.4,67.125 94.575,66.95 C63.1@95.15,66.95 95.725,66.375 C64.1@96.3,66.375 96.55,66.125 v1(96.55,65.531) ; v1@95.2,25.648 95.475,25.373 95.925,25.373 95.65,25.098 ; C105.1@95.575,28.473 v1(96.275,28.473) ; C103.1@95.575,29.373 v1(96.275,29.373) ; X4.2@96.2,24.248 95.55,24.898 v1@95.45,24.898 ; X4.4@97.25,22.898 v1(97.25,22.048) ; v1(100.525,31.248) C97.1@100.525,31.948 v1(101.4,31.948) 101.85,31.948 102.15,32.248 102.15,34.598 101.975,34.773 v1(101.375,34.773) 98.475,34.773 ; v1(120.175,23.45) C112.1@120.175,22.775 120.75,22.2 C113.2@121.4,22.2 121.45,22.25 U19.2@122.875,22.25 ; U29.3@120.45,7.575 v1(120.45,8.4) ; U5.1@122.861,42.485 v1(124.585,42.485) ; U5.3@122.861,44.485 v1(124.585,44.485) ; U5.12@122.861,53.485 v1(124.585,53.485) ; C115.1@126.675,19.9 126.85,19.725 126.9,19.775 v1(127.825,19.775) C116.2@127.825,20.4 ; C121.1@127.125,15.325 v1(127.125,16) ; C109.1@127.375,23.2 v1(128.05,23.2) ; v1(129.525,18.075) C119.2@129.525,17.4 129.575,17.35 U24.2@129.575,15.95 ; v1(130.525,10.825) R105.2@130.525,11.5 ; v1(136.225,28.5) C106.2@136.9,28.5 ; X2.2@140.85,28.75 v1(140.85,29.6) ; C122.1@141.225,14.4 v1(141.225,15) ; v1(142.5,28.925) C104.2@143.175,28.925 ; R98.1@143.275,13.5 v1(143.275,12.85) 144.425,12.85 C123.1@144.5,12.925 ; v1(145.225,11.925) U28.2@145.863,11.925 ; v1(145.25,6.85) U30.2@145.863,6.85 ; R69.1@145.925,27.8 146,27.725 v1(147.825,27.725) ; v1(146.138,43.485) U5.43@147.861,43.485 ; v1(146.138,45.485) U5.41@147.861,45.485 ; v1(146.138,53.485) U5.33@147.861,53.485 ; v1(146.138,56.485) U5.30@147.861,56.485 ; R82.1@151,21.1 v1(151.675,21.1) ; R73.2@151,24.275 v1(151.675,24.275) ; v1(153.025,21.775) C114.1@153.7,21.775 153.6,21.675 153.6,20.55 D4.2@153.5,20.45 ; v1(155.65,16.4) CN14.5@156.85,16.4 ; CN14.8@159.55,14.2 CN14.11@159.55,16.7 CN14.10@159.55,18.7 CN14.9@159.55,21.2 ; 93.125,33.248 93.1,33.273 93.1,34.473 93.475,34.848 93.75,34.573 v1(94.45,34.573) 94.85,34.573 C95.1@95.125,34.848 v1(95.125,34.248) 95.125,33.298 95.175,33.248 ; 93.125,33.248 v1(94.45,33.248) ; SB39.1@93.5,26.223 94.9,26.223 95.125,25.998 v1(95.125,25.573) ; v1(94.225,22.098) 94.225,22.023 94.675,21.573 v1(95.125,21.573) ; v1(94.225,22.098) 94.975,22.098 C110.1@95.125,22.248 v1(95.125,21.573) ; v1(94.45,33.248) 95.175,33.248 ; v1(95.125,21.573) 96.775,21.573 v1(97.25,22.048) ; v1(95.125,25.573) C107.1@95.125,24.898 95,25.023 v1(94.45,25.023) 94.45,25.348 94.675,25.573 v1(95.125,25.573) ; 95.175,33.248 96.55,33.248 v1(96.625,33.323) ; v1@95.45,24.898 95.65,25.098 ; v1@95.45,24.898 v1(95.35,24.898) 95.55,25.098 95.65,25.098 ; 95.65,25.098 97.9,25.098 98.15,24.848 98.15,22.323 97.875,22.048 v1(97.25,22.048) ; v1(96.625,33.323) C98.1@97.45,33.323 v1(97.45,34.023) ; v1(96.625,33.323) 96.625,33.873 96.775,34.023 v1(97.45,34.023) ; v1(97.45,34.023) 97.725,34.023 98.475,34.773
  Bottom Layer w0.5: CN16.2@37.89,12.95 v1@37.89,15.795 ; v1(74.75,42.548) C85.2@74.75,43.173 ; C86.2@78.875,42.273 78.875,41.873 79.05,41.698 v1(79.6,41.698) C89.1@80.375,41.698
  other v1: 153.95,1.1 1.85,1.725 18.025,2.8 52.975,4.2 32.325,4.275 116.975,4.35 144.725,4.375 9.525,5.05 44.75,5.7 39.45,5.975 29.05,6.025 130.625,6.075 124.05,6.775 111.2,7.25 75.2,7.7 11.275,7.975 158.5,8.725 30.925,9.075 3.5,10.6 117,10.725 63.65,11.575 111.275,12.625 67.15,12.65 96.225,12.825 154.4,12.875 13.5,12.95 49.125,12.975 18.85,14.5 13.475,14.975 37.885,15.8 31.175,15.9 15.325,16.625 21.825,17.05 22.825,17.05 23.85,17.05 24.775,17.05 111.325,17.925 21.825,18.05 22.825,18.05 23.85,18.05 24.775,18.05 10.25,18.25 38.6,18.85 21.825,18.975 22.825,18.975 23.85,18.975 24.775,18.975 134.775,19.85 22.825,19.975 23.825,19.975 24.775,19.975 21.825,20 45.75,21.125 30.225,21.875 109.975,22.825 1.85,22.95 135.425,24.775 157.9,25.75 34.75,26.05 24.7,26.6 131.7,26.8 125.625,28.375 5.95,28.55 39.95,29.175 29.825,29.275 45.775,29.4 107.2,30.35 34.95,30.75 114.9,31.525 1.5,32.2 133.35,32.7 149.125,32.925 42.025,33.45 22.125,33.825 120.3,34.3 36.9,35.55 127.65,36.65 47.95,36.675 6.85,36.725 107.95,36.75 31.9,39.4 158.675,40.825 21.9,41.625 154.25,42.225 108.95,42.9 16.55,43.2 143.9,43.65 120.825,43.75 25.1,44.675 132.475,45 38,45.4 39.05,45.4 39.95,45.4 36.95,45.425 1.75,46.025 17.51,46.06 20.05,46.06 30.4,46.25 36.95,46.45 38,46.45 39.05,46.45 39.95,46.45 10.3,46.65 38,47.45 39.05,47.45 39.95,47.45 109,48.175 36.95,48.425 38,48.425 39.025,48.425 39.925,48.425 53.875,49.25 15.575,50.4 1.85,51.025 157.975,51.975 17.15,52.2 24.675,52.2 108.375,53.05 129,53.075 46,53.25 10.025,54.05 30.675,54.875 22.625,56.175 12.575,56.45 51.875,57.1 137.75,57.925 127.675,57.95 154.1,58 24.425,58.075 121.225,58.475 6.15,58.525 2.55,59.375 99.675,61.025 158.825,61.2 129.65,61.375 144.675,61.4 8.65,61.425 5.05,61.7 2.475,62 108.65,62.85 25.075,64.075 2.45,65.475 152.4,66.25 8.275,66.4 47.225,66.4 43.325,66.8 36.375,67.175 16.625,67.3 54.375,68.6 23.875,68.8 9.475,69.8 117.5,70.35 112.65,70.575 9.425,72.575 15.975,72.9 150.1,73.025 55.75,73.45 159.8,73.6 25.05,73.65 121.425,73.775 19.9,74.125
GNDDetect: CN8.11 R23.2 U18.K13 | length 232.7
  Signal Layer 4 w0.3: v1(18.75,71.6) 18.75,73.075 17.675,74.15 1.125,74.15 0.75,73.775 0.75,58.5 1.25,58 3.225,58 4.25,56.975 13.858,56.975 19.33,51.502 19.33,42.52 28.238,33.612 29.063,33.612 48.266,14.409 83.67,14.409 85.349,12.73 87.73,12.73 88.9,13.9 104.8,13.9 106.045,15.145 106.045,26.002 110.242,30.2 132.95,30.2 136.725,26.425 136.725,17.15 137.325,16.55 144.697,16.55 145.275,17.128 v1(145.275,17.15)
  Bottom Layer w0.2: U18.K13@144.95,17.475 v1(145.275,17.15)
  Bottom Layer w0.3: v1(18.75,71.6) R23.2@19.65,71.6 19.64,71.59 CN8.11@19.64,69.314
I2C4_SCL: CN1.40 CN7.28 CN10.10 CN16.6 P1.7 R56.1 SB55.1 U5.5 U13.3 U15.L15 | length 278.7
  Top Layer w0.1: v1(38.95,43.325) 39.4,42.875 40.905,42.875 42.975,40.805 v1(42.975,15.4) 42.975,13.725 45.375,11.325 v1(55.475,11.325) ; v1(71.6,71.35) 71.61,71.34 CN1.40@71.61,69.217 ; v1(96.5,3.2) 97.425,4.125 97.425,13 99.725,15.3 99.725,25.1 100.15,25.525 100.15,31.093 100.15,40.325 100.664,40.839 CN10.10@100.664,52.6 ; v1@111.82,71.1 111.82,66.49 P1.7@112.82,65.49
  Signal Layer 2 w0.1: v1(55.475,11.325) 55.475,12.725 56.175,13.425 58.575,13.425 71.225,26.075 v1(73.3,26.075) ; v1(71.6,71.35) 75.645,71.35 75.895,71.1 v1(94.15,71.1) v1(107.375,71.1) v1(111.825,71.1) ; CN10.10@100.664,52.6 100.664,59.164 103.8,62.3 111.95,62.3 112.82,63.17 P1.7@112.82,65.49
  Bottom Layer w0.1: R56.1@38.825,42.65 R56.1@38.95,42.65 v1(38.95,43.325) 39.2,43.575 U13.3@39.2,44.5 ; CN16.6@42.97,12.95 42.975,12.955 v1(42.975,15.4) ; SB55.1@55.475,8.975 v1(55.475,11.325) 56.075,11.925 62.058,11.925 68.393,5.59 89.693,5.59 90.23,5.053 90.23,3.078 90.483,2.825 95.55,2.825 95.925,3.2 v1(96.5,3.2) ; v1(73.3,26.075) 75.75,26.075 76.433,25.392 77.583,25.392 78.589,26.398 U15.L15@78.975,26.398 ; v1(94.15,71.1) 94.15,69.454 CN7.28@94.154,69.45 ; CN10.10@100.664,52.6 106.779,46.485 U5.5@122.861,46.485
I2C4_SDA: CN1.38 CN7.27 CN10.9 CN16.8 P1.10 R55.1 SB53.1 U5.4 U13.2 U15.K11 | length 285.7
  Top Layer w0.1: v1(40.025,43.3) 42.75,43.3 44.245,41.805 44.245,16.67 v1(45.515,15.4) 45.515,12.885 46.625,11.775 58.05,11.775 v1(58.5,11.325) ; v1(70.325,24.3) 70.975,24.3 71.302,23.973 75.183,23.973 75.184,23.975 77.519,23.975 79.367,25.823 80.452,25.823 81.052,26.423 81.93,26.423 82.305,26.798 v1(82.575,26.798) ; v1(72.85,70.975) 72.85,69.437 72.97,69.317 72.875,69.222 CN1.38@72.88,69.217 ; v1(96.025,2.625) 96.025,3.45 97.225,4.65 97.225,13.083 99.475,15.333 99.475,25.725 99.717,25.967 99.717,40.175 100.464,40.922 100.464,50.26 CN10.9@98.124,52.6 ; P1.10@118.82,65.49 119.85,66.52 119.85,68.376 119.6,68.626 v1(119.6,69.925)
  Signal Layer 2 w0.1: v1(58.5,11.325) 58.5,13.067 69.733,24.3 v1(70.325,24.3) ; v1(72.85,70.975) 75.6,70.975 76.6,69.975 92.3,69.975 92.975,70.65 v1(93.675,70.65) ; CN10.9@98.124,52.6 98.124,58.301 96.775,59.65 96.775,64.575 94.375,66.975 94.375,69.225 93.675,69.925 v1(93.675,70.65) ; v1(119.6,69.925) 112.65,69.925 111.925,70.65 v1(93.675,70.65)
  Bottom Layer w0.1: U13.2@39.7,44.5 39.7,43.625 v1(40.025,43.3) R55.1@40.025,42.65 R55.1@40.1,42.65 ; CN16.8@45.515,12.955 v1(45.515,15.4) ; SB53.1@58.5,8.975 v1(58.5,11.325) 58.9,11.725 61.975,11.725 68.31,5.39 89.46,5.39 90.03,4.82 90.03,3.905 90.025,3.9 90.025,3 90.4,2.625 95.95,2.625 v1@95.975,2.6 ; U15.K11@82.175,27.198 v1(82.575,26.798) ; CN7.27@93.654,69.45 93.675,69.471 v1(93.675,70.65) ; CN10.9@98.124,52.6 105.239,45.485 U5.4@122.861,45.485
I2S6_CK: R52.2 U15.D8 | length 63.1
  Signal Layer 2 w0.1: v1(84.531,39.523) 84.875,39.523 85.258,39.906 85.258,47.833 v1(85.975,48.55)
  Signal Layer 4 w0.1: v1(84.531,39.523) 84.225,39.218 84.225,36.404 84.575,36.054 84.575,32.798 v1(84.975,32.398)
  Bottom Layer w0.1: R52.2@44.875,42.6 45.525,42.6 47.175,44.25 47.175,46.875 48.05,47.75 82.95,47.75 83.475,48.275 85.7,48.275 v1(85.975,48.55) ; U15.D8@84.575,31.998 v1(84.975,32.398)
I2S6_MCK: R48.2 SB46.2 | length 78.3
  Top Layer w0.1: v1(45.525,45.8) 47.125,44.2 v1(47.125,12.35)
  Bottom Layer w0.1: R48.2@44.875,45.8 v1(45.525,45.8)
  Bottom Layer w0.127: v1(47.125,12.35) 50.273,12.35 50.537,12.614 64.486,12.614 68.036,9.063 76.889,9.063 77.5,9.675 83.7,9.675 83.85,9.525 87.125,9.525 v1(87.575,9.975) SB46.2@87.575,10.95
I2S6_SDI: R47.2 U15.C8 | length 91.7
  Top Layer w0.1: v1(45.525,46.875) 44.825,46.175 44.825,16.7 46.25,15.275 v1(46.25,15.25)
  Signal Layer 2 w0.1: v1(83.025,13.523) 83.025,21.65 84.55,23.175 84.55,32.773 v1(84.975,33.198)
  Bottom Layer w0.1: R47.2@44.875,46.875 v1(45.525,46.875) ; v1(46.25,15.25) 46.896,14.604 81.944,14.604 v1(83.025,13.523) ; U15.C8@84.575,32.798 v1(84.975,33.198)
I2S6_SDO: R60.2 U15.A7 | length 87.4
  Top Layer w0.1: v1(45.529,40.523) 46.675,39.377 v1(46.675,14.25)
  Signal Layer 2 w0.1: v1(82.647,12.878) 82.647,13.875 82.716,13.944 82.716,21.766 84.35,23.4 84.35,34.173 v1(84.975,34.798)
  Bottom Layer w0.1: R60.2@44.879,40.523 v1(45.529,40.523) ; v1(46.675,14.25) 81.275,14.25 v1(82.647,12.878)
  Bottom Layer w0.127: v1(84.975,34.798) U15.A7@85.375,34.398
I2S6_WS: R54.2 SB31.2 | length 1.4
  Bottom Layer w0.1: SB31.2@41.1,40.375 R54.2@41.1,41.75
JTCK: CN8.6 CN9.1 R32.1 R41.2 U7.3 U15.B13 | length 98.4
  Top Layer w0.1: v1(13.875,52.4) 13.875,50.8 14.625,50.05 R41.2@14.625,49.825
  Signal Layer 2 w0.1: v1(13.875,52.4) 13.875,46.1 15.025,44.95 21.142,44.95 23.717,42.375 47.65,42.375 48.275,43 v1(48.85,43) ; v1(77.875,35.15) 78.2,34.825 78.2,34.643 78.2,34.154 78.2,33.825 78.502,33.523 79.7,33.523 v1(80.175,33.998)
  Bottom Layer w0.1: v1@13.85,52.45 13.85,56.595 CN9.1@15.03,57.775 15.03,58.93 15.875,59.775 U7.3@15.875,60.6 ; R32.1@14.575,60.6 U7.3@15.875,60.6 ; CN8.6@15.83,65.25 15.83,63.595 16.325,63.1 16.325,61.475 15.875,61.025 U7.3@15.875,60.6 ; v1(48.85,43) 70.917,43 77.875,36.042 v1(77.875,35.15) ; v1(80.175,33.998) U15.B13@80.575,33.598
JTDI: R36.2 U15.C12 | length 85.8
  Top Layer w0.1: v1(7.375,45.55) 7.375,45.025 7.5,44.9 R36.2@7.725,44.9
  Signal Layer 2 w0.1: v1(7.375,45.55) 10.15,45.55 11.55,44.15 21.65,44.15 23.65,42.15 47.35,42.15 47.65,41.85 49.475,41.85 50.175,42.55 50.175,43.525 49.95,43.75 v1(48.85,43.75) ; v1(78.95,35.975) 79.6,35.975 80.949,34.626 80.949,33.224 v1(80.975,33.198)
  Bottom Layer w0.1: v1(48.85,43.75) 71.175,43.75 v1(78.95,35.975) ; v1(80.975,33.198) U15.C12@81.375,32.798
JTDO/TRACESWO: CN8.8 R31.1 R37.2 U7.1 U15.C6 | length 110.5
  Top Layer w0.1: R37.2@14.6,51.2 v1(14.6,52.05)
  Signal Layer 2 w0.1: v1(14.6,52.05) 14.825,51.825 18.075,51.825 20.9,49 43.475,49 43.825,49.35 46.25,49.35 v1(48.875,46.725) ; v1(86.575,33.198) 86.575,35.048 87.095,35.568 87.095,38.7 87.705,39.31 87.705,45.955 89.125,47.375 v1(89.125,47.875)
  Bottom Layer w0.1: v1(14.6,52.05) 14.6,55.15 16.375,56.925 16.375,58.375 17.175,59.175 U7.1@17.175,60.6 ; CN8.8@17.1,65.25 17.1,63.625 16.7,63.225 16.7,61.5 17.175,61.025 U7.1@17.175,60.6 ; R31.1@18.425,60.6 U7.1@17.175,60.6 ; v1(48.875,46.725) 48.975,46.825 88.075,46.825 v1(89.125,47.875) ; U15.C6@86.175,32.798 v1(86.575,33.198)
JTMS: CN8.4 CN9.2 R30.1 R40.2 U7.4 U15.E12 | length 99.4
  Top Layer w0.1: R40.2@14.65,48.475 v1(15.425,48.475) ; v1(15.3,61.375) 15.3,60.045 CN9.2@17.57,57.775
  Signal Layer 2 w0.1: v1(15.425,48.475) 14.741,47.791 14.741,45.516 15.108,45.15 21.225,45.15 23.775,42.6 47,42.6 47.775,43.375 v1(49.675,43.375) ; v1(79.375,34.825) 79.802,34.398 80.325,34.398 80.575,34.148 80.575,31.998 v1(80.975,31.598)
  Bottom Layer w0.1: CN8.4@14.56,65.25 14.56,63.615 14.9,63.275 15.35,63.275 15.875,62.75 U7.4@15.875,62.3 ; R30.1@14.575,62.3 U7.4@15.875,62.3 ; v1(15.3,61.375) 15.875,61.95 U7.4@15.875,62.3 ; v1(15.425,48.475) 16.5,49.55 16.5,54.6 17.57,55.67 CN9.2@17.57,57.775 ; v1(49.675,43.375) 70.825,43.375 v1(79.375,34.825) ; v1(80.975,31.598) U15.E12@81.375,31.198
LCD_B0: CN1.21 U15.E9 | length 88.2
  Top Layer w0.127: CN1.21@83.04,65.531 83.04,59.21 84.35,57.9 84.35,48.65 84.839,48.161 86.736,48.161 87.975,49.4 98.95,49.4 99.025,49.325 99.025,49.125 98.925,49.025 88.075,49.025 87.975,48.925 87.975,48.725 88.075,48.625 98.925,48.625 99.025,48.525 99.025,48.35 98.938,48.264 87.414,48.264 86.9,47.75 v1(84.35,47.75)
  Signal Layer 2 w0.1: v1(83.525,36.423) 84.1,36.998 84.1,39.869
  Signal Layer 2 w0.102: 84.1,39.869 84.1,40.177 84.249,40.326 84.249,40.329 84.35,40.43 v1(84.35,47.75)
  Signal Layer 4 w0.1: v1(83.375,31.598) 84.075,32.298 84.075,35.873 v1(83.525,36.423)
  Bottom Layer w0.127: v1(83.375,31.598) U15.E9@83.775,31.198
LCD_B1: CN1.23 U15.D9 | length 89.4
  Top Layer w0.127: CN1.23@81.77,65.531 82.044,65.257 81.625,65.257 81.625,55.375 81.55,55.3 81.35,55.3 81.275,55.375 81.275,64.175 81.175,64.275 80.975,64.275 80.881,64.181 80.881,54.85 80.992,54.739 81.814,54.739 81.975,54.9 81.975,58.825 82.061,58.912 82.288,58.912 82.35,58.85 82.35,53.825 82.45,53.725 82.625,53.725 82.725,53.825 82.725,58.575 82.825,58.675 83.036,58.675 83.125,58.586 83.125,54.575 83.25,54.45 83.45,54.45 83.55,54.55 83.55,57.725 83.656,57.831 83.881,57.831 83.969,57.742 83.969,54.419 83.55,54 83.55,53.45 83.95,53.05 83.95,49.525 83.825,49.4 83.5,49.4 83.4,49.5 83.4,51.35 83.3,51.45 83.075,51.45 83,51.375 83,50.15 82.925,50.075 82.75,50.075 82.625,50.2 82.625,50.9 82.55,50.975 82.325,50.975 82.225,50.875 82.225,49.989 83.575,48.639 v1(83.575,47.775)
  Signal Layer 2 w0.1: 83.1,40.041 83.1,39.518 83.37,39.248 83.655,39.248 83.9,39.003 83.9,37.598 v1(83.525,37.223) ; 83.1,40.043 83.575,40.518
  Signal Layer 2 w0.102: 83.1,40.041 83.1,40.043 ; 83.575,40.518 83.575,46.992 v1(83.575,47.775)
  Signal Layer 4 w0.1: v1(83.375,32.398) 82.975,32.798 82.975,36.673 v1(83.525,37.223)
  Bottom Layer w0.127: v1(83.375,32.398) U15.D9@83.775,31.998
LCD_B2: CN1.25 U15.C9 | length 85.5
  Top Layer w0.127: CN1.25@80.5,65.531 80.5,54.075 80.425,54 80.075,54 80,54.075 80,58.375 79.888,58.486 79.711,58.486 79.611,58.386 79.611,53.725 79.673,53.663 81.486,53.663 81.575,53.575 81.575,51.85 81.261,51.536 79.761,51.536 79.611,51.386 79.611,51.15 79.711,51.05 80.75,51.05 80.85,50.95 80.85,50.775 80.75,50.675 79.7,50.675 79.611,50.586 79.611,50.4 79.711,50.3 81.775,50.3 81.844,50.231 81.844,50 81.744,49.9 79.975,49.9 79.875,49.8 79.875,49.614 79.97,49.519 82.156,49.519 82.75,48.925 v1(82.75,48.225)
  Signal Layer 2 w0.1: 82.006,39.848 82.006,38.444 82.15,38.3 82.65,38.3 82.725,38.375 v1(82.725,38.823)
  Signal Layer 2 w0.102: 82.006,39.848 82.006,48.131 82.1,48.225 82.275,48.225 82.35,48.15 82.35,40.589 82.489,40.45 82.645,40.45 82.75,40.555 v1(82.75,48.225)
  Bottom Layer w0.1: 82.725,35.539 82.725,35.248 83.275,34.698 83.275,33.298 U15.C9@83.775,32.798
  Bottom Layer w0.127: 82.725,35.539 82.725,37.45 82.242,37.933 82.242,40.917 82.4,41.075 84.775,41.075 84.875,40.975 84.875,40.825 84.75,40.7 82.775,40.7 82.65,40.575 82.65,40.45 82.75,40.35 84.05,40.35 84.15,40.25 84.15,40.1 84.062,40.012 82.662,40.012 82.575,39.925 82.575,39.675 82.625,39.625 83.025,39.625 83.1,39.55 83.1,39.198 v1(82.725,38.823)
LCD_B3: CN1.27 U15.B9 | length 86.5
  Top Layer w0.127: 79.225,51.825 78.936,51.536 77.136,51.536 76.987,51.387 76.987,50.787 77.163,50.611 79.139,50.611 79.23,50.52 79.23,50.355 79.15,50.275 77.9,50.275 77.807,50.182 77.807,49.968 77.875,49.9 79.375,49.9 79.494,49.781 79.494,49.6 79.394,49.5 78.2,49.5 78.1,49.4 78.1,49.225 78.187,49.138 81.812,49.138 v1(82.275,48.675) ; 79.23,51.825 79.23,53.45 79.016,53.663 77.017,53.663 76.931,53.75 76.931,53.981 77.05,54.1 78.225,54.1 78.325,54.2 78.325,54.4 78.225,54.5 77.8,54.5 77.7,54.6 77.7,54.761 77.864,54.925 79.08,54.925 79.23,55.075 CN1.27@79.23,65.531
  Signal Layer 2 w0.1: 80.931,39.848 80.931,38.594 81.502,38.023 v1(83.525,38.023) ; 81.3,39.848 81.3,38.7 81.425,38.575 81.6,38.575 81.7,38.675 81.7,39.848
  Signal Layer 2 w0.102: 80.931,39.848 80.931,50.341 81.04,50.45 81.2,50.45 81.3,50.35 81.3,39.848 ; 81.7,39.848 81.7,51.11 81.815,51.225 81.95,51.225 82.05,51.125 82.05,49.375 82.15,49.275 82.275,49.275 82.375,49.375 82.375,51.325 82.475,51.425 82.65,51.425 82.75,51.325 82.75,49.15 v1(82.275,48.675)
  Bottom Layer w0.1: 83.106,35.512 83.106,35.292 83.475,34.923 83.475,33.898 U15.B9@83.775,33.598
  Bottom Layer w0.127: 83.106,35.512 83.106,37.604 v1(83.525,38.023)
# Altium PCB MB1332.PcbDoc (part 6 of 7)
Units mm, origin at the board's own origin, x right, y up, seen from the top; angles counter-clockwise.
Board outline 161 x 75 mm, 6 copper layers (Top Layer, Signal Layer 1, Signal Layer 2, Signal Layer 3, Signal Layer 4, Bottom Layer), stack 1.57 mm thick; 387 components, 358 nets, 1659 pads, 1180 vias.

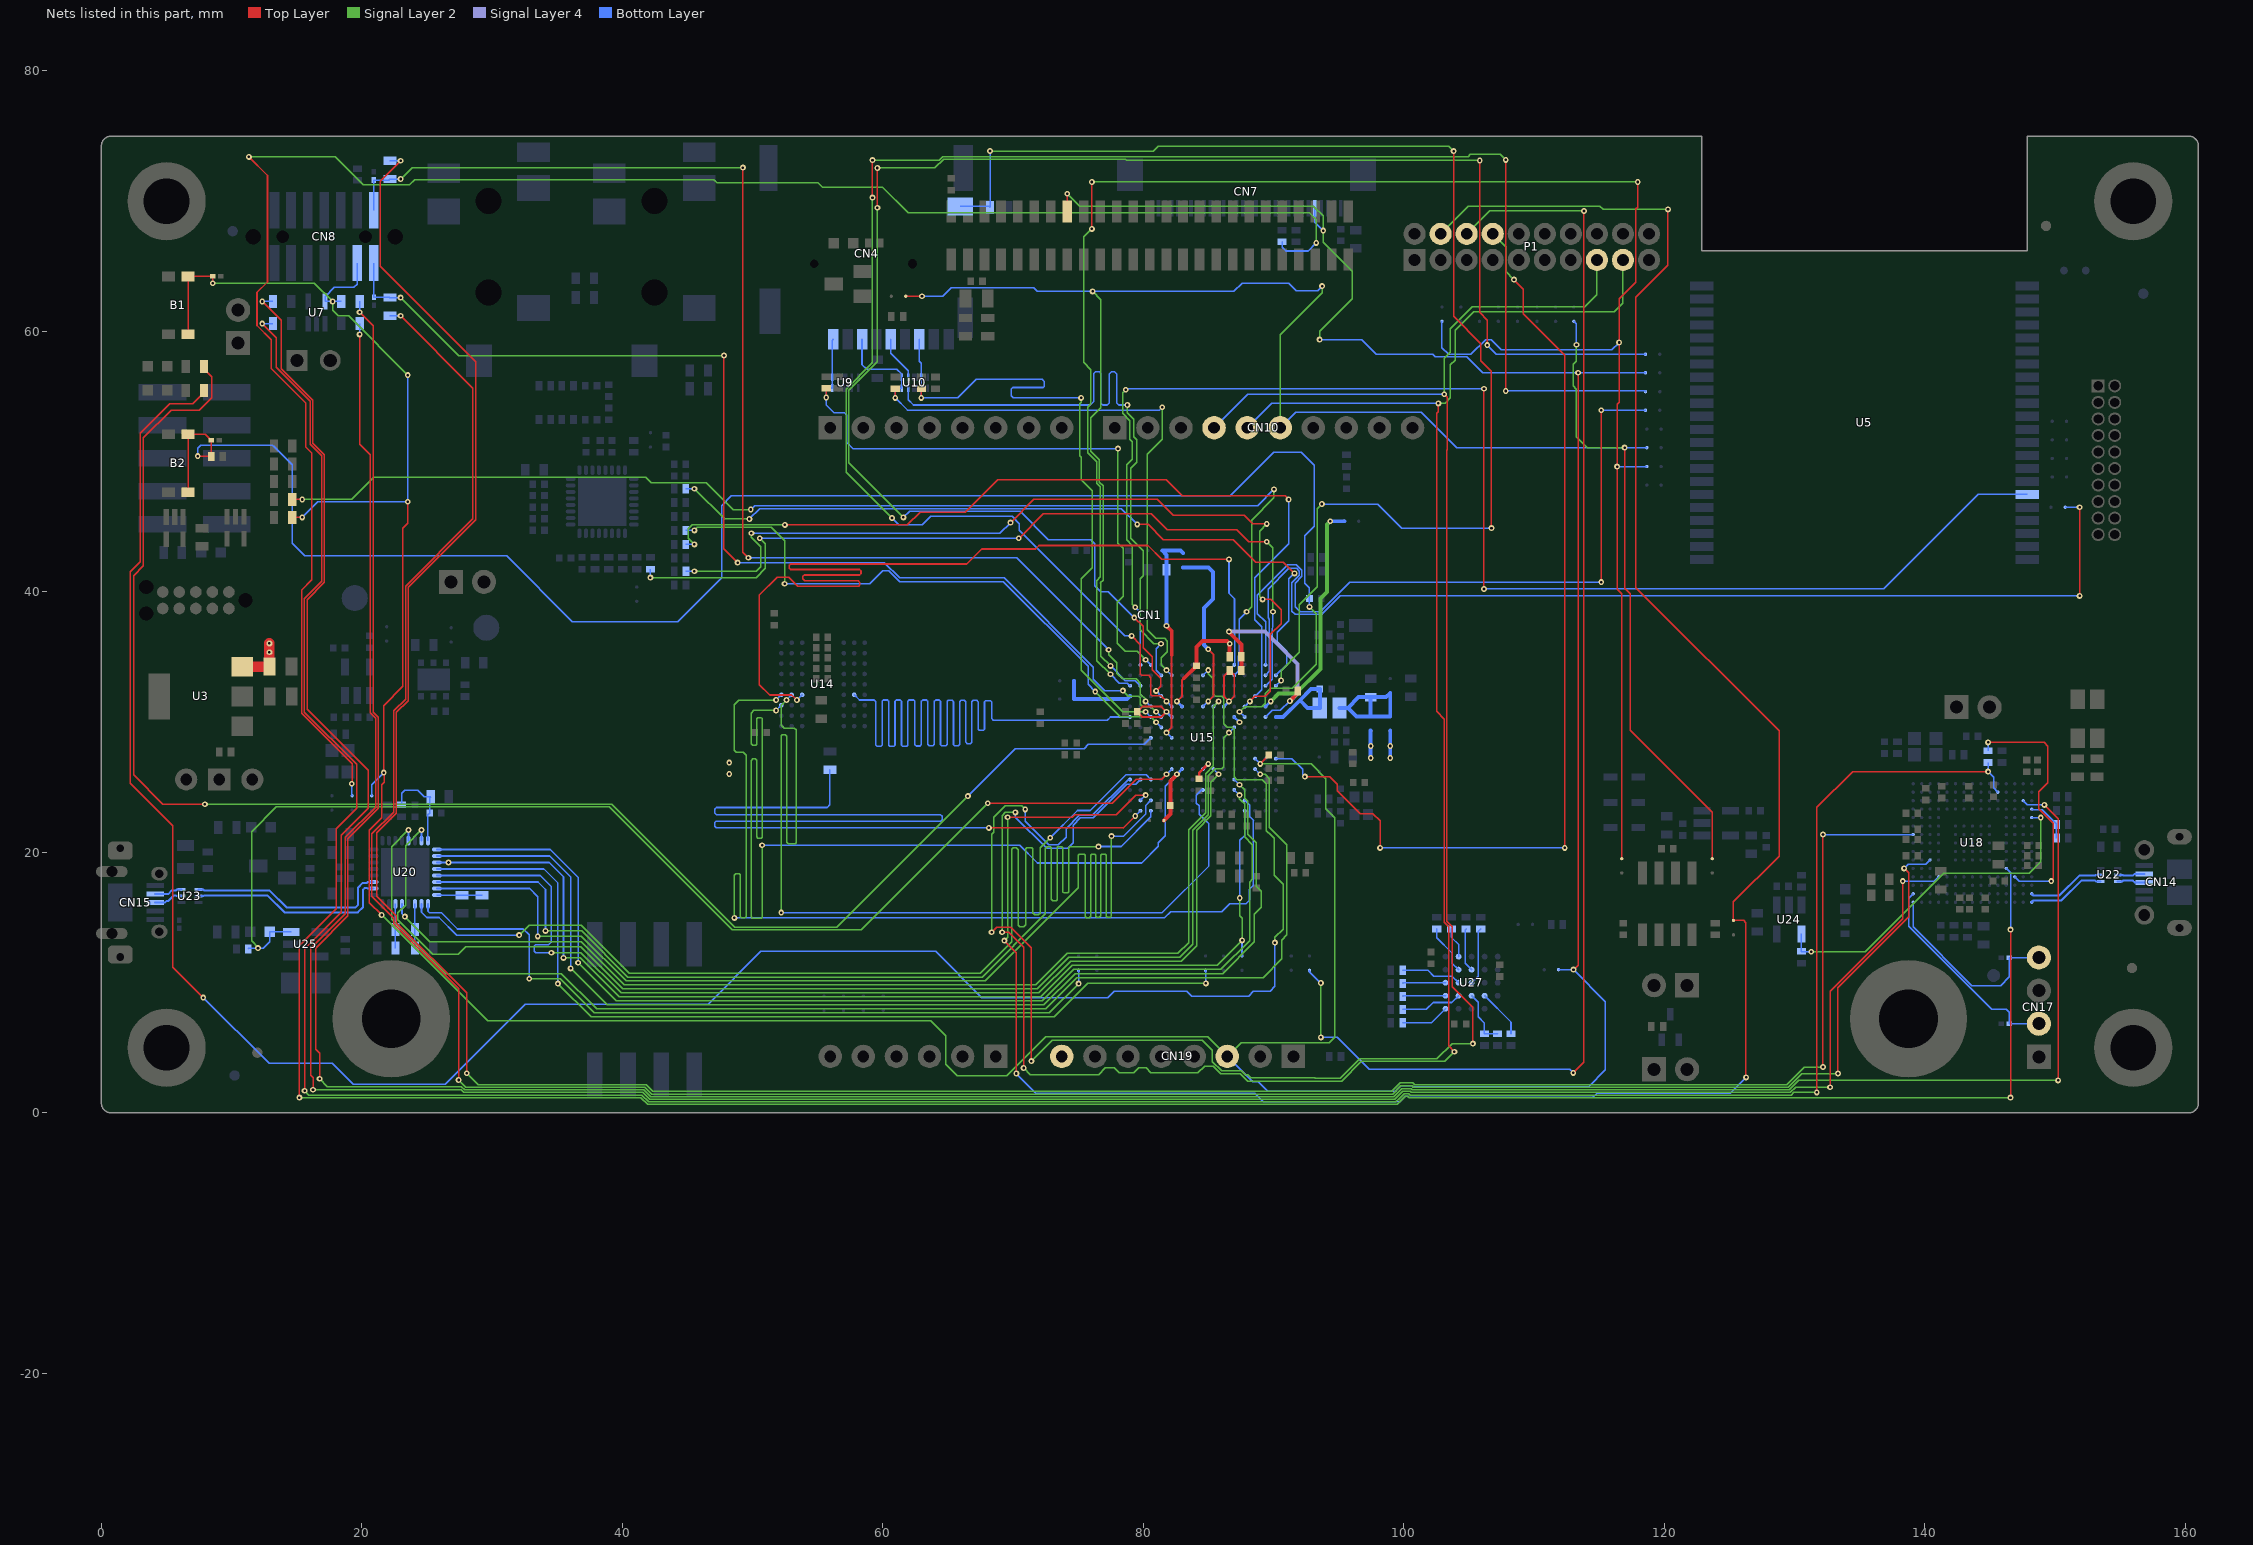
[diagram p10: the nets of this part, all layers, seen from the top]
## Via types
v1: diameter 0.45, hole 0.2, Top Layer to Bottom Layer, tented both sides, 1180 vias

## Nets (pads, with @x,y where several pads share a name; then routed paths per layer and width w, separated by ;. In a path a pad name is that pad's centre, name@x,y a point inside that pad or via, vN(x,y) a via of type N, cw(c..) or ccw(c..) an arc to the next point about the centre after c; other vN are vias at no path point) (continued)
NJTRST: R39.2 U15.B5 | length 93.3
  Top Layer w0.1: R39.2@14.65,47.1 v1(15.425,47.1)
  Signal Layer 2 w0.1: v1(15.425,47.1) 19.225,47.1 20.925,48.8 41.8,48.8 42.2,48.4 46.45,48.4 48.525,46.325 v1(49.85,46.325) ; v1(87.925,38.473) 88.315,38.863 88.315,45.509 90.025,47.219 v1(90.025,47.875)
  Bottom Layer w0.1: v1(49.85,46.325) 50.15,46.625 88.775,46.625 v1(90.025,47.875) ; U15.B5@86.975,33.598 87.275,33.898 87.275,35.048 87.367,35.141 87.367,37.916 v1(87.925,38.473)
NRST: B1.3 B1.4 C23.2 CN1.36 CN7.26 CN8.12 CN19.3 R29.1 R38.2 SB15.2 SB40.2 SB51.1 U1.1 U7.5 U15.K3 | length 342.9
  Top Layer w0.1: B1.3@6.65,59.775 B1.4@6.65,64.225 U1.1@8.538,64.225 8.55,64.213 v1(8.55,63.7) ; R38.2@14.65,45.725 v1(15.425,45.725) ; v1(21.519,15.2) 20.575,16.144 20.575,21.7 21.519,22.644 21.519,25.194 21.7,25.375 21.7,26.1 v1(21.675,26.125) 21.675,31.275 23.15,32.75 23.15,44.9 23.525,45.275 v1(23.525,46.925) ; CN1.36@74.15,69.217 v1(74.15,70.575) ; v1(88.975,26.798) 89.625,27.448 C23.2@89.625,27.473 ; v1(113.025,11) 113.375,11.35 v1(113.375,56.825)
  Signal Layer 2 w0.1: v1(8.55,63.7) 16.35,63.7 v1(17.75,62.3) 17.75,61.625 18.175,61.2 18.975,61.2 v1(23.525,56.65) ; v1(21.519,15.2) 29.649,7.07 63.68,7.07 64.825,5.925 64.825,3.75 65.725,2.85 69.5,2.85 72.5,5.85 84.93,5.85 CN19.3@86.44,4.34 87.5,5.4 94.25,5.4 94.675,5.825 94.675,22.675 94,23.35 94,25.669 92.87,26.798 v1(88.975,26.798) ; v1(74.15,70.575) 75.1,69.625 93.05,69.625 93.812,68.863 v1(93.812,67.737) 93.812,66.838 96.025,64.625 96.025,62.525 93.525,60.025 v1(93.525,59.375)
  Bottom Layer w0.1: v1(15.425,45.725) 16.625,46.925 v1@23.475,46.925 ; R29.1@18.425,62.3 v1(17.75,62.3) U7.5@17.175,62.3 17.175,62.675 17.875,63.375 19.375,63.375 19.64,63.64 CN8.12@19.64,65.25 ; SB40.2@20.75,24.35 20.75,25.2 v1(21.675,26.125) ; v1(23.525,46.925) v1(23.525,56.65) ; CN19.3@86.44,4.34 88.405,2.375 88.817,2.375 89.542,1.65 99.333,1.65 99.758,2.075 100.637,2.075 100.712,2 114.175,2 115.475,3.3 115.475,8.55 v1(113.025,11) SB51.1@111.875,11 ; U15.K3@88.575,27.198 v1(88.975,26.798) ; CN7.26@93.154,69.45 93.154,68.396 v1(93.812,67.737) ; v1(93.525,59.375) 96.75,59.375 97.862,58.262 102.213,58.262 102.425,58.05 104.825,58.05 106.05,56.825 v1(113.375,56.825) SB15.2@118.55,56.825
NSS: SB3.2 SB7.1 SB24.1 U15.C15 | length 155
  Top Layer w0.1: v1(76.05,67.875) v1(76.05,71.475) ; SB3.2@116.725,19.525 116.725,39.85 116.375,40.2 v1(116.375,49.625) 116.375,54.425 116.525,54.575 v1(116.525,59.15) 116.525,62.5 117.65,63.625 117.82,63.795 117.82,69.42 117.95,69.55 v1(117.95,71.475)
  Signal Layer 2 w0.1: v1(76.05,67.875) 75.425,67.25 75.425,57.625 75.975,57.075 75.975,54.444 75.717,54.186 75.717,50.697 76.425,49.989 76.425,48.351 76.7,48.076 76.7,41.15 76.425,40.875 76.425,34.725 v1(77.475,33.675) ; v1(76.05,71.475) v1(117.95,71.475)
  Bottom Layer w0.1: v1(77.475,33.675) 78.152,32.998 78.775,32.998 U15.C15@78.975,32.798 ; SB7.1@102.925,60.775 102.925,58.75 103.425,58.25 105.15,58.25 106.272,59.372 106.703,59.372 107.475,58.6 115.975,58.6 v1(116.525,59.15) ; v1(116.375,49.625) SB24.1@118.65,49.625
OCSPI1_CLK: R111.1 U27.B2 | length 3.8
  Bottom Layer w0.127: U27.B2@106.2,9 108.225,6.975 R111.1@108.225,6.075
OCSPI1_DQS: R91.1 U27.C3 | length 4.4
  Bottom Layer w0.127: U27.C3@105.2,10 105.7,10.5 105.7,13.925 R91.1@105.9,14.125
OCSPI1_IO0: R106.2 U27.D3 | length 4.7
  Bottom Layer w0.127: R106.2@99.9,10.95 101.85,10.95 102.3,10.5 103.7,10.5 U27.D3@104.2,10
OCSPI1_IO1: R109.2 U27.D2 | length 4.7
  Bottom Layer w0.127: R109.2@99.9,7.95 101.725,7.95 102.25,8.475 103.675,8.475 U27.D2@104.2,9
OCSPI1_IO2: R92.2 U27.C4 | length 3.4
  Bottom Layer w0.127: R92.2@104.775,14.125 104.7,14.05 104.7,11.5 U27.C4@105.2,11
OCSPI1_IO3: R94.2 U27.D4 | length 3.8
  Bottom Layer w0.127: R94.2@102.525,14.125 102.525,13.45 103.7,12.275 103.7,11.5 U27.D4@104.2,11
OCSPI1_IO4: R93.1 U27.D5 | length 2.4
  Bottom Layer w0.127: R93.1@103.65,14.125 103.65,13.475 104.2,12.925 U27.D5@104.2,12
OCSPI1_IO5: R107.1 U27.E3 | length 3.3
  Bottom Layer w0.127: R107.1@99.9,9.95 99.95,10 U27.E3@103.2,10
OCSPI1_IO6: R108.1 U27.E2 | length 3.3
  Bottom Layer w0.127: R108.1@99.9,8.95 99.95,9 U27.E2@103.2,9
OCSPI1_IO7: R110.2 U27.E1 | length 3.7
  Bottom Layer w0.127: R110.2@99.9,6.925 102.125,6.925 U27.E1@103.2,8
OCSPI1_NCS: R112.1 R113.2 U27.C2 | length 4.4
  Bottom Layer w0.127: U27.C2@105.2,9 105.7,8.5 105.7,7.375 106.175,6.9 R113.2@106.175,6.075 R112.1@107.2,6.075
OSC_24M: R26.1 SB41.2 | length 143.1
  Top Layer w0.127: v1(11.325,73.4) 12.75,71.975 12.75,63.8 11.95,63 11.95,60.45 13.05,59.35 13.05,57.15 15.7,54.5 15.7,51.125 16.161,50.664 16.161,40.933 15.375,40.146 15.375,30.675 19.25,26.8 v1@19.25,25.25
  Signal Layer 2 w0.127: v1(11.325,73.4) 17.95,73.4 20.1,71.25 23.65,71.25 24.05,71.65 47.025,71.65 47.263,71.412 55.013,71.412 55.361,71.064 59.975,71.064 61.939,69.1 92.75,69.1 93.275,68.575 v1(93.275,66.8)
  Bottom Layer w0.1: v1(19.225,25.275) 19.225,24.375 SB41.2@19.25,24.35
  Bottom Layer w0.127: R26.1@90.65,66.875 90.65,66.475 90.95,66.175 92.65,66.175 v1(93.275,66.8)
PA12: CN10.6 SB1.1 SB4.2 SB12.1 SB22.1 U15.C14 | length 155.6
  Top Layer w0.1: SB1.1@61.75,62.7 v1(63,62.7) ; v1(116.95,51.075) 116.95,40.275 117.362,39.863 117.362,29.388 123.675,23.075 SB4.2@123.675,19.525
  Signal Layer 2 w0.1: v1(76.1,63.075) 76.725,62.45 76.725,54.133 75.975,53.383 75.975,50.817 76.625,50.167 76.625,48.434 76.9,48.159 76.9,40.9 76.7,40.7 76.725,40.675 76.725,35.075 v1(77.475,34.325) ; CN10.6@90.504,52.6 90.504,59.735 93.725,62.956 v1(93.725,63.475) ; v1(113.25,58.975) 113.25,57.725 113,57.475 113,55.825 113.25,55.575 113.25,51.9 114.075,51.075 v1(116.95,51.075)
  Bottom Layer w0.1: v1(63,62.7) 64.6,62.7 65.25,63.35 71.575,63.35 71.845,63.08 86.813,63.08 86.825,63.067 86.942,63.067 87.575,63.7 91.175,63.7 91.75,63.125 93.375,63.125 v1(93.725,63.475) ; v1(77.475,34.325) 78.602,33.198 79.375,33.198 U15.C14@79.775,32.798 ; CN10.6@90.504,52.6 91.704,53.8 101.35,53.8 104.075,51.075 v1(116.95,51.075) SB22.1@118.65,51.075 ; SB12.1@113.05,60.775 113.25,60.575 v1(113.25,58.975)
PH8: P1.12 SB5.2 U15.P14 | length 182.8
  Top Layer w0.1: v1(69.325,13.225) 70.25,12.3 v1(70.25,3.025) ; v1(69.575,22.7) 74.55,22.7 74.748,22.898 77.925,22.898 79.425,24.398 v1(80.175,24.398) ; v1(120.275,69.375) 120.275,65.08 117.82,62.625 117.82,40.305 128.8,29.325 128.8,19.7 125.3,16.2 SB5.2@125.3,14.775 126.075,14.775 126.25,14.6 126.25,2.75 v1(126.275,2.725)
  Signal Layer 2 w0.1: v1(69.325,13.225) 69.57,13.47 69.57,22.695 v1(69.575,22.7) ; P1.12@102.82,67.49 104.955,69.625 115.05,69.625 115.3,69.375 v1(120.275,69.375)
  Bottom Layer w0.1: v1(70.25,3.025) 71.75,1.525 88.536,1.525 89.211,0.85 99.664,0.85 100.089,1.275 100.305,1.275 100.38,1.2 114.506,1.2 114.831,1.525 125.075,1.525 v1(126.275,2.725) ; U15.P14@79.775,23.998 v1(80.175,24.398)
PMOD9: CN10.5 P1.9 U15.M14 | length 160.4
  Top Layer w0.1: v1(69.15,13.875) 69.65,13.875 70.8,12.725 v1(70.8,3.45) ; v1(102.65,54.475) 102.65,53.85 102.518,53.718 102.518,30.821 103.1,30.239 103.1,14.625 103.425,14.3 103.425,5.15 v1(103.875,4.7)
  Signal Layer 2 w0.1: v1(69.15,13.875) 69.15,22.825 69.4,23.075 v1(70.175,23.075) ; v1(70.8,3.45) 71.3,2.95 76.575,2.95 77.075,3.45 77.775,3.45 78.15,3.075 79.275,3.075 79.65,3.45 80.2,3.45 80.575,3.075 84.192,3.075 84.717,3.6 85.35,3.6 85.925,3.025 87.425,3.025 88,2.45 95.22,2.45 96.72,3.95 103.125,3.95 v1(103.875,4.7) ; v1(102.65,54.475) 103.157,54.475 103.575,54.893 103.575,57.424 103.93,57.78 103.93,60.08 105.35,61.5 116.15,61.5 116.82,62.17 P1.9@116.82,65.49
  Bottom Layer w0.1: v1(70.175,23.075) 70.175,22.72 72.579,20.316 74.191,20.316 74.6,20.725 74.6,22.079 75.17,22.648 76.161,22.648 78.736,25.223 79.4,25.223 U15.M14@79.775,25.598 ; CN10.5@87.964,52.6 89.839,54.475 v1(102.65,54.475)
PMOD13-ADC: P1.13 SB44.2 | length 102.3
  Top Layer w0.1: v1(113,3.075) 113.82,3.895 v1@113.82,69.25
  Signal Layer 2 w0.1: v1(93.625,5.8) v1(93.625,9.975) ; P1.13@104.82,67.49 106.58,69.25 v1(113.825,69.25)
  Bottom Layer w0.1: SB44.2@92.75,10.95 92.75,10.85 93.25,10.35 v1(93.625,9.975) ; v1(93.625,5.8) 94.875,5.8 97.323,3.351 112.724,3.351 v1(113,3.075)
PMOD14-PWM: P1.14 U15.K1 | length 76.2
  Top Layer w0.1: v1(92.4,25.823) 94.302,25.823 94.9,25.225 94.9,24.725 96.65,22.975 97.625,22.975 98.175,22.425 v1(98.175,20.35) ; v1(108.45,63.975) 109.175,63.25 109.175,61.349 112.35,58.174 v1(112.35,20.35)
  Signal Layer 2 w0.1: P1.14@106.82,67.49 107.82,66.49 107.82,64.605 v1(108.45,63.975)
  Bottom Layer w0.1: U15.K1@90.175,27.198 91.403,27.198 92.227,26.374 92.227,25.996 v1(92.4,25.823) ; v1(98.175,20.35) 112.3,20.35 112.325,20.325 v1(112.35,20.35)
PMOD#8: CN10.4 P1.8 U15.M15 | length 163.7
  Top Layer w0.1: v1(68.35,13.875) 68.725,14.25 69.825,14.25 71.4,12.675 v1(71.4,3.975) ; v1(103.1,55.175) 103.333,54.942 103.333,50.925 103.3,50.892 103.3,14.708 103.725,14.283 103.725,9.7 105.3,8.125 v1(105.3,5.325)
  Signal Layer 2 w0.1: v1(68.35,13.875) 68.35,21.399 68.515,21.564 68.515,22.69 69.4,23.575 70.65,23.575 v1(70.925,23.3) ; v1(71.4,3.975) 73,5.575 84.525,5.575 85.3,4.8 85.3,3.933 86.008,3.225 87.508,3.225 87.816,2.916 88.028,2.916 88.245,2.7 93.15,2.7 93.2,2.65 95.125,2.65 96.625,4.15 102.525,4.15 103.7,5.325 v1(105.3,5.325) ; v1(103.1,55.175) 103.1,57.95 103.55,58.4 103.55,60.2 105.25,61.9 113.9,61.9 114.82,62.82 P1.8@114.82,65.49
  Bottom Layer w0.1: v1(70.925,23.3) 70.925,22.4 72.75,20.575 73.475,20.575 74.075,21.175 74.075,21.836 75.087,22.848 76.078,22.848 78.828,25.598 U15.M15@78.975,25.598 ; CN10.4@85.424,52.6 87.999,55.175 v1(103.1,55.175)
REFSEL0: R88.2 R89.1 U20.8 | length 3.5
  Bottom Layer w0.1: U20.8@25.75,16.725 R89.1@27.7,16.725 R88.2@29.225,16.725
REFSEL1: R100.2 R103.1 U20.11 | length 3.4
  Bottom Layer w0.1: R103.1@24.075,12.65 R100.2@24.075,14.075 U20.11@24.075,16.05
REFSEL2: R101.2 R104.1 U20.14 | length 3.4
  Bottom Layer w0.1: R104.1@22.575,12.65 R101.2@22.575,14.075 U20.14@22.575,16.05
SAI1_FS_A: R53.2 U15.C2 | length 64.4
  Top Layer w0.1: v1(70.425,44.125) 70.425,44.1 72.33,46.005 80.595,46.005 81.842,44.758 87.186,44.758 88.096,43.848 v1(89.475,43.848)
  Signal Layer 2 w0.1: v1(42.15,41.1) 50.275,41.1 50.975,41.8 50.975,43.7 v1(50.55,44.125) ; v1(89.475,43.848) 89.95,43.373 v1(89.95,38.475)
  Bottom Layer w0.1: v1(42.15,41.1) R53.2@42.15,41.75 ; v1(50.55,44.125) v1(70.425,44.125) ; U15.C2@89.375,32.798 89.875,33.298 89.875,33.474 89.875,33.723 ; 89.875,33.723 89.875,37.225 89.95,37.3 v1(89.95,38.475)
SAI1_MCLK_A: R49.2 U15.G12 | length 46.5
  Signal Layer 2 w0.1: v1(45.525,44.725) 45.75,44.95 51.425,44.95 52.45,43.925 v1(52.45,40.625) ; v1(76.3,32.35) 78.227,30.423 80.55,30.423 v1(80.975,29.998)
  Bottom Layer w0.1: R49.2@44.875,44.725 v1(45.525,44.725) ; v1(52.45,40.625) 58.975,40.625 59.975,41.625 60.45,41.625 61.275,40.8 69.225,40.8 75.75,34.275 75.75,32.9 v1(76.3,32.35) ; v1(80.975,29.998) U15.G12@81.375,29.598
SAI1_SCK_A: R50.2 U15.D3 | length 66.9
  Top Layer w0.1: v1(52.475,45.15) 61.875,45.15 62.85,46.125 66.316,46.125 68.809,48.617 81.756,48.617 83.002,47.371 90.877,47.371 v1(91.15,47.098)
  Signal Layer 2 w0.1: v1(45.525,43.65) 45.05,44.125 45.05,44.85 45.35,45.15 v1(52.475,45.15)
  Bottom Layer w0.1: R50.2@44.875,43.65 v1(45.525,43.65) ; U15.D3@88.575,31.998 89.075,32.498 89.075,37.325 88.55,37.85 88.55,41.1 91.15,43.7 v1(91.15,47.098)
SAI1_SD_A: R59.2 U15.E4 | length 67.1
  Top Layer w0.1: v1(69.8,45.325) 71.596,47.121 81.058,47.121 82.304,45.874 87.758,45.874 88.408,45.223 v1(89.475,45.223) ; v1(88.175,31.598) 88.55,31.973 89.337,31.973 89.75,32.386 89.75,36.746 90.575,37.571 90.575,38.625 89.777,39.423 v1(89.15,39.423)
  Signal Layer 2 w0.1: v1(45.529,41.583) 50.283,41.583 50.625,41.925 50.625,43.475 49.9,44.2 v1(49.9,44.5) ; v1(89.15,39.423) 88.925,39.648 88.925,44.673 v1(89.475,45.223)
  Bottom Layer w0.1: R59.2@44.879,41.583 v1(45.529,41.583) ; v1(49.9,44.5) 68.975,44.5 v1(69.8,45.325) ; U15.E4@87.775,31.198 v1(88.175,31.598)
SAI1_SD_B: R46.2 U15.B1 | length 59.1
  Top Layer w0.1: v1(79.525,45.183) 80.378,45.183 81.537,44.023 86.881,44.023 88.63,42.275 90.75,42.275 v1(91.6,41.425)
  Signal Layer 2 w0.1: v1(45.525,47.925) 47.85,45.6 v1(49.75,45.6)
  Bottom Layer w0.1: R46.2@44.875,47.925 v1(45.525,47.925) ; v1(49.75,45.6) 50.55,46.4 78.308,46.4 v1(79.525,45.183) ; U15.B1@90.175,33.598 91,34.423 91,35.45 90.275,36.175 90.275,36.899 91.175,37.799 91.175,41 v1(91.6,41.425)
SDCKE1: R67.2 U15.R14 | length 80.9
  Top Layer w0.127: v1(68.14,21.885) 78.442,21.885 78.452,21.875 v1(79.375,22.798)
  Bottom Layer w0.127: R67.2@55.925,26.35 55.925,23.65 55.725,23.45 47.225,23.45 47.1,23.325 47.1,23.025 47.225,22.9 64.425,22.9 64.55,22.775 64.55,22.5 64.45,22.4 47.2,22.4 47.1,22.3 47.1,22 47.215,21.885 v1(68.14,21.885) ; v1(79.375,22.798) U15.R14@79.775,23.198
SDCLK: U14.F2 U15.F15 | length 81.3
  Bottom Layer w0.127: U14.F2@57.8,32.1 58.2,31.7 59.325,31.7 59.45,31.575 59.45,28.25 59.55,28.15 59.85,28.15 59.95,28.25 59.95,31.625 60.025,31.7 60.35,31.7 60.45,31.6 60.45,28.225 60.525,28.15 60.85,28.15 60.925,28.225 60.925,31.6 61.025,31.7 61.325,31.7 61.425,31.6 61.425,28.225 61.5,28.15 61.825,28.15 61.9,28.225 61.9,31.6 62,31.7 62.375,31.7 62.45,31.625 62.45,28.275 62.55,28.175 62.85,28.175 62.95,28.275 62.95,31.6 63.05,31.7 63.35,31.7 63.45,31.6 63.45,28.3 63.55,28.2 63.85,28.2 63.95,28.3 63.95,31.6 64.05,31.7 64.325,31.7 64.425,31.6 64.425,28.275 64.5,28.2 64.85,28.2 64.95,28.3 64.95,31.6 65.025,31.675 65.325,31.675 65.425,31.575 65.425,28.275 65.5,28.2 65.8,28.2 65.9,28.3 65.9,31.575 66,31.675 66.25,31.675 66.35,31.575 66.35,28.475 66.475,28.35 66.725,28.35 66.825,28.45 66.825,31.575 66.925,31.675 67.2,31.675 67.325,31.55 67.325,29.45 67.4,29.375 67.7,29.375 67.8,29.475 67.8,31.55 67.9,31.65 68.25,31.65 68.35,31.55 68.35,30.279 68.475,30.154 77.225,30.154 77.469,30.398 U15.F15@78.975,30.398
SDIO1_CK: CN4.5 U10.2 U10.9 U15.B12 | length 54.7
  Signal Layer 2 w0.1: 79.75,39.648 79.75,37.083 80.81,36.023 v1(81.35,36.023)
  Signal Layer 2 w0.102: v1(78.775,54.35) 78.775,53.775 79.275,53.275 79.275,51.9 79.475,51.7 79.475,49.95 79.01,49.485 79.01,44.115 79.976,43.149 79.976,41.243 79.75,41.017 79.75,39.648
  Bottom Layer w0.127: CN4.5@60.6,59.4 60.6,58.325 61.95,56.975 U10.2@61.95,56.47 U10.9@61.95,55.65 61.95,54.75 62.35,54.35 75.925,54.35 76.2,54.625 76.2,56.775 76.325,56.9 76.625,56.9 76.725,56.8 76.725,54.5 76.875,54.35 77.225,54.35 77.375,54.5 77.375,56.725 77.55,56.9 77.775,56.9 77.95,56.725 77.95,54.5 78.1,54.35 v1(78.775,54.35) ; v1(81.35,36.023) 80.975,35.648 80.975,33.998 U15.B12@81.375,33.598
SDIO1_CMD: CN4.3 R7.1 U10.1 U10.10 U15.B11 | length 51.8
  Top Layer w0.127: v1(60.95,54.9) R7.1@60.95,55.6
  Signal Layer 2 w0.1: 80.282,39.848 80.282,37.093 80.95,36.425 81.625,36.425 81.85,36.2 81.85,35.423
  Signal Layer 2 w0.102: 80.282,39.848 80.282,50.557 81.45,51.725 v1(81.45,54.175) ; v1(81.775,33.998) 81.375,34.398 81.375,34.948 81.85,35.423
  Bottom Layer w0.127: CN4.3@58.4,59.4 58.4,57.45 58.75,57.1 61.075,57.1 61.45,56.725 U10.1@61.45,56.47 U10.10@61.45,55.65 61.1,55.65 60.95,55.5 v1(60.95,54.9) 61.888,53.961 81.236,53.961 v1(81.45,54.175) ; v1(81.775,33.998) U15.B11@82.175,33.598
SDIO1_D0: CN4.7 R8.1 U10.4 U10.7 U15.F13 | length 52.9
  Top Layer w0.127: v1(62.95,54.9) R8.1@62.95,55.6
  Signal Layer 2 w0.102: v1(75.219,54.9) 75.219,54.563 75.106,54.45 75.106,50.444 75.219,50.331 75.219,48.623 76.075,47.767 76.075,41.875 75.219,41.019 75.219,33.998 78.419,30.798 v1(80.175,30.798)
  Bottom Layer w0.127: CN4.7@62.8,59.4 62.8,57.7 62.95,57.55 U10.4@62.95,56.47 U10.7@62.95,55.65 v1(62.95,54.9) 65.75,54.9 67.175,56.325 72.225,56.325 72.375,56.175 72.375,55.775 72.3,55.7 69.975,55.7 69.85,55.575 69.85,55.05 70,54.9 v1(75.219,54.9) ; v1(80.175,30.798) U15.F13@80.575,30.398
SDIO1_D2: CN4.1 R5.1 U9.1 U9.10 U15.A13 | length 49.8
  Top Layer w0.127: v1(55.65,54.925) R5.1@55.65,55.625
  Signal Layer 2 w0.1: 78.45,39.675 77.975,39.2 77.975,36.075 78.6,35.45 79.523,35.45 v1(80.175,34.798)
  Signal Layer 2 w0.102: v1(78.05,51) 78.05,43.75 78.45,43.35 78.45,39.848 78.45,39.675
  Bottom Layer w0.127: CN4.1@56.2,59.4 56.1,59.3 U9.1@56.1,56.475 U9.10@56.1,55.655 55.805,55.655 55.65,55.5 v1(55.65,54.925) 55.65,54.35 56.25,53.75 57.05,53.75 57.225,53.575 57.225,51.475 57.7,51 v1(78.05,51) ; v1(80.175,34.798) U15.A13@80.575,34.398
SDNCAS: U14.F7 U15.A5 | length 78
  Top Layer w0.127: v1(53.4,31.7) 53.011,32.089 51.312,32.089 50.519,32.881 50.519,39.758 51.886,41.125 52.775,41.125 53.463,40.437 58.137,40.437 58.225,40.525 58.225,40.725 58.1,40.85 54,40.85 53.85,41 53.85,41.2 53.95,41.3 58.2,41.3 58.319,41.419 58.319,41.606 58.2,41.725 52.9,41.725 52.8,41.825 52.8,42.039 52.911,42.15 66.45,42.15 67.6,43.3 71.725,43.3 71.987,43.562 80.348,43.562 81.411,42.498 v1(86.575,42.498)
  Bottom Layer w0.1: U15.A5@86.975,34.398 87,34.398 87,36.773
  Bottom Layer w0.127: v1(53.4,31.7) U14.F7@53.8,32.1 ; v1(86.575,42.498) 86.575,39.898 87,39.473 87,36.773
SDNE1: U14.G9 U15.M11 | length 79.4
  Signal Layer 2 w0.102: v1(50.725,20.55) 50.725,15.025 50.65,14.95 49.975,14.95 49.875,15.05 49.875,27.05 50,27.175 50.2,27.175 50.3,27.075 50.3,21.2 50.4,21.1 50.65,21.1 50.725,21.175 50.725,30.3 50.675,30.35 50.375,30.35 50.3,30.275 50.3,28.3 50.225,28.225 50,28.225 49.9,28.325 49.9,30.7 50.1,30.9 v1(51.8,30.9)
  Bottom Layer w0.1: 81.15,20.623 81.15,20.757 81.675,21.282 81.675,25.098 U15.M11@82.175,25.598
  Bottom Layer w0.127: v1(50.725,20.55) 70.5,20.55 71.864,19.186 79.873,19.186 81.15,20.463 81.15,20.623 ; v1(51.8,30.9) U14.G9@52.2,31.3
SDNRAS: U14.F8 U15.N8 | length 76.5
  Signal Layer 2 w0.102: v1(52.2,15.375) 52.2,28.975 52.275,29.05 52.5,29.05 52.625,28.925 52.625,20.775 52.725,20.675 53.275,20.675 53.35,20.75 53.35,29.4 53.2,29.55 52.425,29.55 52.2,29.775 52.2,31.3 v1(52.6,31.7)
  Bottom Layer w0.1: U15.N8@84.575,24.798 84.492,24.798 84.075,24.381 84.075,23.791 84.275,23.591 84.275,22.948 84.743,22.48
  Bottom Layer w0.127: v1(52.2,15.375) 52.215,15.36 81.435,15.36 85.03,18.956 85.03,22.193 84.743,22.48 ; v1(52.6,31.7) U14.F8@53,32.1
SDNWE: U14.F9 U15.P4 | length 76.6
  Signal Layer 2 w0.102: v1@48.599,14.975 48.599,18.25 48.699,18.35 48.975,18.35 49.05,18.275 49.05,15.075 49.15,14.975 49.4,14.975 49.5,15.075 49.5,27.475 49.275,27.7 48.749,27.7 48.599,27.85 48.599,31.349 48.95,31.7 v1(51.8,31.7)
  Bottom Layer w0.127: v1(48.6,14.979) 81.625,14.979 82.096,15.45 84.986,15.45 84.992,15.444 85.382,15.444 85.389,15.436 86.012,15.436 86.626,16.05 87.875,16.05 88.15,16.325 88.15,17.173 88.44,17.463 88.44,22.446 88.453,22.46 88.156,22.757 88.156,23.617 U15.P4@87.775,23.998 ; v1(51.8,31.7) U14.F9@52.2,32.1
STLK_SWCLK: CN17.2 U18.A14 U30.1 | length 16.2
  Bottom Layer w0.1: U18.A14@139.1,16.825 138.775,16.5 138.775,14.325 145.15,7.95 146.25,7.95 146.487,7.713 U30.1@146.487,6.85 CN17.2@148.75,6.85
STLK_SWDIO: CN17.4 U18.A15 U28.1 | length 15.2
  Bottom Layer w0.1: U18.A15@139.1,16.175 139.1,14.283 143.608,9.775 145.825,9.775 146.487,10.438 U28.1@146.487,11.925 148.745,11.925 CN17.4@148.75,11.93
STLK_VCP_RX: R28.2 U18.C10 | length 195.3
  Top Layer w0.1: v1(22.975,61.2) 28.525,55.65 28.525,45.625 23.35,40.45 23.35,31.767 22.45,30.867 22.45,23.1 20.775,21.425 20.775,16.625 22.45,14.95 22.45,14.525 27.425,9.55 v1(27.425,2.525) ; v1(133.325,3.025) 133.325,9.625 138.75,15.05 138.75,18.425 v1(138.4,18.775)
  Signal Layer 2 w0.1: v1(27.425,2.525) 27.975,1.975 41.734,1.975 42.259,1.45 99.138,1.45 99.763,2.075 100.637,2.075 100.737,1.975 129.501,1.975 130.551,3.025 v1(133.325,3.025)
  Bottom Layer w0.1: R28.2@22.15,61.2 v1(22.975,61.2) ; v1(138.4,18.775) 138.725,19.1 140.075,19.1 U18.C10@140.4,19.425
STLK_VCP_TX: R22.2 U18.A7 | length 210.9
  Top Layer w0.1: v1(22.975,73.1) 21.4,71.525 21.4,65 28.725,57.675 28.725,45.542 23.55,40.367 23.55,31.65 22.65,30.75 22.65,23.017 21.15,21.517 21.15,16.65 22.65,15.15 22.65,14.608 28.05,9.208 v1(28.05,3.05) ; v1(132.175,3.525) v1(132.175,21.375)
  Signal Layer 2 w0.1: v1(28.05,3.05) 28.925,2.175 41.817,2.175 42.342,1.65 99.055,1.65 99.705,2.3 100.695,2.3 100.82,2.175 129.375,2.175 130.725,3.525 v1(132.175,3.525)
  Bottom Layer w0.1: R22.2@22.15,73.1 v1(22.975,73.1) ; v1(132.175,21.375) U18.A7@139.1,21.375
T_NRSTA: R29.2 U18.P3 | length 220.4
  Top Layer w0.1: v1(16.75,2.625) 16.75,4.6 16.45,4.9 16.45,12.65 18.925,15.125 18.925,21.067 21.25,23.392 21.25,30.383 20.875,30.758 20.875,60.425 v1(19.825,61.475) ; v1(149.175,23.65) 150.225,22.6 v1(150.225,2.5)
  Signal Layer 2 w0.1: v1(16.75,2.625) 17.35,2.025 27.642,2.025 27.892,1.775 41.651,1.775 42.176,1.25 99.224,1.25 99.225,1.251 99.225,1.254 99.846,1.875 100.554,1.875 100.654,1.775 129.584,1.775 130.309,2.5 v1(150.225,2.5)
  Bottom Layer w0.1: v1(19.825,61.475) R29.2@19.825,62.3 ; U18.P3@147.55,23.975 147.875,23.65 v1(149.175,23.65)
T_PWR_ENn: R105.1 U18.R5 U24.4 | length 26.7
  Signal Layer 2 w0.1: v1(131.275,12.375) 135.425,12.375 141.45,18.4 148,18.4 148.9,19.3 v1(148.9,22.675)
  Bottom Layer w0.1: U24.4@130.525,13.75 R105.1@130.525,12.4 130.55,12.375 v1(131.275,12.375) ; U18.R5@148.2,22.675 v1(148.9,22.675)
T_PWR_EXT: R79.2 R82.2 U18.R4 | length 3.5
  Bottom Layer w0.1: U18.R4@148.2,23.325 148.25,23.275 149.025,23.275 150.1,22.2 R79.2@150.1,22.15 R82.2@150.1,21.1
T_SWCLKA: R32.2 U18.M11 | length 215.8
  Top Layer w0.1: v1(12.35,60.6) 13.425,59.525 13.425,57.242 16.025,54.642 16.025,51.342 16.925,50.442 16.925,40.808 15.589,39.471 15.589,30.763 19.6,26.752 19.6,23.375 18.05,21.825 18.05,15.675 15.2,12.825 v1(15.2,1.175) ; v1(146.575,1.175) v1(146.575,14.075)
  Signal Layer 2 w0.1: v1(15.2,1.175) 41.403,1.175 41.928,0.65 99.472,0.65 99.825,1.003 99.825,1.005 100.095,1.275 100.305,1.275 100.405,1.175 v1(146.575,1.175)
  Bottom Layer w0.1: v1(12.35,60.6) R32.2@13.175,60.6 ; U18.M11@146.25,18.775 146.575,18.45 v1(146.575,14.075)
T_SWDIO_IN: R68.1 U18.N12 | length 19.5
  Top Layer w0.1: v1(144.85,28.45) 149.15,28.45 149.45,28.15 149.45,25.35 148.75,24.65 148.75,23.35 149.05,23.05 149.055,23.05 149.85,22.255 149.85,17.95 v1(149.7,17.8)
  Bottom Layer w0.1: R68.1@144.85,27.8 v1(144.85,28.45) ; U18.N12@146.9,18.125 147.225,17.8 v1(149.7,17.8)
T_SWDIOA: R30.2 R68.2 U18.L2 | length 223.5
  Top Layer w0.1: v1(12.35,62.3) 13.8,60.85 13.8,57.15 16.225,54.725 16.225,51.425 17.125,50.525 17.125,40.725 15.789,39.389 15.789,30.987 20.475,26.3 20.475,23.375 18.425,21.325 18.425,15.425 15.6,12.6 v1(15.6,1.7) ; v1(131.7,1.575) 131.7,23.45 134.45,26.2 v1(144.85,26.2)
  Signal Layer 2 w0.1: v1(15.6,1.7) 15.925,1.375 41.486,1.375 42.011,0.85 99.389,0.85 99.625,1.086 99.625,1.088 100.012,1.475 100.388,1.475 100.488,1.375 129.75,1.375 129.95,1.575 v1(131.7,1.575)
  Bottom Layer w0.1: v1(12.35,62.3) R30.2@13.175,62.3 ; R68.2@144.85,26.9 v1(144.85,26.2) 145.275,25.775 145.275,24.95 U18.L2@145.6,24.625
T_SWOA: R31.2 U18.D12 | length 199.7
  Top Layer w0.1: v1(16.25,1.775) 16.25,2.7 16.075,2.875 16.075,12.65 18.725,15.3 18.725,21.15 21.05,23.475 21.05,30.3 20.625,30.725 20.625,50.55 19.825,51.35 v1(19.825,59.775) ; v1(132.725,1.975) 132.725,9.325 138.3,14.9 v1(138.3,17.8)
  Signal Layer 2 w0.1: v1(16.25,1.775) 27.609,1.775 27.809,1.575 41.569,1.575 42.094,1.05 99.306,1.05 99.425,1.169 99.425,1.171 99.929,1.675 100.471,1.675 100.571,1.575 129.667,1.575 130.067,1.975 v1(132.725,1.975)
  Bottom Layer w0.1: v1(19.825,59.775) R31.2@19.825,60.6 ; v1(138.3,17.8) 140.725,17.8 U18.D12@141.05,18.125
ULPI_CK: U15.N5 U20.1 | length 85.2
  Signal Layer 2 w0.102: v1(36.6,11.525) 39.526,8.599 72.234,8.599 74.66,11.025 85.95,11.025 88.15,13.225 88.15,15.643 88.149,15.644 88.149,17.697 88.376,17.924 88.376,20.597 87.775,21.198 87.775,23.73 87.531,23.974 87.529,23.974 87.375,24.129 v1(87.375,24.398)
  Bottom Layer w0.127: U20.1@25.75,20.225 34.45,20.225 36.6,18.075 v1(36.6,11.525) ; U15.N5@86.975,24.798 v1(87.375,24.398)
ULPI_D0: SB46.1 U15.R4 U20.3 | length 82.9
  Signal Layer 2 w0.102: v1(35.475,11.9) v1(35.475,11.9) 36.774,11.901 39.77,8.905 72.107,8.905 74.533,11.331 85.656,11.331 v1(87.575,13.25) 87.575,14.95 87.4,15.125 v1(87.4,16.498)
  Bottom Layer w0.127: U20.3@25.75,19.225 v1(26.65,19.225) 34.372,19.225 35.475,18.122 v1(35.475,11.9) ; v1(87.4,16.498) 87.4,20.923 87.775,21.298 U15.R4@87.775,23.198 ; SB46.1@87.575,12.05 v1(87.575,13.25)
ULPI_D1: SB47.2 U20.4 | length 70.4
  Signal Layer 2 w0.102: v1(35.05,9.925) 37.6,7.375 73.15,7.375 75.725,9.95 v1(84.8,9.95)
  Bottom Layer w0.127: U20.4@25.75,18.725 33.975,18.725 35.05,17.65 v1(35.05,9.925) ; SB47.2@84.775,10.95 84.8,10.925 v1(84.8,9.95)
ULPI_D2: U15.L7 U20.5 | length 83.4
  Signal Layer 2 w0.102: v1(34.55,12.3) 36.808,12.3 39.897,9.211 71.98,9.211 74.406,11.637 82.904,11.637 84.092,12.825 84.092,20.644 84.091,20.645 84.091,21.719 85.178,22.806 85.178,25.401 v1(85.775,25.998)
  Bottom Layer w0.127: U20.5@25.75,18.225 33.7,18.225 34.55,17.375 34.55,13.125 34.35,12.925 33.35,12.925 33.231,12.806 33.231,12.425 33.356,12.3 v1(34.55,12.3) ; U15.L7@85.375,26.398 v1(85.775,25.998)
ULPI_D3: U15.R13 U20.6 | length 83.3
  Signal Layer 2 w0.102: v1(34.1,13.975) 36.864,13.975 40.404,10.435 67.61,10.435 72.45,15.275 72.45,20.298 72.602,20.45 72.85,20.45 72.925,20.375 72.925,16.4 73.025,16.3 73.3,16.3 73.375,16.375 73.375,20.4 73.425,20.45 73.75,20.45 73.825,20.375 73.825,16.95 73.875,16.9 74.175,16.9 74.25,16.975 74.25,20.35 74.35,20.45 v1(76.55,20.45)
  Bottom Layer w0.127: U20.6@25.75,17.725 33.525,17.725 34.1,17.15 v1(34.1,13.975) ; v1(76.55,20.45) 78.296,20.45 80.575,22.728 U15.R13@80.575,23.198
ULPI_D4: U15.P13 U20.7 | length 96.4
  Signal Layer 2 w0.102: v1(33.5,13.55) 36.856,13.55 40.277,10.129 67.854,10.129 75,17.275 75,19.775 75.075,19.85 75.45,19.85 75.525,19.775 75.525,15.1 75.625,15 75.85,15 75.95,15.1 75.95,19.775 76.025,19.85 76.275,19.85 76.35,19.775 76.35,15.1 76.425,15.025 76.625,15.025 76.725,15.125 76.725,19.775 76.8,19.85 77.075,19.85 77.15,19.775 77.15,15.1 77.225,15.025 77.475,15.025 77.55,15.1 v1(77.55,21.25)
  Bottom Layer w0.127: U20.7@25.75,17.225 32.875,17.225 33.5,16.6 v1(33.5,13.55) ; v1(77.55,21.25) 78.477,21.25 80.175,22.948 80.175,23.598 U15.P13@80.575,23.998
ULPI_D5: SB49.2 U20.9 | length 57.7
  Signal Layer 2 w0.102: v1(75.025,9.925) 72.781,7.681 37.844,7.681 35.224,10.301 v1@32.851,10.301 ; v1(32.85,10.3) v1@32.851,10.301
  Bottom Layer w0.102: v1(75.025,9.925) SB49.2@75.025,10.95
  Bottom Layer w0.127: U20.9@25.075,16.05 25.075,15.481 25.175,15.381 26.083,15.381 27.339,14.125 32.4,14.125 32.85,13.675 v1(32.85,10.3)
ULPI_D6: U15.M13 U20.10 | length 91.8
  Signal Layer 2 w0.102: v1(32.075,13.65) 32.85,14.425 36.846,14.425 40.53,10.741 67.483,10.741 69.875,13.133 69.875,20.225 70,20.35 70.25,20.35 70.4,20.2 70.4,14.4 70.519,14.281 70.8,14.281 70.95,14.431 70.95,20.275 71.05,20.375 71.425,20.375 71.5,20.3 71.5,15.35 71.65,15.2 71.925,15.2 72.069,15.344 72.069,20.35 v1(72.847,21.128)
  Bottom Layer w0.127: U20.10@24.575,16.05 24.575,15.4 24.975,15 25.925,15 27.275,13.65 v1(32.075,13.65) ; v1(72.847,21.128) 74.935,23.216 75.926,23.216 78.668,25.958 80.215,25.958 U15.M13@80.575,25.598
ULPI_D7: U15.E7 U20.13 | length 84.8
  Signal Layer 2 w0.1: 84.774,23.041 84.774,23.25
  Signal Layer 2 w0.102: v1(23.3,15.075) 25.225,13.15 36.823,13.15 40.15,9.823 71.727,9.823 74.153,12.249 82.651,12.249 83.48,13.078 83.48,21.747 84.774,23.041 ; 84.774,23.25 84.774,26.047 85.375,26.648 85.375,31.198 v1(85.775,31.598)
  Bottom Layer w0.127: U20.13@23.075,16.05 23.075,15.3 v1(23.3,15.075) ; U15.E7@85.375,31.198 v1(85.775,31.598)
ULPI_DIR: U15.G5 U20.31 | length 91.9
  Signal Layer 2 w0.102: v1(24.575,21.725) 23.35,20.5 23.35,15.95 22.75,15.35 22.75,14.85 25.425,12.175 27.4,12.175 27.975,12.75 36.79,12.75 40.024,9.517 71.853,9.517 74.279,11.943 82.777,11.943 83.786,12.952 83.786,21.711 84.976,22.901 84.976,25.874 85.524,26.422 86.024,26.422 86.175,26.573 86.175,28.798 v1(86.575,29.198)
  Bottom Layer w0.127: U20.31@24.575,20.9 v1(24.575,21.725) ; v1(86.575,29.198) U15.G5@86.975,29.598
ULPI_NXT: U15.M5 U20.2 | length 87.2
  Signal Layer 2 w0.102: v1(36.025,11.1) 38.832,8.293 72.36,8.293 74.767,10.7 86.075,10.7 88.525,13.15 88.525,15.25 89.051,15.776 89.051,17.022 88.682,17.391 88.682,20.724 88,21.406 88,23.923 87.775,24.148 87.775,24.798 v1(87.375,25.198)
  Bottom Layer w0.127: U20.2@25.75,19.725 34.411,19.725 36.025,18.111 v1(36.025,11.1) ; U15.M5@86.975,25.598 v1(87.375,25.198)
ULPI_STP: U15.L3 U20.29 | length 97
  Signal Layer 2 w0.102: v1(23.575,21.725) 22.275,20.425 22.275,14.875 26.45,10.7 35.3,10.7 38.013,7.987 72.487,7.987 74.894,10.394 89.194,10.394 90.625,11.825 90.625,13.275 91.025,13.675 91.025,20.598 89.675,21.948 89.675,25.673 89.35,25.998 v1(88.975,25.998)
  Bottom Layer w0.127: U20.29@23.575,20.9 v1(23.575,21.725) ; U15.L3@88.575,26.398 v1(88.975,25.998)
USB_DEV_HS_CN_N: CN14.2 U22.5 | length 2.1
  Bottom Layer w0.155: U22.5@154.8,18.275 155.178,18.275 155.237,18.216 155.963,18.216 156.098,18.35 CN14.2@156.85,18.35
USB_DEV_HS_CN_P: CN14.3 U22.6 | length 2.2
  Bottom Layer w0.155: U22.6@154.8,17.775 155.178,17.775 155.237,17.835 ; 155.192,17.835 155.237,17.835 ; CN14.3@156.85,17.7 156.098,17.7 155.963,17.835 155.237,17.835
USB_DEV_HS_N: U18.R14 U22.2 | length 6
  Bottom Layer w0.155: U18.R14@148.2,16.825 148.334,16.691 150.327,16.691 151.852,18.216 153.063,18.216 153.122,18.275 U22.2@153.5,18.275
USB_DEV_HS_P: U18.R15 U22.1 | length 6
  Bottom Layer w0.155: U18.R15@148.2,16.175 148.334,16.31 150.484,16.31 152.009,17.835 153.063,17.835 153.122,17.775 U22.1@153.5,17.775
USB_HS_CN18_N: CN15.2 U23.6 | length 2.2
  Bottom Layer w0.155: CN15.2@4.125,16.8 5.127,16.8 5.417,17.09 5.713,17.09 5.772,17.15 U23.6@6.15,17.15
USB_HS_CN18_P: CN15.3 U23.5 | length 2.3
  Bottom Layer w0.155: CN15.3@4.125,16.15 4.878,16.15 5.012,16.284 5.15,16.284 5.575,16.709 5.713,16.709 5.772,16.65 U23.5@6.15,16.65
USB_HS_N: U20.19 U23.1 | length 15.6
  Bottom Layer w0.155: U23.1@7.45,17.15 7.828,17.15 7.887,17.09 12.898,17.09 14.214,15.775 19.525,15.775 19.719,15.969 19.719,17.308 20.077,17.665 20.388,17.665 20.448,17.725 U20.19@20.9,17.725
USB_HS_P: U20.18 U23.2 | length 15.6
  Bottom Layer w0.155: U23.2@7.45,16.65 7.828,16.65 7.887,16.709 12.741,16.709 14.056,15.394 19.683,15.394 20.1,15.811 20.1,17.15 20.235,17.284 20.388,17.284 20.448,17.225 U20.18@20.9,17.225
USB_OTG_HS_OVCR: LD8.2 R102.1 U15.L11 U25.3 | length 93.9
  Top Layer w0.1: v1(68.052,23.773) 75.265,23.773 75.267,23.775 77.602,23.775 79.45,25.623 81.4,25.623 v1(81.775,25.998)
  Signal Layer 2 w0.1: v1(12.025,12.65) 12.05,12.675 11.525,13.2 11.525,21.6 13.425,23.5 39,23.5 48.45,14.05 58.328,14.05 v1(68.052,23.773)
  Bottom Layer w0.1: R102.1@11.275,12.6 11.325,12.65 v1(12.025,12.65) 12.425,12.65 12.925,13.15 LD8.2@12.925,13.9 U25.3@14.575,13.9 ; v1(81.775,25.998) U15.L11@82.175,26.398
USB_VDDIO: C111.1 R72.2 R75.2 U20.32 | length 6.9
  Bottom Layer w0.1: R75.2@23.05,23.65 23.05,24.525 23.3,24.775 24.3,24.775 24.8,24.275 R72.2@25.275,24.275 25.2,24.2 C111.1@25.2,23.025 25.075,22.9 U20.32@25.075,20.9
USD_DETECT: CN4.10 R24.1 U15.C1 | length 101.9
  Top Layer w0.1: v1(103.82,73.845) 103.82,73.35 103.82,61.15 105.917,59.052 105.917,57.733 106.725,56.925 v1(106.725,44.9)
  Signal Layer 2 w0.1: v1(68.225,73.85) 80.775,73.85 81.15,74.225 103.44,74.225 v1(103.82,73.845) ; v1(90.575,33.198) 90.575,33.965 91.975,35.365 91.975,39.023 93.35,40.398 93.35,46.4 v1(93.7,46.75)
  Bottom Layer w0.1: CN4.10@65.95,69.6 68.15,69.6 R24.1@68.225,69.525 v1(68.225,73.85) ; U15.C1@90.175,32.798 v1(90.575,33.198) ; v1(93.7,46.75) 97.975,46.75 99.825,44.9 v1(106.725,44.9)
USER_LED1: R10.2 U15.B8 | length 172.8
  Top Layer w0.1: v1(7.825,8.85) 5.475,11.2 5.475,22.05 2.225,25.3 2.225,41.55 2.975,42.3 2.975,52.175 5.25,54.45 7.025,54.45 7.875,55.3 R10.2@7.875,55.475
  Signal Layer 2 w0.1: v1(84.975,33.998) 84.975,33.729 85.363,33.34 85.363,32.16 85.525,31.998 86.025,31.998 86.175,31.848 86.175,29.898 86.45,29.623 86.8,29.623 86.975,29.448 86.975,25.798 87.175,25.598 89.125,25.598 89.45,25.273 89.45,21.681 89.805,21.326 90.042,21.089 90.042,18.233 90.72,17.555 90.72,14.095 90.1,13.475 v1(90.1,13.075)
  Bottom Layer w0.1: v1(7.825,8.85) 12.875,3.8 17.725,3.8 19.325,2.2 26.4,2.2 32.55,8.35 46.575,8.35 50.625,12.4 64.05,12.4 67.6,8.85 77.275,8.85 77.775,9.35 83.325,9.35 83.7,8.975 88.075,8.975 88.45,9.35 89.717,9.35 89.725,9.343 90.1,9.718 v1(90.1,13.075)
  Bottom Layer w0.127: U15.B8@84.575,33.598 v1(84.975,33.998)
USER_LED2: R4.2 U15.H13 | length 124.4
  Top Layer w0.1: R4.2@7.875,57.325 7.875,57.125 8.475,56.525 8.475,54.9 7.525,53.95 5.35,53.95 3.225,51.825 3.225,42 2.475,41.25 2.475,25.95 4.725,23.7 v1(7.95,23.7)
  Signal Layer 2 w0.1: v1(7.95,23.7) 39.175,23.7 48.625,14.25 56.45,14.25 v1(66.525,24.325)
  Bottom Layer w0.1: v1(66.525,24.325) 70.173,27.973 75.45,27.973 75.775,28.298 80.075,28.298 U15.H13@80.575,28.798
VBAT: SB28.2 U15.E2 | length 18.1
  Signal Layer 2 w0.3: v1(89.775,31.598) 90.375,32.198 91.7,32.198 93.6,34.098 93.6,39.498 94.1,39.998 94.1,45.175 v1(94.35,45.425)
  Bottom Layer w0.2: U15.E2@89.375,31.198 v1(89.775,31.598)
  Bottom Layer w0.3: v1(94.35,45.425) SB28.2@95.425,45.425
VCAP: C15.1 C27.1 R13.1 SB38.1 U15.E6 U15.F11 U15.L8 | length 15.8
  Top Layer w0.15: C15.1@79.525,30.798 79.925,31.198 81.375,31.198 v1(81.775,30.798) 81.375,30.398 79.925,30.398 C15.1@79.525,30.798 ; 86.175,31.998 v1(86.575,31.598) 86.975,31.998 86.975,33.623 R13.1@86.625,33.973 86.175,33.523 86.175,31.998
  Top Layer w0.2: C27.1@84.275,25.648 84.275,26.098 v1(84.975,26.798)
  Bottom Layer w0.2: v1(81.775,30.798) U15.F11@82.175,30.398 ; U15.L8@84.575,26.398 v1(84.975,26.798) ; U15.E6@86.175,31.198 v1(86.575,31.598)
  Bottom Layer w0.3: v1(97.45,27.248) v1(97.45,28.173) SB38.1@97.45,29.348
VCP_T_RX: CN8.13 R22.1 U6.1 U15.E13 | length 98.1
  Top Layer w0.1: v1(49.25,72.575) 49.25,43.05 v1(49.675,42.625)
  Signal Layer 2 w0.1: v1(22.975,71.7) 23.85,72.575 v1(49.25,72.575) ; v1(77.325,35.558) 77.325,35.17 77.95,34.545 77.95,33.775 78.402,33.323 79.45,33.323 79.775,32.998 79.775,32.156 80.175,31.756 v1(80.175,31.598)
  Bottom Layer w0.1: CN8.13@20.91,69.314 20.91,71.615 U6.1@20.9,71.625 22.075,71.625 R22.1@22.15,71.7 v1(22.975,71.7) ; v1(49.675,42.625) 70.258,42.625 v1(77.325,35.558) ; v1(80.175,31.598) U15.E13@80.575,31.198
VCP_T_TX: CN8.14 R28.1 U8.1 U15.F12 | length 86
  Top Layer w0.1: v1(47.8,58.15) 47.8,43.3 v1(48.85,42.25)
  Signal Layer 2 w0.1: v1(22.975,62.6) 27.425,58.15 v1(47.8,58.15) ; v1(78.425,32.425) 78.852,31.998 79.65,31.998 79.775,31.873 79.775,31.373 79.95,31.198 80.575,31.198 v1(80.975,30.798)
  Bottom Layer w0.1: CN8.14@20.91,65.25 20.925,65.235 U8.1@20.925,62.637 22.113,62.637 R28.1@22.15,62.6 v1(22.975,62.6) ; v1(48.85,42.25) 60.108,42.25 61.283,41.075 69.3,41.075 76.162,34.212 76.162,33.288 77.025,32.425 v1(78.425,32.425) ; v1(80.975,30.798) U15.F12@81.375,30.398
VDD50_USB: SB35.2 SB36.2 U15.D15 | length 5.8
  Bottom Layer w0.3: SB35.2@74.675,33.173 SB36.2@74.675,31.773 78.75,31.773 U15.D15@78.975,31.998
VDD_LDO: C10.2 C35.2 R12.1 SB2.1 SB37.1 U15.E10 U15.F5 U15.L10 | length 16.4
  Top Layer w0.15: v1(82.575,31.598) 82.975,31.998 82.975,33.223 83.125,33.373
  Top Layer w0.3: SB2.1@81.575,22.448 82.075,22.948 C35.2@82.075,23.598 82.075,25.498 v1(82.575,25.998) ; 83.125,33.373 C10.2@84.075,34.323 84.075,35.773 84.525,36.223 86.425,36.223 v1(86.625,36.023) R12.1@86.625,35.023
  Bottom Layer w0.2: v1(82.575,25.998) U15.L10@82.975,26.398 ; v1(82.575,31.598) U15.E10@82.975,31.198 ; U15.F5@86.975,30.398 v1(87.375,29.998)
  Bottom Layer w0.3: v1(98.95,27.248) v1(98.95,28.173) SB37.1@98.95,29.348
VDD_MMC: SB30.2 U15.E8 | length 13.7
  Top Layer w0.15: v1(84.975,31.598) 85.375,31.998 85.375,35.198 v1(84.975,35.598)
  Bottom Layer w0.1: U15.E8@84.575,31.198 v1(84.975,31.598)
  Bottom Layer w0.3: SB30.2@83.05,41.873 85.002,41.873 85.342,41.533 85.342,39.467 84.65,38.775 84.65,35.923 v1(84.975,35.598)
VDD_SMPS_IND_OUT: C98.2 L1.2 SB34.2 SB37.2 SB38.2 | length 11.2
  Bottom Layer w0.3: L1.2@95.05,31.098 95.7,31.098 ; 95.7,31.098 96.525,31.923 C98.2@97.45,31.923 ; 95.7,31.098 96.35,30.448 SB38.2@97.45,30.448 ; SB38.2@97.45,30.448 SB37.2@98.95,30.448 SB34.2@98.95,32.248 98.625,31.923 C98.2@97.45,31.923 ; SB38.2@97.45,30.448 C98.2@97.45,31.923
VDD_SMPS_OUT: C99.2 L1.1 U15.F1 | length 7.5
  Bottom Layer w0.3: U15.F1@90.175,30.398 90.725,30.398 92.012,31.686 ; 92.012,31.686 92.6,31.098 L1.1@93.55,31.098 C99.2@93.55,32.548 92.875,32.548 92.012,31.686
VFBSD: R12.2 R13.2 R14.1 U15.F2 | length 16.1
  Top Layer w0.3: v1@86.575,36.906 87.525,35.956 R12.2@87.525,35.023 R13.2@87.525,33.973 ; v1(91.25,31.623) 91.85,32.223 R14.1@91.85,32.398
  Signal Layer 4 w0.3: v1(86.575,36.948) 89.35,36.948 91.825,34.473 91.825,32.198 v1(91.25,31.623)
  Bottom Layer w0.1: U15.F2@89.375,30.398 89.875,30.898 90.525,30.898 v1(91.25,31.623)
VIN: C5.2 CN19.8 U3.3 | length 3.9
  Top Layer w0.8: U3.3@10.799,34.272 C5.2@12.899,34.272 v1(12.899,36.047)
  other v1: 48.2,26.025 48.2,26.9 12.899,35.372
VREGOUT33: C89.2 SB29.2 SB30.1 U15.H11 | length 16.7
  Top Layer w0.15: v1(81.775,29.198) 82.175,29.598 82.175,35.173
  Top Layer w0.3: v1(81.775,37.398) 82.175,36.998 82.175,35.173
  Bottom Layer w0.1: v1(81.775,29.198) U15.H11@82.175,28.798
  Bottom Layer w0.3: v1(81.775,37.398) C89.2@81.775,41.698 81.775,42.848 SB29.2@81.45,43.173 82.85,43.173 SB30.1@83.05,42.973
WAKEUP: B2.3 B2.4 C90.2 R11.2 U2.1 U15.F4 | length 137.6
  Top Layer w0.1: B2.3@6.65,47.65 B2.4@6.65,52.1 7.975,52.1 U2.1@8.425,51.65 R11.2@8.425,50.4 8.4,50.425 v1(7.4,50.425)
  Signal Layer 2 w0.1: v1(87.375,30.798) 87.775,31.198 89.105,31.198 89.35,31.443 89.35,32.198 89.775,32.623 91.438,32.623 93.275,34.46 93.275,38.325 v1(92.75,38.85)
  Bottom Layer w0.1: v1(7.4,50.425) 7.4,51.025 7.625,51.25 13.175,51.25 ; 13.2,51.225 14.65,49.775 14.65,43.725 15.6,42.775 31.108,42.775 36.158,37.725 44.267,37.725 47.625,41.083 47.625,46.625 48.375,47.375 86.667,47.375 90.017,50.725 92.108,50.725 93.125,49.708 93.125,45.05 92.4,44.325 92.4,40.679 92.75,40.329 C90.2@92.75,39.5 v1(92.75,38.85) ; v1(87.375,30.798) U15.F4@87.775,30.398
WIFI_BOOT: U5.39 U15.A14 | length 109.8
  Top Layer w0.1: v1(106.15,40.225) v1(106.15,55.6)
  Signal Layer 2 w0.1: v1(78.65,55.525) 78.4,55.275 78.4,53.719 78.97,53.149 78.97,51.705 79.15,51.525 79.15,50.2 78.705,49.755 78.705,43.989 79.15,43.544 79.15,39.048 v1(79.375,38.823)
  Bottom Layer w0.1: v1(78.65,55.525) 78.725,55.6 v1(106.15,55.6) ; v1(79.375,38.823) 79.775,38.423 U15.A14@79.775,34.398 ; v1(106.15,40.225) 136.825,40.225 144.085,47.485 U5.39@147.861,47.485
WIFI_DATRDY: SB27.1 U15.B2 | length 82.3
  Top Layer w0.1: v1(151.875,39.7) v1(151.875,46.5)
  Bottom Layer w0.1: U15.B2@89.375,33.598 89.675,33.898 89.675,37.9 89.575,38 89.575,40.2 91.175,41.8 91.755,41.8 91.975,41.58 91.975,41.27 91.4,40.695 91.4,38.525 91.65,38.275 93.675,38.275 95.1,39.7 v1(151.875,39.7) ; SB27.1@150.775,46.5 v1(151.875,46.5)
WIFI_GPIO: SB17.2 U15.A2 | length 54.4
  Top Layer w0.1: v1(115.15,40.75) v1(115.15,53.95)
  Bottom Layer w0.1: U15.A2@89.375,34.398 89.375,37.693 88.75,38.318 88.75,39.75 91.1,42.1 91.738,42.1 92.175,41.663 92.175,41.187 91.65,40.662 91.65,38.875 92.05,38.475 93.575,38.475 95.85,40.75 v1(115.15,40.75) ; v1(115.15,53.95) SB17.2@118.55,53.95
WIFI_RST: SB16.2 U15.E11 | length 137.6
  Top Layer w0.1: v1(59.2,70.275) v1(59.2,73.15) ; v1(79.1,36.625) 79.775,35.95 79.775,33.698 79.875,33.598 80.4,33.598 80.575,33.423 80.575,32.123 80.675,32.023 81.35,32.023 v1(81.775,31.598) ; v1(107.82,55.43) v1(107.82,73.175)
  Signal Layer 2 w0.1: v1(59.2,70.275) 59.2,57.583 57.175,55.558 57.175,49.2 v1(60.7,45.675) ; v1(59.2,73.15) 64.317,73.15 64.592,73.425 104.925,73.425 105.1,73.6 107.395,73.6 v1(107.82,73.175)
  Bottom Layer w0.1: v1(60.7,45.675) 61.225,45.15 63.005,45.15 63.655,45.8 69.925,45.8 70.475,45.25 70.475,44.733 78.583,36.625 v1(79.1,36.625) ; v1(81.775,31.598) U15.E11@82.175,31.198 ; v1(107.82,55.43) 118.495,55.43 SB16.2@118.55,55.375
WIFI_WKUP: SB14.2 U15.D12 | length 133.3
  Top Layer w0.1: v1(59.575,69.5) v1(59.575,72.55) ; v1(79.3,38.025) 79.975,37.35 79.975,35.723 80.675,35.023 80.675,34.029 81.35,33.354 81.35,32.773 v1(80.975,32.398) ; v1(105.82,73.125) 105.82,61.455 106.4,60.875 v1(106.4,58.95)
  Signal Layer 2 w0.1: v1(59.575,69.5) 59.575,57.675 57.375,55.475 57.375,49.925 v1(61.575,45.725) ; v1(59.575,72.55) 64,72.55 64.675,73.225 78.625,73.225 78.725,73.125 v1(105.82,73.125)
  Bottom Layer w0.1: v1(61.575,45.725) 62.05,46.2 70.533,46.2 72.708,44.025 75.95,44.025 76.258,43.717 76.258,40.475 76.708,40.025 77.3,40.025 v1(79.3,38.025) ; v1(80.975,32.398) U15.D12@81.375,31.998 ; v1(106.4,58.95) 107.1,58.25 SB14.2@118.55,58.25
pads on no net: CN1.41 CN1.42 CN1.44 CN1.46 CN1.48 CN1.PTH1 CN1.PTH2 CN3.8 CN3.9 CN3.11 CN3.13 CN3.14 CN3.15 CN3.16 CN3.17 CN3.18 CN4.NPTH1 CN4.NPTH2 CN5.2 CN5.5 CN5.7 CN5.MT1 CN5.MT2 CN6.2 CN6.5 CN6.7 CN6.MT1 CN6.MT2 CN7.2 CN7.3 CN7.12 CN7.13 CN7.18 CN7.22 CN7.24 CN7.31 CN7.32 CN8.0 CN8.1 CN8.2 CN8.9 CN8.10 CN12.7 CN12.11 CN12.12 CN12.13 CN14.4 CN15.11 CN15.12 CN16.1 CN16.3 CN16.7 Designator1.1 Designator2.1 Designator3.1 Designator4.1 Designator5.1 Designator6.1 U5.6 U5.7 U5.16 U5.17 U5.18 U5.19 U5.20 U5.21 U5.22 U5.23 U5.24 U5.25 U5.26 U5.27 U5.31 U5.32 U5.38 U9.4 U9.5 U9.6 U9.7 U11.4 U11.5 U13.17 U13.19 U13.20 U14.E2 U14.G1 U17.3 U18.A1 U18.A2 U18.A3 U18.A4 U18.A5 U18.A6 U18.A8 U18.A9 U18.A10 U18.A11 U18.A12 U18.A13 U18.B1 U18.B2 U18.B3 U18.B4 U18.B5 U18.B6 U18.B7 U18.B8 U18.B9 U18.B10 U18.B11 U18.B12 U18.B13 U18.B14 U18.B15 U18.C2 U18.C3 U18.C4 U18.C11 U18.C12 U18.C13 U18.C14 U18.C15 U18.D1 U18.D2 U18.D3 U18.D4 U18.D10 U18.D11 U18.D13 U18.D14 U18.E1 U18.E2 U18.E3 U18.E4 U18.E12 U18.E13 U18.E14 U18.E15 U18.F1 U18.F4 U18.F14 U18.G4 U18.G14 U18.G15 U18.H1 U18.H2 U18.H3 U18.H4 U18.H14 U18.H15 U18.J2 U18.J3 U18.J4 U18.K1 U18.K2 U18.K3 U18.K12 U18.K14 U18.K15 U18.L1 U18.L3 U18.L12 U18.L13 U18.L14 U18.L15 U18.M2 U18.M3 U18.M4 U18.M5 U18.M6 U18.M7 U18.M12 U18.M13 U18.M14 U18.M15 U18.N2 U18.N4 U18.N5 U18.N6 U18.N7 U18.N11 U18.N13 U18.N14 U18.N15 U18.P2 U18.P4 U18.P5 U18.P6 U18.P7 U18.P8 U18.P9 U18.P10 U18.P11 U18.P12 U18.P13 U18.P14 U18.P15 U18.R2 U18.R3 U18.R6 U18.R7 U18.R8 U18.R9 U18.R10 U18.R11 U18.R12 U18.R13 U20.12 U20.15 U20.16 U20.25 U22.4 U23.4 U27.A2 U27.A3 U27.B1 U27.B5 U27.C5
